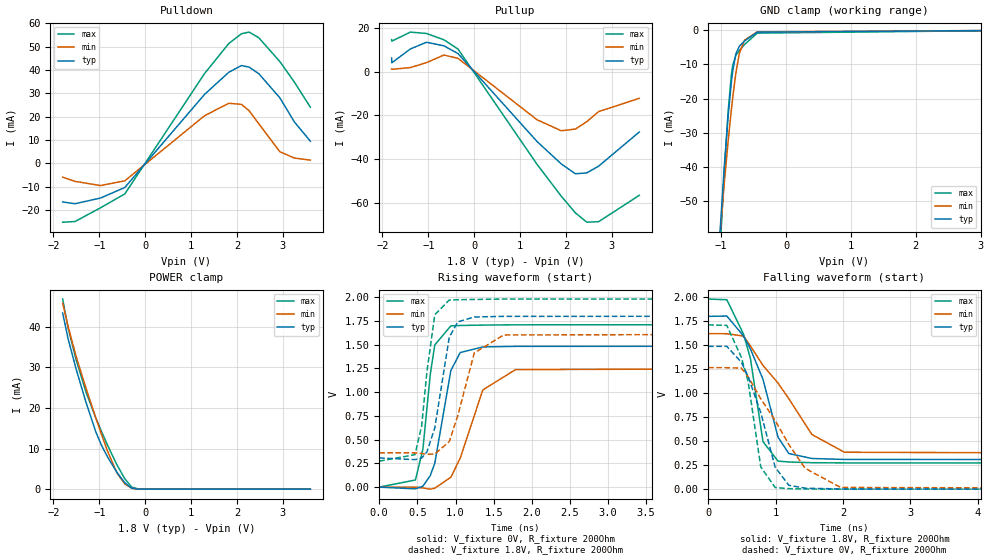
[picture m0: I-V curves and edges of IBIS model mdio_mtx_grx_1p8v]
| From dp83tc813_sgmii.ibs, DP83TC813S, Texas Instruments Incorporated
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| mdio_mtx_grx_1p8v
[Model]   mdio_mtx_grx_1p8v
Model_type   I/O
Polarity   Non-Inverting
Enable   Active-Low
Vinl = 0.63
Vinh = 1.17
Vmeas = 0.9
Vref = 0.9
Cref = 2pF
Rref = 100000
|   typ   min   max
C_comp   2.12pF   2.1pF   2.15pF
[Voltage Range]   1.8   1.62   1.98
[Temperature Range]   27   150   -40
[Pullup Reference]   1.8   1.62   1.98
[Pulldown Reference]   0   0   0
[Power Clamp Reference]   1.8   1.62   1.98
[GND Clamp Reference]   0   0   0
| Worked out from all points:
|   slope of the pulldown table from 0 to 0.27 V, typ, clamps not added: 41.1 ohm
|   slope of the pullup table from 0 to 0.27 V, typ, clamps not added: 40.5 ohm
|   GND clamp passes 1 mA (typ) near -0.48 V on its own axis
|   POWER clamp passes 1 mA (typ) near -0.39 V on its own axis
|   falling waveform, V_fixture 1.8V, R_fixture 200Ohm: 20-80 % time 408ps typ, 753ps min, 268ps max; typ from 1.8 V to 0.307 V
|   rising waveform, V_fixture 0V, R_fixture 200Ohm: 20-80 % time 184ps typ, 311ps min, 137ps max; typ from 0 V to 1.49 V
|   rising waveform, V_fixture 1.8V, R_fixture 200Ohm: 20-80 % time 169ps typ, 235ps min, 133ps max; typ from 0.307 V to 1.8 V
|   falling waveform, V_fixture 0V, R_fixture 200Ohm: 20-80 % time 376ps typ, 673ps min, 250ps max; typ from 1.49 V to 0 V
[Pulldown]
|   Voltage   I(typ)   I(min)   I(max)
-1.8V     -16.61mA   -5.947mA   -25.29mA
-1.53V    -17.36mA   -7.777mA   -25mA
-973.8mV  -14.92mA   -9.557mA   -19.1mA
-444.6mV  -10.39mA   -7.539mA   -13.15mA
1.294V    29.56mA    20.41mA    38.51mA
1.823V    39.07mA    25.75mA    51.41mA
2.099V    41.94mA    25.27mA    55.59mA
2.266V    41.26mA    22.56mA    56.3mA
2.477V    38.44mA    16.93mA    53.86mA
2.936V    28.08mA    4.971mA    43.64mA
3.249V    17.82mA    2.251mA    34.94mA
3.6V      9.489mA    1.359mA    24.09mA
[GND Clamp]
|   Voltage   I(typ)   I(min)   I(max)
-1.8V     -336.1mA   -294mA     -377.2mA
-1.044V   -67.3mA    -66.5mA    -74.32mA
-1.006V   -55.59mA   -57.15mA   -60.5mA
-946.8mV  -38.53mA   -43.59mA   -40.01mA
-892.8mV  -25.18mA   -32.5mA    -23.85mA
-844.2mV  -15.46mA   -23.5mA    -13.26mA
-822.6mV  -12.02mA   -19.84mA   -10.34mA
-774mV    -6.89mA    -12.58mA   -7.326mA
-720mV    -4.668mA   -6.753mA   -5.905mA
-639mV    -3.109mA   -2.848mA   -4.151mA
-444.6mV  -532.9uA   -446.3uA   -818uA
3.6V      0A         0A         0A
[Pullup]
|   Voltage   I(typ)   I(min)   I(max)
-1.8V     6.22mA     1.188mA    14.62mA
-1.795V   4.054mA    1.043mA    13.95mA
-1.39V    10.39mA    1.866mA    18.09mA
-1.039V   13.43mA    4.114mA    17.44mA
-660.6mV  11.82mA    7.583mA    14.58mA
-352.8mV  8.262mA    6.081mA    10.34mA
1.37V     -31.95mA   -22mA      -42.39mA
1.899V    -42.23mA   -27.04mA   -56.98mA
2.207V    -46.73mA   -26.27mA   -64.62mA
2.455V    -46.33mA   -22.91mA   -68.88mA
2.714V    -43.23mA   -18.28mA   -68.64mA
3.6V      -27.62mA   -12.21mA   -56.59mA
[POWER Clamp]
|   Voltage   I(typ)   I(min)   I(max)
-1.8V     43.38mA    45.82mA    46.84mA
-1.681V   37.05mA    40.07mA    39.68mA
-1.508V   29.65mA    32.74mA    31.93mA
-1.292V   21.44mA    24.91mA    23.94mA
-1.082V   14.27mA    17.71mA    17.68mA
-963mV    11.04mA    13.8mA     14.48mA
-822.6mV  7.958mA    9.405mA    10.86mA
-617.4mV  4.151mA    3.997mA    6.014mA
-444.6mV  1.573mA    1.284mA    2.566mA
-293.4mV  232.3uA    227.3uA    490.3uA
-136.8mV  3.538uA    9.732uA    5.794uA
3.6V      0A         0A         0A
[Ramp]
R_load = 200
|   typ   min   max
dV/dt_r   0.892389/1.81073e-10   0.759601/3.10645e-10   1.02679/1.36983e-10
dV/dt_f   0.895516/4.08036e-10   0.754921/7.52235e-10   1.02395/2.67052e-10
[Falling Waveform]
V_fixture = 1.8V
V_fixture_min = 1.62V
V_fixture_max = 1.98V
R_fixture = 200Ohm
C_fixture = 0F
|   Time   V(typ)   V(min)   V(max)
0s        1.8V       1.62V      1.98V
276.7ps   1.803V     1.619V     1.973V
524ps     1.596V     1.594V     1.615V
626.1ps   1.461V     1.492V     1.363V
812.7ps   1.145V     1.289V     495.7mV
1.036ns   542.1mV    1.105V     292.1mV
1.196ns   371.1mV    942.3mV    283.1mV
1.538ns   319.5mV    569.6mV    275.6mV
2.021ns   309.6mV    384.6mV    273.4mV
12ns      307.4mV    361.7mV    273.4mV
[Rising Waveform]
V_fixture = 0V
V_fixture_min = 0V
V_fixture_max = 0V
R_fixture = 200Ohm
C_fixture = 0F
|   Time   V(typ)   V(min)   V(max)
0s        534.9nV    8.425uV    224.8nV
474.7ps   -17.92mV   -402.7uV   75.28mV
572.4ps   10.5mV     -8.954mV   399mV
668.9ps   120.7mV    -21.33mV   1.185V
728.4ps   251.9mV    -11.06mV   1.497V
938.9ps   1.227V     104.5mV    1.698V
1.062ns   1.417V     305.8mV    1.702V
1.358ns   1.476V     1.023V     1.706V
1.786ns   1.482V     1.237V     1.709V
12ns      1.487V     1.266V     1.711V
[Rising Waveform]
V_fixture = 1.8V
V_fixture_min = 1.62V
V_fixture_max = 1.98V
R_fixture = 200Ohm
C_fixture = 0F
|   Time   V(typ)   V(min)   V(max)
0s        307.4mV    361.7mV    273.4mV
468.6ps   289.8mV    361.3mV    342.1mV
556.3ps   306.3mV    354.5mV    643.3mV
624.7ps   370.8mV    345.3mV    1.212V
728.4ps   623.2mV    349.2mV    1.815V
918.5ps   1.579V     479mV      1.97V
1.03ns    1.74V      752.4mV    1.973V
1.246ns   1.791V     1.413V     1.976V
1.631ns   1.798V     1.602V     1.98V
12ns      1.8V       1.62V      1.98V
[Falling Waveform]
|Gnd
V_fixture = 0V
V_fixture_min = 0V
V_fixture_max = 0V
R_fixture = 200Ohm
C_fixture = 0F
|   Time   V(typ)   V(min)   V(max)
0s        1.487V     1.266V     1.711V
275.7ps   1.488V     1.265V     1.706V
491.1ps   1.323V     1.261V     1.375V
590.4ps   1.177V     1.174V     1.129V
780ps     797.4mV    941.5mV    231.5mV
994.1ps   227.8mV    715.1mV    16.73mV
1.196ns   40.64mV    465.6mV    5.236mV
1.436ns   10.26mV    218.3mV    1.905mV
1.964ns   1.912mV    17.63mV    60.45uV
12ns      701.3nV    8.425uV    337.2nV
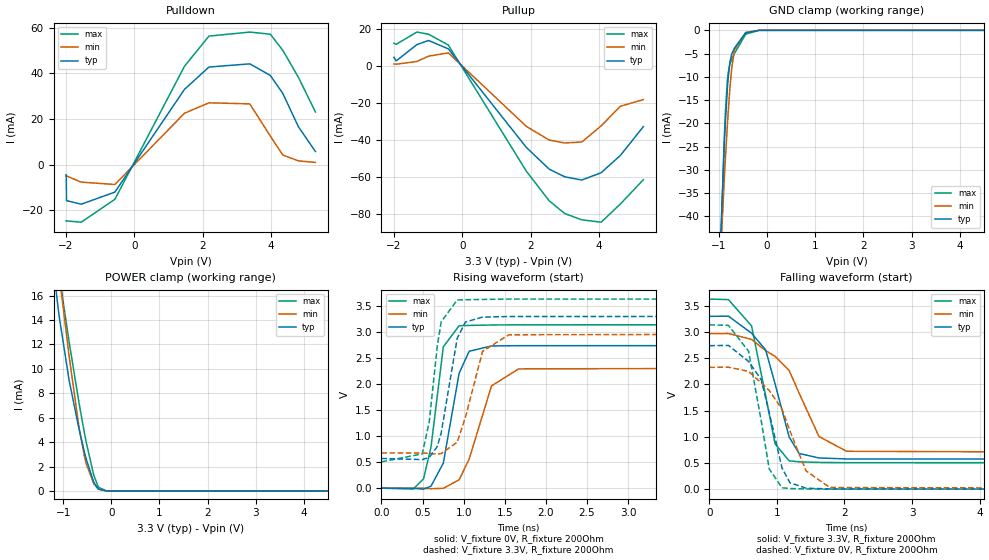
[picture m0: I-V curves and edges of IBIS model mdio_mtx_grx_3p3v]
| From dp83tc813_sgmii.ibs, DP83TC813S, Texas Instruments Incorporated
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| mdio_mtx_grx_3p3v
[Model]   mdio_mtx_grx_3p3v
Model_type   I/O
Polarity   Non-Inverting
Enable   Active-Low
Vinl = 0.8
Vinh = 2
Vmeas = 1.65
Vref = 1.65
Cref = 2pF
Rref = 100000
|   typ   min   max
C_comp   2.12pF   2.1pF   2.15pF
[Voltage Range]   3.3   2.97   3.63
[Temperature Range]   27   150   -40
[Pullup Reference]   3.3   2.97   3.63
[Pulldown Reference]   0   0   0
[Power Clamp Reference]   3.3   2.97   3.63
[GND Clamp Reference]   0   0   0
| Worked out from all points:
|   slope of the pulldown table from 0 to 0.495 V, typ, clamps not added: 41.6 ohm
|   slope of the pullup table from 0 to 0.495 V, typ, clamps not added: 39.9 ohm
|   GND clamp passes 1 mA (typ) near -0.49 V on its own axis
|   POWER clamp passes 1 mA (typ) near -0.39 V on its own axis
|   falling waveform, V_fixture 3.3V, R_fixture 200Ohm: 20-80 % time 353ps typ, 559ps min, 269ps max; typ from 3.3 V to 0.57 V
|   rising waveform, V_fixture 0V, R_fixture 200Ohm: 20-80 % time 180ps typ, 262ps min, 141ps max; typ from 0 V to 2.74 V
|   rising waveform, V_fixture 3.3V, R_fixture 200Ohm: 20-80 % time 166ps typ, 215ps min, 136ps max; typ from 0.57 V to 3.3 V
|   falling waveform, V_fixture 0V, R_fixture 200Ohm: 20-80 % time 307ps typ, 478ps min, 237ps max; typ from 2.74 V to 0 V
[Pulldown]
|   Voltage   I(typ)   I(min)   I(max)
-2V       -4.403mA   -4.924mA   -24.58mA
-1.993V   -4.541mA   -4.935mA   -24.61mA
-1.985V   -15.75mA   -4.948mA   -24.64mA
-1.555V   -17.32mA   -7.649mA   -25.19mA
-569.2mV  -12.01mA   -8.684mA   -15.16mA
1.468V    32.96mA    22.51mA    43.09mA
2.183V    42.73mA    27.07mA    56.27mA
3.38V     44.12mA    26.6mA     58.03mA
3.979V    39.05mA    12.51mA    57.1mA
4.344V    31.2mA     4.22mA     50.08mA
4.804V    16.53mA    1.646mA    38.17mA
5.3V      5.73mA     980.5uA    23.02mA
[GND Clamp]
|   Voltage   I(typ)   I(min)   I(max)
-2V       -410.8mA   -357.7mA   -461.5mA
-1.007V   -55.89mA   -57.39mA   -60.86mA
-890.4mV  -24.64mA   -32.04mA   -23.22mA
-868.5mV  -20.01mA   -27.88mA   -17.94mA
-824.7mV  -12.32mA   -20.18mA   -10.57mA
-810.1mV  -10.34mA   -17.83mA   -9.189mA
-773.6mV  -6.863mA   -12.53mA   -7.313mA
-737.1mV  -5.15mA    -8.294mA   -6.305mA
-678.7mV  -3.802mA   -4.182mA   -4.99mA
-445.1mV  -537.1uA   -449.4uA   -823.9uA
-167.7mV  -236.5nA   -1.623uA   -101.3nA
5.3V      0A         0A         0A
[Pullup]
|   Voltage   I(typ)   I(min)   I(max)
-2V       4.752mA    1.124mA    12.3mA
-1.934V   2.806mA    1.026mA    11.77mA
-1.328V   11.59mA    2.48mA     18.37mA
-985.3mV  13.84mA    5.379mA    17.21mA
-408.6mV  9.312mA    7.134mA    11.39mA
1.876V    -43.96mA   -32.6mA    -56.81mA
2.548V    -55.74mA   -40mA      -72.87mA
3.001V    -59.83mA   -41.53mA   -79.7mA
3.497V    -61.57mA   -41.03mA   -83.07mA
4.066V    -57.61mA   -32.28mA   -84.35mA
4.628V    -48.27mA   -21.7mA    -74.5mA
5.3V      -32.69mA   -18.12mA   -61.39mA
[POWER Clamp]
|   Voltage   I(typ)   I(min)   I(max)
-2V       56.47mA    56.33mA    67.3mA
-1.248V   19.83mA    23.38mA    22.5mA
-1.109V   15.13mA    18.64mA    18.44mA
-1.08V    14.23mA    17.66mA    17.64mA
-875.8mV  9.061mA    11.03mA    12.2mA
-671.4mV  5.088mA    5.236mA    7.225mA
-561.9mV  3.245mA    2.915mA    4.826mA
-518.1mV  2.577mA    2.208mA    3.938mA
-364.8mV  712.3uA    594.6uA    1.305mA
-269.9mV  142.9uA    154.2uA    311.7uA
-102mV    1.056uA    4.096uA    1.413uA
5.3V      0A         0A         0A
[Ramp]
R_load = 200
|   typ   min   max
dV/dt_r   1.64368/1.78613e-10   1.39503/2.6102e-10   1.8827/1.40644e-10
dV/dt_f   1.63826/3.52326e-10   1.37585/5.57652e-10   1.87516/2.67167e-10
[Falling Waveform]
V_fixture = 3.3V
V_fixture_min = 2.97V
V_fixture_max = 3.63V
R_fixture = 200Ohm
C_fixture = 0F
|   Time   V(typ)   V(min)   V(max)
0s        3.3V       2.97V      3.63V
282ps     3.304V     2.973V     3.62V
624.4ps   2.979V     2.86V      3.118V
833.6ps   2.658V     2.645V     1.783V
972ps     2.014V     2.536V     866.1mV
1.181ns   996.5mV    2.267V     541.2mV
1.328ns   682.2mV    1.835V     521.9mV
1.623ns   595.8mV    1.005V     511.2mV
2.031ns   577.1mV    723.4mV    505.7mV
12ns      569.5mV    676.9mV    504.7mV
[Rising Waveform]
V_fixture = 0V
V_fixture_min = 0V
V_fixture_max = 0V
R_fixture = 200Ohm
C_fixture = 0F
|   Time   V(typ)   V(min)   V(max)
0s        588.6nV    8.934uV    352.6nV
387.8ps   -2.528mV   -272.2uV   -16.8mV
512.6ps   -19.19mV   -1.192mV   180.2mV
603.3ps   38.47mV    -10.73mV   792.5mV
752.7ps   480.9mV    -2.587mV   2.714V
945.2ps   2.207V     161mV      3.119V
1.067ns   2.628V     558.3mV    3.124V
1.339ns   2.73V      1.964V     3.132V
1.669ns   2.735V     2.29V      3.136V
12ns      2.739V     2.325V     3.138V
[Rising Waveform]
V_fixture = 3.3V
V_fixture_min = 2.97V
V_fixture_max = 3.63V
R_fixture = 200Ohm
C_fixture = 0F
|   Time   V(typ)   V(min)   V(max)
0s        569.5mV    676.9mV    504.7mV
496.3ps   549.3mV    676.4mV    657.7mV
580.9ps   588.7mV    666.9mV    1.266V
678.5ps   797.6mV    654.2mV    2.715V
726.4ps   1.057V     664.1mV    3.192V
921.3ps   2.876V     880.9mV    3.613V
1.022ns   3.189V     1.363V     3.617V
1.23ns    3.284V     2.626V     3.623V
1.55ns    3.295V     2.945V     3.63V
12ns      3.3V       2.97V      3.63V
[Falling Waveform]
|Gnd
V_fixture = 0V
V_fixture_min = 0V
V_fixture_max = 0V
R_fixture = 200Ohm
C_fixture = 0F
|   Time   V(typ)   V(min)   V(max)
0s        2.74V      2.326V     3.138V
282ps     2.745V     2.329V     3.128V
580.9ps   2.439V     2.249V     2.634V
767.6ps   2.09V      2.029V     1.305V
886.2ps   1.46V      1.883V     385.2mV
1.075ns   406.9mV    1.532V     27.19mV
1.192ns   123mV      1.115V     12.24mV
1.43ns    18.79mV    350.9mV    4.725mV
1.782ns   4.844mV    31.51mV    172.8uV
12ns      750.5nV    9.194uV    441.3nV
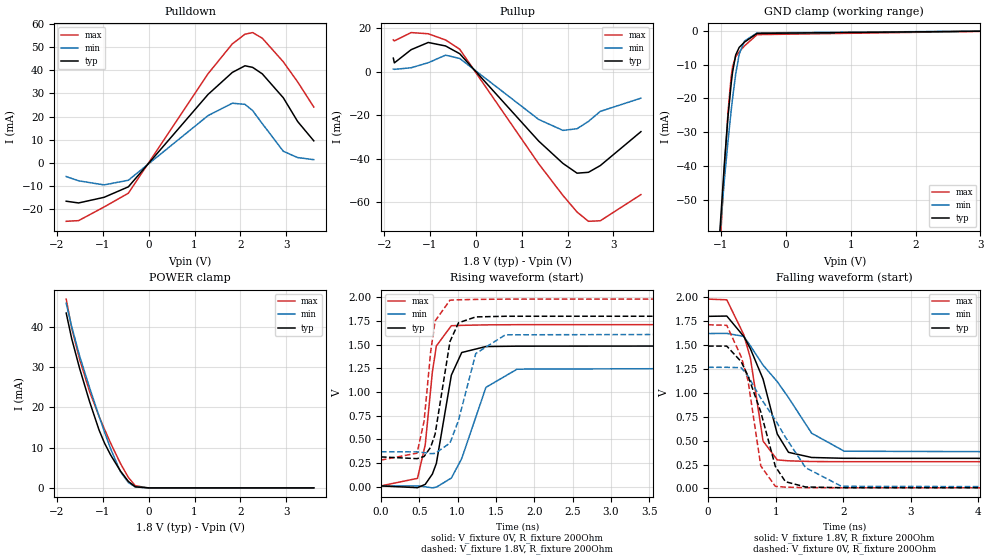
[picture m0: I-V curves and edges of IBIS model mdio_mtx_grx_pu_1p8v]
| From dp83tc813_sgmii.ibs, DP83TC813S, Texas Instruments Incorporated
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| mdio_mtx_grx_pu_1p8v
[Model]   mdio_mtx_grx_pu_1p8v
Model_type   I/O
Polarity   Non-Inverting
Enable   Active-Low
Vinl = 0.63
Vinh = 1.17
Vmeas = 0.9
Vref = 0.9
Cref = 2pF
Rref = 100000
|   typ   min   max
C_comp   2.12pF   2.10pF   2.14pF
[Voltage Range]   1.8   1.62   1.98
[Temperature Range]   27   150   -40
[Pullup Reference]   1.8   1.62   1.98
[Pulldown Reference]   0   0   0
[Power Clamp Reference]   1.8   1.62   1.98
[GND Clamp Reference]   0   0   0
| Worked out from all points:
|   slope of the pulldown table from 0 to 0.27 V, typ, clamps not added: 41.1 ohm
|   slope of the pullup table from 0 to 0.27 V, typ, clamps not added: 40.5 ohm
|   GND clamp passes 1 mA (typ) near -0.46 V on its own axis
|   POWER clamp passes 1 mA (typ) near -0.39 V on its own axis
|   falling waveform, V_fixture 1.8V, R_fixture 200Ohm: 20-80 % time 407ps typ, 753ps min, 269ps max; typ from 1.8 V to 0.313 V
|   rising waveform, V_fixture 0V, R_fixture 200Ohm: 20-80 % time 181ps typ, 310ps min, 137ps max; typ from 0.007 V to 1.49 V
|   rising waveform, V_fixture 1.8V, R_fixture 200Ohm: 20-80 % time 169ps typ, 233ps min, 132ps max; typ from 0.313 V to 1.8 V
|   falling waveform, V_fixture 0V, R_fixture 200Ohm: 20-80 % time 374ps typ, 673ps min, 251ps max; typ from 1.49 V to 0.007 V
[Pulldown]
|   Voltage   I(typ)   I(min)   I(max)
-1.8V     -16.61mA   -5.947mA   -25.29mA
-1.53V    -17.36mA   -7.777mA   -25mA
-973.8mV  -14.92mA   -9.557mA   -19.1mA
-444.6mV  -10.39mA   -7.539mA   -13.15mA
1.294V    29.56mA    20.41mA    38.51mA
1.823V    39.07mA    25.75mA    51.41mA
2.099V    41.94mA    25.27mA    55.59mA
2.266V    41.26mA    22.56mA    56.3mA
2.477V    38.44mA    16.93mA    53.86mA
2.936V    28.08mA    4.971mA    43.64mA
3.249V    17.82mA    2.251mA    34.94mA
3.6V      9.489mA    1.359mA    24.09mA
[GND Clamp]
|   Voltage   I(typ)   I(min)   I(max)
-1.8V     -336.4mA   -294.2mA   -377.5mA
-1.044V   -67.54mA   -66.68mA   -74.64mA
-1.006V   -55.83mA   -57.33mA   -60.82mA
-946.8mV  -38.77mA   -43.78mA   -40.33mA
-892.8mV  -25.42mA   -32.68mA   -24.17mA
-844.2mV  -15.7mA    -23.68mA   -13.58mA
-822.6mV  -12.26mA   -20.02mA   -10.66mA
-774mV    -7.13mA    -12.76mA   -7.644mA
-720mV    -4.907mA   -6.934mA   -6.222mA
-639mV    -3.348mA   -3.03mA    -4.466mA
-444.6mV  -767.3uA   -623.7uA   -1.129mA
3.6V      0A         0A         0A
[Pullup]
|   Voltage   I(typ)   I(min)   I(max)
-1.8V     6.22mA     1.188mA    14.62mA
-1.778V   4.031mA    1.063mA    14.17mA
-1.411V   10.12mA    1.794mA    17.99mA
-1.039V   13.43mA    4.114mA    17.44mA
-660.6mV  11.82mA    7.583mA    14.58mA
-352.8mV  8.262mA    6.081mA    10.34mA
1.37V     -31.95mA   -22mA      -42.39mA
1.899V    -42.23mA   -27.04mA   -56.98mA
2.207V    -46.73mA   -26.27mA   -64.62mA
2.455V    -46.33mA   -22.91mA   -68.88mA
2.714V    -43.23mA   -18.28mA   -68.64mA
3.6V      -27.62mA   -12.21mA   -56.59mA
[POWER Clamp]
|   Voltage   I(typ)   I(min)   I(max)
-1.8V     43.43mA    45.85mA    46.89mA
-1.681V   37.1mA     40.1mA     39.73mA
-1.508V   29.7mA     32.78mA    31.98mA
-1.292V   21.48mA    24.95mA    23.99mA
-1.082V   14.32mA    17.75mA    17.73mA
-963mV    11.08mA    13.83mA    14.53mA
-828mV    8.108mA    9.6mA      11.04mA
-617.4mV  4.189mA    4.028mA    6.056mA
-444.6mV  1.607mA    1.312mA    2.604mA
-293.4mV  259.8uA    249.4uA    522.6uA
-12.6mV   1.365uA    1.259uA    1.674uA
3.6V      0A         0A         0A
[Ramp]
R_load = 200
|   typ   min   max
dV/dt_r   0.889189/1.8029e-10   0.756668/3.07293e-10   1.02308/1.3633e-10
dV/dt_f   0.892188/4.07569e-10   0.751842/7.5158e-10   1.02019/2.66952e-10
[Falling Waveform]
V_fixture = 1.8V
V_fixture_min = 1.62V
V_fixture_max = 1.98V
R_fixture = 200Ohm
C_fixture = 0F
|   Time   V(typ)   V(min)   V(max)
0s        1.8V       1.62V      1.98V
276.9ps   1.803V     1.622V     1.973V
529ps     1.589V     1.59V      1.607V
626.8ps   1.46V      1.491V     1.361V
813.8ps   1.143V     1.289V     495.5mV
1.023ns   570.5mV    1.118V     298.8mV
1.19ns    377.9mV    950mV      289.1mV
1.532ns   324mV      577.9mV    281.7mV
2.015ns   315.5mV    389.6mV    279.8mV
12ns      313mV      366.8mV    279.6mV
[Rising Waveform]
V_fixture = 0V
V_fixture_min = 0V
V_fixture_max = 0V
R_fixture = 200Ohm
C_fixture = 0F
|   Time   V(typ)   V(min)   V(max)
0s        6.536mV    6.31mV     7.158mV
476.7ps   -12.08mV   5.883mV    86.33mV
577.8ps   23.13mV    -2.759mV   440.4mV
671ps     131.6mV    -14mV      1.21V
723.3ps   245.5mV    -6.063mV   1.486V
918.7ps   1.177V     89.49mV    1.699V
1.054ns   1.416V     295.9mV    1.703V
1.37ns    1.479V     1.048V     1.708V
1.777ns   1.483V     1.24V      1.71V
12ns      1.489V     1.267V     1.712V
[Rising Waveform]
V_fixture = 1.8V
V_fixture_min = 1.62V
V_fixture_max = 1.98V
R_fixture = 200Ohm
C_fixture = 0F
|   Time   V(typ)   V(min)   V(max)
0s        313mV      366.8mV    279.6mV
470.8ps   294.7mV    366.4mV    352.6mV
562.6ps   317.2mV    358.8mV    690mV
648.6ps   415.3mV    347.1mV    1.423V
706.7ps   553.3mV    349.7mV    1.749V
900.6ps   1.532V     459.5mV    1.969V
1.012ns   1.73V      699mV      1.973V
1.237ns   1.792V     1.405V     1.977V
1.623ns   1.799V     1.603V     1.98V
12ns      1.8V       1.62V      1.98V
[Falling Waveform]
|Gnd
V_fixture = 0V
V_fixture_min = 0V
V_fixture_max = 0V
R_fixture = 200Ohm
C_fixture = 0F
|   Time   V(typ)   V(min)   V(max)
0s        1.489V     1.267V     1.712V
276ps     1.489V     1.267V     1.706V
489.9ps   1.326V     1.263V     1.378V
590.4ps   1.178V     1.176V     1.131V
779.8ps   800.3mV    944mV      235.7mV
995.3ps   230.3mV    716.2mV    22.19mV
1.145ns   70.63mV    535.5mV    13.83mV
1.443ns   15.53mV    217.3mV    8.735mV
1.974ns   8.254mV    22.6mV     7.174mV
12ns      6.535mV    6.31mV     7.158mV
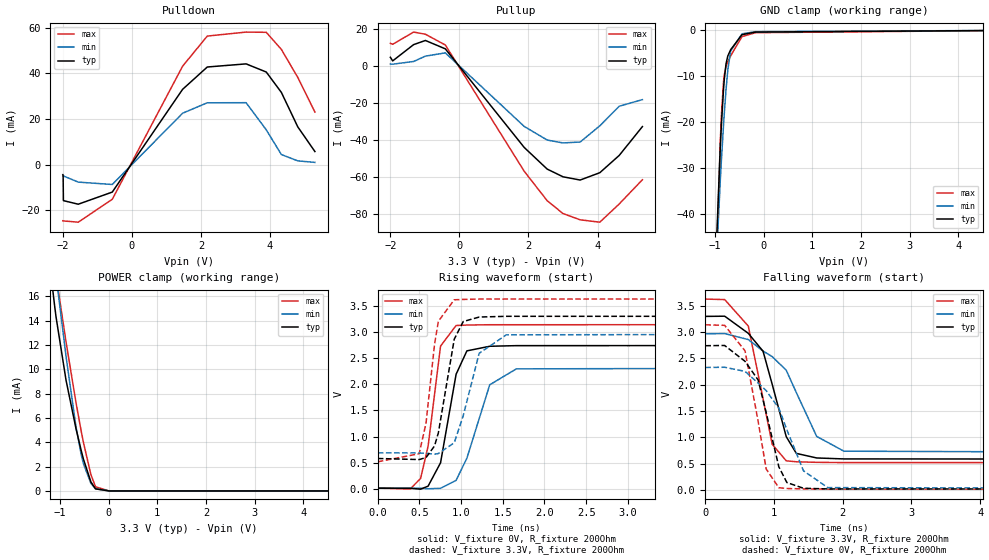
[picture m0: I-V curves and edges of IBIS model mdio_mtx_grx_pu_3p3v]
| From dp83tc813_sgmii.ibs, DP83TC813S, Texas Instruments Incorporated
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| mdio_mtx_grx_pu_3p3v
[Model]   mdio_mtx_grx_pu_3p3v
Model_type   I/O
Polarity   Non-Inverting
Enable   Active-Low
Vinl = 0.8
Vinh = 2
Vmeas = 1.65
Vref = 1.65
Cref = 2pF
Rref = 100000
|   typ   min   max
C_comp   2.12pF   2.1pF   2.14pF
[Voltage Range]   3.3   2.97   3.63
[Temperature Range]   27   150   -40
[Pullup Reference]   3.3   2.97   3.63
[Pulldown Reference]   0   0   0
[Power Clamp Reference]   3.3   2.97   3.63
[GND Clamp Reference]   0   0   0
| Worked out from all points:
|   slope of the pulldown table from 0 to 0.495 V, typ, clamps not added: 41.6 ohm
|   slope of the pullup table from 0 to 0.495 V, typ, clamps not added: 39.9 ohm
|   GND clamp passes 1 mA (typ) near -0.45 V on its own axis
|   POWER clamp passes 1 mA (typ) near -0.39 V on its own axis
|   falling waveform, V_fixture 3.3V, R_fixture 200Ohm: 20-80 % time 353ps typ, 559ps min, 269ps max; typ from 3.3 V to 0.58 V
|   rising waveform, V_fixture 0V, R_fixture 200Ohm: 20-80 % time 178ps typ, 260ps min, 141ps max; typ from 0.012 V to 2.74 V
|   rising waveform, V_fixture 3.3V, R_fixture 200Ohm: 20-80 % time 165ps typ, 214ps min, 135ps max; typ from 0.58 V to 3.3 V
|   falling waveform, V_fixture 0V, R_fixture 200Ohm: 20-80 % time 307ps typ, 478ps min, 237ps max; typ from 2.74 V to 0.012 V
[Pulldown]
|   Voltage   I(typ)   I(min)   I(max)
-2V       -4.403mA   -4.924mA   -24.58mA
-1.993V   -4.541mA   -4.935mA   -24.61mA
-1.985V   -15.75mA   -4.948mA   -24.64mA
-1.555V   -17.32mA   -7.649mA   -25.19mA
-569.2mV  -12.01mA   -8.684mA   -15.16mA
1.468V    32.96mA    22.51mA    43.09mA
2.183V    42.73mA    27.07mA    56.27mA
3.307V    44.1mA     27.11mA    58.01mA
3.891V    40.53mA    15.22mA    57.91mA
4.329V    31.6mA     4.414mA    50.42mA
4.804V    16.53mA    1.646mA    38.17mA
5.3V      5.73mA     980.5uA    23.02mA
[GND Clamp]
|   Voltage   I(typ)   I(min)   I(max)
-2V       -411.3mA   -358mA     -462.1mA
-1.007V   -56.3mA    -57.7mA    -61.41mA
-890.4mV  -25.05mA   -32.35mA   -23.77mA
-868.5mV  -20.42mA   -28.19mA   -18.49mA
-824.7mV  -12.74mA   -20.5mA    -11.12mA
-810.1mV  -10.75mA   -18.14mA   -9.736mA
-773.6mV  -7.273mA   -12.84mA   -7.86mA
-737.1mV  -5.56mA    -8.607mA   -6.851mA
-678.7mV  -4.211mA   -4.494mA   -5.536mA
-445.1mV  -941.1uA   -756.5uA   -1.363mA
-167.7mV  -380.7uA   -289.5uA   -511.4uA
5.3V      0A         0A         0A
[Pullup]
|   Voltage   I(typ)   I(min)   I(max)
-2V       4.752mA    1.124mA    12.3mA
-1.934V   2.807mA    1.026mA    11.77mA
-1.328V   11.59mA    2.48mA     18.37mA
-985.3mV  13.84mA    5.379mA    17.21mA
-408.6mV  9.312mA    7.134mA    11.39mA
1.876V    -43.96mA   -32.6mA    -56.81mA
2.541V    -55.65mA   -39.95mA   -72.73mA
3.001V    -59.83mA   -41.53mA   -79.7mA
3.497V    -61.57mA   -41.03mA   -83.07mA
4.066V    -57.61mA   -32.28mA   -84.35mA
4.628V    -48.27mA   -21.7mA    -74.5mA
5.3V      -32.69mA   -18.12mA   -61.4mA
[POWER Clamp]
|   Voltage   I(typ)   I(min)   I(max)
-2V       56.52mA    56.37mA    67.37mA
-1.248V   19.88mA    23.41mA    22.56mA
-1.109V   15.17mA    18.68mA    18.5mA
-1.08V    14.27mA    17.7mA     17.69mA
-875.8mV  9.104mA    11.06mA    12.25mA
-671.4mV  5.128mA    5.269mA    7.27mA
-561.9mV  3.283mA    2.947mA    4.869mA
-518.1mV  2.614mA    2.238mA    3.979mA
-364.8mV  743.9uA    620.5uA    1.342mA
-269.9mV  169.6uA    175.9uA    343.1uA
7.5mV     0A         0A         0A
5.3V      0A         0A         0A
[Ramp]
R_load = 200
|   typ   min   max
dV/dt_r   1.6377/1.77579e-10   1.38953/2.59061e-10   1.8758/1.39983e-10
dV/dt_f   1.63191/3.52219e-10   1.36981/5.58182e-10   1.86805/2.67002e-10
[Falling Waveform]
V_fixture = 3.3V
V_fixture_min = 2.97V
V_fixture_max = 3.63V
R_fixture = 200Ohm
C_fixture = 0F
|   Time   V(typ)   V(min)   V(max)
0s        3.3V       2.97V      3.63V
282.3ps   3.304V     2.973V     3.62V
625.7ps   2.978V     2.859V     3.116V
840.5ps   2.637V     2.64V      1.734V
973.8ps   2.006V     2.535V     865.2mV
1.178ns   1.011V     2.275V     551.3mV
1.325ns   692.5mV    1.849V     533mV
1.621ns   605.7mV    1.016V     522.6mV
2.017ns   587.6mV    734.7mV    517.4mV
12ns      580.1mV    686.9mV    516.6mV
[Rising Waveform]
V_fixture = 0V
V_fixture_min = 0V
V_fixture_max = 0V
R_fixture = 200Ohm
C_fixture = 0F
|   Time   V(typ)   V(min)   V(max)
0s        12.2mV     11.93mV    13.35mV
388ps     9.801mV    11.65mV    -3.337mV
513.5ps   -6.748mV   10.65mV    197.3mV
603.6ps   51.2mV     1.201mV    815.2mV
753ps     497.6mV    9.346mV    2.731V
939.5ps   2.191V     162mV      3.124V
1.069ns   2.639V     585.7mV    3.133V
1.343ns   2.727V     1.99V      3.139V
1.663ns   2.739V     2.295V     3.139V
12ns      2.742V     2.328V     3.14V
[Rising Waveform]
V_fixture = 3.3V
V_fixture_min = 2.97V
V_fixture_max = 3.63V
R_fixture = 200Ohm
C_fixture = 0F
|   Time   V(typ)   V(min)   V(max)
0s        580.1mV    686.9mV    516.6mV
496.8ps   559.7mV    686.5mV    672.1mV
578.5ps   597.8mV    677.3mV    1.254V
680.7ps   818.9mV    664mV      2.761V
726.7ps   1.071V     674.3mV    3.205V
917.3ps   2.862V     881.5mV    3.616V
1.025ns   3.2V       1.399V     3.623V
1.216ns   3.286V     2.592V     3.63V
1.542ns   3.3V       2.946V     3.63V
12ns      3.3V       2.97V      3.63V
[Falling Waveform]
|Gnd
V_fixture = 0V
V_fixture_min = 0V
V_fixture_max = 0V
R_fixture = 200Ohm
C_fixture = 0F
|   Time   V(typ)   V(min)   V(max)
0s        2.742V     2.328V     3.14V
281.1ps   2.747V     2.332V     3.13V
578.5ps   2.445V     2.254V     2.644V
768.3ps   2.091V     2.031V     1.306V
885.9ps   1.469V     1.888V     396.1mV
1.07ns    437.2mV    1.555V     39.34mV
1.187ns   138.2mV    1.141V     24.34mV
1.429ns   28.93mV    361mV      17.01mV
1.782ns   16.44mV    41.87mV    13.38mV
12ns      12.2mV     11.92mV    13.35mV
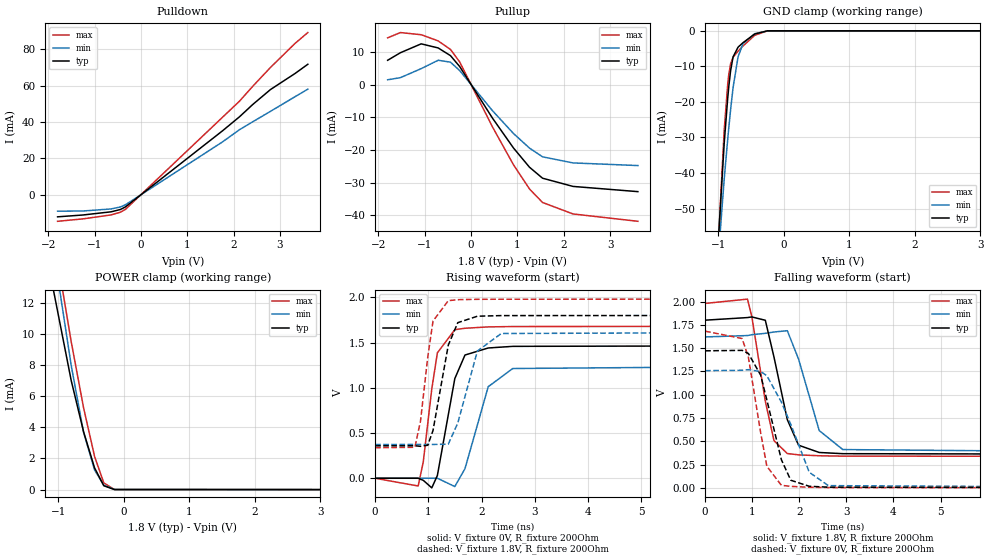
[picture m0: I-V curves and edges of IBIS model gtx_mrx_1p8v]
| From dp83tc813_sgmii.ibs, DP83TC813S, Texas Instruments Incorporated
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| gtx_mrx_1p8v
[Model]   gtx_mrx_1p8v
Model_type   I/O
Polarity   Non-Inverting
Enable   Active-Low
Vinl = 0.63
Vinh = 1.17
Vmeas = 0.9
Vref = 0.9
Cref = 2pF
Rref = 100000
|   typ   min   max
C_comp   2.78pF   2.74pF   2.80pF
[Voltage Range]   1.8   1.62   1.98
[Temperature Range]   27   150   -40
[Pullup Reference]   1.8   1.62   1.98
[Pulldown Reference]   0   0   0
[Power Clamp Reference]   1.8   1.62   1.98
[GND Clamp Reference]   0   0   0
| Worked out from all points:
|   slope of the pulldown table from 0 to 0.27 V, typ, clamps not added: 49.7 ohm
|   slope of the pullup table from 0 to 0.27 V, typ, clamps not added: 44.5 ohm
|   GND clamp passes 1 mA (typ) near -0.45 V on its own axis
|   POWER clamp passes 1 mA (typ) near -0.41 V on its own axis
|   falling waveform, V_fixture 1.8V, R_fixture 200Ohm: 20-80 % time 376ps typ, 425ps min, 316ps max; typ from 1.8 V to 0.358 V
|   rising waveform, V_fixture 0V, R_fixture 200Ohm: 20-80 % time 268ps typ, 359ps min, 218ps max; typ from 0 V to 1.47 V
|   rising waveform, V_fixture 1.8V, R_fixture 200Ohm: 20-80 % time 257ps typ, 337ps min, 198ps max; typ from 0.358 V to 1.8 V
|   falling waveform, V_fixture 0V, R_fixture 200Ohm: 20-80 % time 420ps typ, 600ps min, 329ps max; typ from 1.47 V to 0 V
[Pulldown]
|   Voltage   I(typ)   I(min)   I(max)
-1.8V     -12.09mA   -8.999mA   -14.55mA
-1.255V   -11.09mA   -8.889mA   -13.22mA
-644.4mV  -9.329mA   -7.759mA   -11.03mA
-444.6mV  -8.058mA   -6.661mA   -9.56mA
-336.6mV  -6.654mA   -5.485mA   -8.007mA
1.769V    35.4mA     29.27mA    42.88mA
2.126V    42.92mA    35.82mA    51.5mA
2.412V    49.68mA    40.17mA    59.68mA
2.795V    57.9mA     45.91mA    70.06mA
3.325V    66.72mA    53.96mA    83.27mA
3.6V      71.77mA    58.08mA    89.2mA
[GND Clamp]
|   Voltage   I(typ)   I(min)   I(max)
-1.8V     -366.8mA   -317.8mA   -407.9mA
-1.017V   -64.53mA   -67.73mA   -65.97mA
-909mV    -31.46mA   -41.59mA   -27.79mA
-855mV    -18.71mA   -30.27mA   -14.79mA
-838.8mV  -15.56mA   -27.12mA   -12.16mA
-811.8mV  -11.22mA   -22.15mA   -9.257mA
-774mV    -7.323mA   -15.95mA   -7.434mA
-698.4mV  -4.609mA   -7.329mA   -5.73mA
-622.8mV  -3.335mA   -3.629mA   -4.272mA
-444.6mV  -899.7uA   -816.3uA   -1.267mA
-250.2mV  -9.186uA   -26.26uA   -8.292uA
3.6V      0A         0A         0A
[Pullup]
|   Voltage   I(typ)   I(min)   I(max)
-1.8V     7.497mA    1.51mA     14.38mA
-1.525V   9.81mA     2.166mA    16mA
-1.076V   12.54mA    4.935mA    15.34mA
-709.2mV  11.28mA    7.503mA    13.44mA
-444.6mV  8.93mA     6.923mA    10.83mA
-244.8mV  5.572mA    4.336mA    6.984mA
462.6mV   -10.25mA   -7.972mA   -12.95mA
916.2mV   -19.42mA   -14.98mA   -24.57mA
1.262V    -25.32mA   -19.45mA   -32mA
1.543V    -28.68mA   -22.12mA   -36.13mA
2.201V    -31.2mA    -23.99mA   -39.65mA
3.6V      -32.8mA    -24.8mA    -41.9mA
[POWER Clamp]
|   Voltage   I(typ)   I(min)   I(max)
-1.8V     38.19mA    40.42mA    41.41mA
-1.719V   34.21mA    36.84mA    36.89mA
-1.687V   32.77mA    35.47mA    35.38mA
-1.568V   28.15mA    30.83mA    30.79mA
-1.33V    20.28mA    23.1mA     23.36mA
-1.071V   12.79mA    15.41mA    16.29mA
-801mV    7.003mA    7.97mA     9.5mA
-612mV    3.709mA    3.667mA    5.246mA
-444.6mV  1.392mA    1.256mA    2.129mA
-304.2mV  249.1uA    287.9uA    432.2uA
-142.2mV  3.423uA    14.68uA    2.99uA
3.6V      0A         0A         0A
[Ramp]
R_load = 200
|   typ   min   max
dV/dt_r   0.881686/2.65542e-10   0.753778/3.57723e-10   1.00897/2.15622e-10
dV/dt_f   0.864968/3.72852e-10   0.748227/4.23046e-10   0.985412/3.14897e-10
[Falling Waveform]
V_fixture = 1.8V
V_fixture_min = 1.62V
V_fixture_max = 1.98V
R_fixture = 200Ohm
C_fixture = 0F
|   Time   V(typ)   V(min)   V(max)
0s        1.8V       1.62V      1.98V
898.7ps   1.828V     1.635V     2.026V
991ps     1.835V     1.644V     1.839V
1.278ns   1.799V     1.659V     929.5mV
1.462ns   1.404V     1.673V     506.8mV
1.745ns   732.5mV    1.687V     368.3mV
1.984ns   458mV      1.383V     354.4mV
2.423ns   379.8mV    614.9mV    344.5mV
2.924ns   366.9mV    411.1mV    340.4mV
12ns      358.4mV    372.9mV    337.6mV
[Rising Waveform]
V_fixture = 0V
V_fixture_min = 0V
V_fixture_max = 0V
R_fixture = 200Ohm
C_fixture = 0F
|   Time   V(typ)   V(min)   V(max)
0s        11.81uV    92.2uV     6.524uV
809.3ps   55.48uV    138.2uV    -85.66mV
904.9ps   -22.81mV   143.7uV    180.5mV
1.065ns   -106.2mV   152.8uV    987.3mV
1.17ns    29.95mV    158.8uV    1.386V
1.498ns   1.102V     -91.68mV   1.642V
1.689ns   1.362V     105.5mV    1.658V
2.126ns   1.44V      1.012V     1.673V
2.587ns   1.458V     1.213V     1.677V
12ns      1.469V     1.256V     1.682V
[Rising Waveform]
V_fixture = 1.8V
V_fixture_min = 1.62V
V_fixture_max = 1.98V
R_fixture = 200Ohm
C_fixture = 0F
|   Time   V(typ)   V(min)   V(max)
0s        358.4mV    372.9mV    337.6mV
747.2ps   359.1mV    373.4mV    342.4mV
853.3ps   352.9mV    373.5mV    633mV
989.7ps   365.1mV    373.6mV    1.341V
1.088ns   527.6mV    373.6mV    1.737V
1.375ns   1.471V     376.5mV    1.963V
1.554ns   1.72V      610.4mV    1.974V
1.922ns   1.791V     1.406V     1.978V
2.371ns   1.798V     1.6V       1.979V
12ns      1.8V       1.62V      1.98V
[Falling Waveform]
|Gnd
V_fixture = 0V
V_fixture_min = 0V
V_fixture_max = 0V
R_fixture = 200Ohm
C_fixture = 0F
|   Time   V(typ)   V(min)   V(max)
0s        1.471V     1.258V     1.682V
784.8ps   1.476V     1.262V     1.603V
919.1ps   1.442V     1.269V     1.4V
1.179ns   1.21V      1.248V     592mV
1.311ns   942.4mV    1.204V     231.6mV
1.619ns   302.3mV    920.6mV    27.38mV
1.819ns   81.81mV    681.9mV    15.9mV
2.211ns   17.03mV    167.9mV    6.515mV
2.617ns   7.185mV    23.88mV    3.484mV
12ns      11.88uV    92.28uV    6.607uV
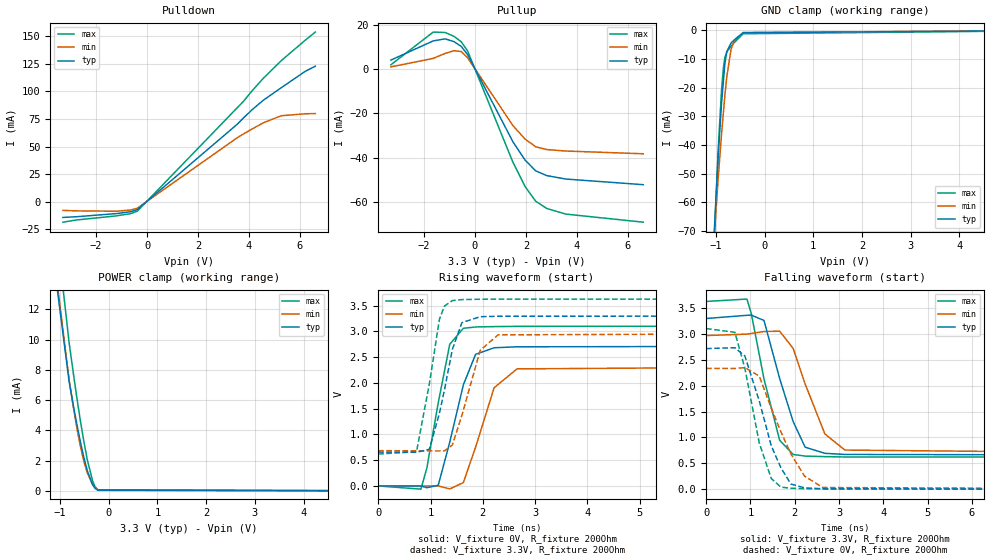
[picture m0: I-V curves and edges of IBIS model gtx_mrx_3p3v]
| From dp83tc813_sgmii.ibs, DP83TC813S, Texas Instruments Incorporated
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| gtx_mrx_3p3v
[Model]   gtx_mrx_3p3v
Model_type   I/O
Polarity   Non-Inverting
Enable   Active-Low
Vinl = 0.8
Vinh = 2
Vmeas = 1.65
Vref = 1.65
Cref = 2pF
Rref = 100000
|   typ   min   max
C_comp   2.75pF   2.71pF   2.76pF
[Voltage Range]   3.3   2.97   3.63
[Temperature Range]   27   150   -40
[Pullup Reference]   3.3   2.97   3.63
[Pulldown Reference]   0   0   0
[Power Clamp Reference]   3.3   2.97   3.63
[GND Clamp Reference]   0   0   0
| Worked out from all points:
|   slope of the pulldown table from 0 to 0.495 V, typ, clamps not added: 49.7 ohm
|   slope of the pullup table from 0 to 0.495 V, typ, clamps not added: 42.6 ohm
|   GND clamp passes 1 mA (typ) near -0.45 V on its own axis
|   POWER clamp passes 1 mA (typ) near -0.40 V on its own axis
|   falling waveform, V_fixture 3.3V, R_fixture 200Ohm: 20-80 % time 544ps typ, 596ps min, 467ps max; typ from 3.3 V to 0.658 V
|   rising waveform, V_fixture 0V, R_fixture 200Ohm: 20-80 % time 383ps typ, 419ps min, 325ps max; typ from 0 V to 2.72 V
|   rising waveform, V_fixture 3.3V, R_fixture 200Ohm: 20-80 % time 327ps typ, 374ps min, 273ps max; typ from 0.658 V to 3.3 V
|   falling waveform, V_fixture 0V, R_fixture 200Ohm: 20-80 % time 591ps typ, 714ps min, 472ps max; typ from 2.72 V to 0 V
[Pulldown]
|   Voltage   I(typ)   I(min)   I(max)
-3.3V     -14.49mA   -8.058mA   -18.8mA
-2.775V   -13.84mA   -8.495mA   -16.78mA
-1.211V   -11mA      -8.856mA   -13.1mA
-636.9mV  -9.29mA    -7.726mA   -10.99mA
-379.5mV  -7.291mA   -6.009mA   -8.741mA
3.521V    69.9mA     57.68mA    84.83mA
3.769V    75.65mA    61.21mA    90.72mA
4.125V    83.52mA    65.97mA    100.7mA
4.561V    92.04mA    71.53mA    112mA
5.263V    103.4mA    77.95mA    128mA
6.204V    118.3mA    79.76mA    146.6mA
6.6V      123mA      79.94mA    154mA
[GND Clamp]
|   Voltage   I(typ)   I(min)   I(max)
-3.3V     -975.7mA   -834.2mA   -1.088A
-1.082V   -87.39mA   -85.74mA   -92.35mA
-1.053V   -76.85mA   -77.39mA   -80.21mA
-953.7mV  -44.36mA   -51.95mA   -42.28mA
-884.4mV  -25.68mA   -36.44mA   -21.13mA
-844.8mV  -17.68mA   -28.61mA   -13.06mA
-815.1mV  -11.68mA   -22.74mA   -9.519mA
-775.5mV  -7.43mA    -16.18mA   -7.545mA
-686.4mV  -4.384mA   -6.481mA   -5.56mA
-617.1mV  -3.246mA   -3.463mA   -4.168mA
-438.9mV  -839.2uA   -766.6uA   -1.194mA
6.6V      0A         0A         0A
[Pullup]
|   Voltage   I(typ)   I(min)   I(max)
-3.3V     4.209mA    1.152mA    2.057mA
-1.637V   12.93mA    4.984mA    16.93mA
-1.171V   13.87mA    7.252mA    16.75mA
-815.1mV  12.56mA    8.506mA    14.96mA
-537.9mV  10.43mA    8.083mA    12.52mA
-290.4mV  6.774mA    5.309mA    8.451mA
1.492V    -32.92mA   -25.55mA   -42.2mA
1.967V    -41.16mA   -31.63mA   -53.19mA
2.383V    -46.05mA   -35.1mA    -59.82mA
2.818V    -48.19mA   -36.38mA   -63.11mA
3.561V    -49.75mA   -37.04mA   -65.65mA
6.6V      -52.31mA   -38.29mA   -69.33mA
[POWER Clamp]
|   Voltage   I(typ)   I(min)   I(max)
-3.3V     264.9mA    186.2mA    349.8mA
-1.657V   28.42mA    29.46mA    34.09mA
-815.1mV  7.28mA     7.394mA    9.85mA
-726mV    5.642mA    5.525mA    7.766mA
-646.8mV  4.28mA     4.026mA    5.994mA
-577.5mV  3.178mA    2.886mA    4.557mA
-508.2mV  2.184mA    1.935mA    3.238mA
-438.9mV  1.329mA    1.184mA    2.041mA
-330mV    399.7uA    414.1uA    652.2uA
-280.5mV  171.6uA    214.1uA    274.2uA
-221.1mV  37.73uA    74.54uA    57.76uA
6.6V      0A         0A         0A
[Ramp]
R_load = 200
|   typ   min   max
dV/dt_r   1.62996/3.82828e-10   1.40002/4.1712e-10   1.86315/3.24548e-10
dV/dt_f   1.58547/5.44448e-10   1.37108/5.92398e-10   1.8064/4.66779e-10
[Falling Waveform]
V_fixture = 3.3V
V_fixture_min = 2.97V
V_fixture_max = 3.63V
R_fixture = 200Ohm
C_fixture = 0F
|   Time   V(typ)   V(min)   V(max)
0s        3.3V       2.97V      3.63V
921.7ps   3.362V     2.998V     3.676V
1.019ns   3.366V     3.011V     3.399V
1.307ns   3.262V     3.049V     2.131V
1.66ns    2.14V      3.055V     946.6mV
1.966ns   1.306V     2.721V     670.7mV
2.236ns   811.1mV    2.033V     639.7mV
2.682ns   693.3mV    1.067V     629.3mV
3.134ns   671.2mV    755.9mV    622.6mV
12ns      657.5mV    684.8mV    619.3mV
[Rising Waveform]
V_fixture = 0V
V_fixture_min = 0V
V_fixture_max = 0V
R_fixture = 200Ohm
C_fixture = 0F
|   Time   V(typ)   V(min)   V(max)
0s        12.53uV    95.65uV    7.17uV
817ps     267.3uV    130.4uV    -62.77mV
930.2ps   -34.84mV   135.2uV    348.2mV
1.148ns   13mV       144.5uV    1.615V
1.368ns   850.8mV    -58.23mV   2.752V
1.628ns   1.963V     65.02mV    3.062V
1.862ns   2.556V     753mV      3.088V
2.216ns   2.684V     1.907V     3.095V
2.654ns   2.703V     2.274V     3.1V
12ns      2.717V     2.333V     3.105V
[Rising Waveform]
V_fixture = 3.3V
V_fixture_min = 2.97V
V_fixture_max = 3.63V
R_fixture = 200Ohm
C_fixture = 0F
|   Time   V(typ)   V(min)   V(max)
0s        657.5mV    684.8mV    619.3mV
732.6ps   654.5mV    682.3mV    664.3mV
978.5ps   711.9mV    681.5mV    1.985V
1.171ns   1.414V     680.8mV    3.238V
1.265ns   1.856V     680.5mV    3.493V
1.418ns   2.653V     796.3mV    3.6V
1.601ns   3.173V     1.374V     3.62V
1.95ns    3.287V     2.634V     3.627V
2.292ns   3.296V     2.935V     3.629V
12ns      3.3V       2.97V      3.63V
[Falling Waveform]
|Gnd
V_fixture = 0V
V_fixture_min = 0V
V_fixture_max = 0V
R_fixture = 200Ohm
C_fixture = 0F
|   Time   V(typ)   V(min)   V(max)
0s        2.718V     2.335V     3.106V
649.8ps   2.735V     2.334V     3.033V
874.4ps   2.576V     2.351V     2.34V
1.201ns   1.704V     2.186V     889.3mV
1.471ns   837.6mV    1.566V     206.6mV
1.689ns   412.9mV    1.109V     39.91mV
1.914ns   99.96mV    680.5mV    17.17mV
2.222ns   24.74mV    253mV      8.781mV
2.631ns   8.886mV    31.66mV    4.129mV
12ns      12.66uV    95.76uV    7.329uV
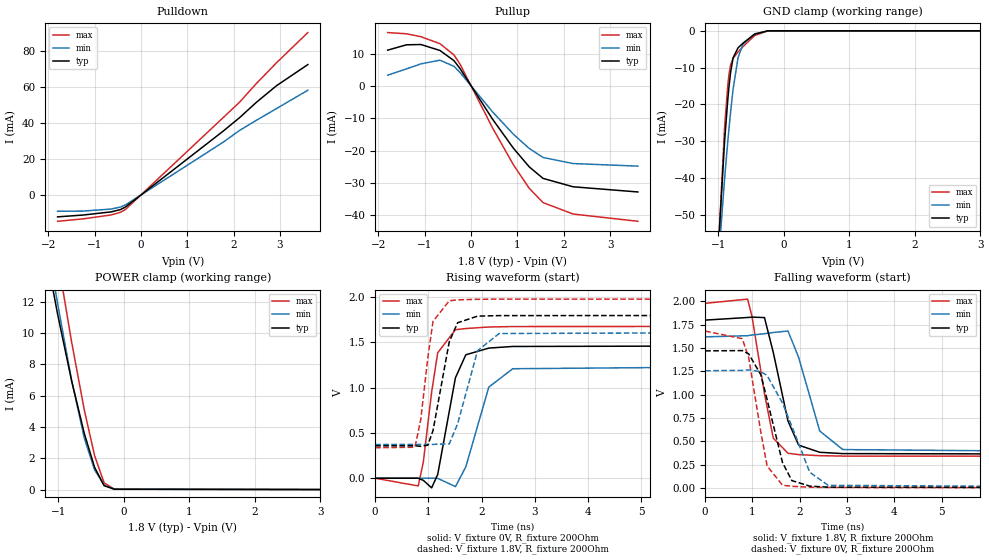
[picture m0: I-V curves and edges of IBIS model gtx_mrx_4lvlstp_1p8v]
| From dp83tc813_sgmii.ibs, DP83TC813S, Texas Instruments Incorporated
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| gtx_mrx_4lvlstp_1p8v
[Model]   gtx_mrx_4lvlstp_1p8v
Model_type   I/O
Polarity   Non-Inverting
Enable   Active-Low
Vinl = 0.63
Vinh = 1.17
Vmeas = 0.9
Vref = 0.9
Cref = 2pF
Rref = 100000
|   typ   min   max
C_comp   2.98pF   2.93pF   3.01pF
[Voltage Range]   1.8   1.62   1.98
[Temperature Range]   27   150   -40
[Pullup Reference]   1.8   1.62   1.98
[Pulldown Reference]   0   0   -0
[Power Clamp Reference]   1.8   1.62   1.98
[GND Clamp Reference]   0   0   0
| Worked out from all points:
|   slope of the pulldown table from 0 to 0.27 V, typ, clamps not added: 49.7 ohm
|   slope of the pullup table from 0 to 0.27 V, typ, clamps not added: 44.6 ohm
|   GND clamp passes 1 mA (typ) near -0.45 V on its own axis
|   POWER clamp passes 1 mA (typ) near -0.40 V on its own axis
|   falling waveform, V_fixture 1.8V, R_fixture 200Ohm: 20-80 % time 375ps typ, 420ps min, 317ps max; typ from 1.8 V to 0.358 V
|   rising waveform, V_fixture 0V, R_fixture 200Ohm: 20-80 % time 273ps typ, 367ps min, 222ps max; typ from 0 V to 1.47 V
|   rising waveform, V_fixture 1.8V, R_fixture 200Ohm: 20-80 % time 258ps typ, 338ps min, 199ps max; typ from 0.358 V to 1.8 V
|   falling waveform, V_fixture 0V, R_fixture 200Ohm: 20-80 % time 416ps typ, 594ps min, 328ps max; typ from 1.47 V to 0 V
[Pulldown]
|   Voltage   I(typ)   I(min)   I(max)
-1.8V     -12.09mA   -8.999mA   -14.55mA
-1.255V   -11.09mA   -8.889mA   -13.22mA
-644.4mV  -9.329mA   -7.759mA   -11.03mA
-444.6mV  -8.058mA   -6.661mA   -9.56mA
-336.6mV  -6.654mA   -5.485mA   -8.007mA
1.775V    35.51mA    29.36mA    43.01mA
2.126V    42.92mA    35.84mA    51.5mA
2.488V    51.4mA     41.45mA    61.84mA
2.925V    60.68mA    48mA       73.4mA
3.6V      72.38mA    58.15mA    90.14mA
[GND Clamp]
|   Voltage   I(typ)   I(min)   I(max)
-1.8V     -366.2mA   -316.6mA   -408.2mA
-1.017V   -64.47mA   -67.42mA   -66.03mA
-903.6mV  -30.04mA   -40.21mA   -26.27mA
-855mV    -18.73mA   -30.12mA   -14.83mA
-838.8mV  -15.59mA   -26.98mA   -12.19mA
-811.8mV  -11.25mA   -22.04mA   -9.286mA
-774mV    -7.349mA   -15.87mA   -7.46mA
-698.4mV  -4.626mA   -7.305mA   -5.752mA
-622.8mV  -3.348mA   -3.638mA   -4.29mA
-444.6mV  -906.4uA   -822.3uA   -1.276mA
-244.8mV  -10.16uA   -25.18uA   -9.891uA
3.6V      0A         0A         0A
[Pullup]
|   Voltage   I(typ)   I(min)   I(max)
-1.8V     11.14mA    3.383mA    16.59mA
-1.395V   12.79mA    5.324mA    16.21mA
-1.082V   12.89mA    6.89mA     15.32mA
-671.4mV  11.04mA    8.029mA    13.15mA
-369mV    7.896mA    6.134mA    9.668mA
-239.4mV  5.458mA    4.248mA    6.843mA
462.6mV   -10.22mA   -7.966mA   -12.92mA
916.2mV   -19.3mA    -14.95mA   -24.44mA
1.256V    -25.03mA   -19.33mA   -31.68mA
1.553V    -28.6mA    -22.12mA   -36.1mA
2.201V    -31.2mA    -24mA      -39.64mA
3.6V      -32.81mA   -24.8mA    -41.9mA
[POWER Clamp]
|   Voltage   I(typ)   I(min)   I(max)
-1.8V     34.56mA    35.03mA    39.32mA
-1.697V   30.06mA    31.02mA    34.5mA
-1.584V   26.07mA    27.06mA    30.73mA
-1.406V   20.89mA    21.89mA    25.58mA
-1.163V   14.66mA    15.67mA    18.87mA
-1.012V   11.28mA    11.97mA    14.86mA
-795.6mV  6.961mA    7.009mA    9.452mA
-601.2mV  3.583mA    3.285mA    5.08mA
-444.6mV  1.424mA    1.262mA    2.174mA
-298.8mV  249.8uA    284.7uA    427.4uA
-142.2mV  23.02uA    28.73uA    31.52uA
3.6V      0A         0A         0A
[Ramp]
R_load = 200
|   typ   min   max
dV/dt_r   0.881006/2.71674e-10   0.753071/3.65402e-10   1.00828/2.19622e-10
dV/dt_f   0.864657/3.71927e-10   0.747958/4.18666e-10   0.985034/3.1624e-10
[Falling Waveform]
V_fixture = 1.8V
V_fixture_min = 1.62V
V_fixture_max = 1.98V
R_fixture = 200Ohm
C_fixture = 0F
|   Time   V(typ)   V(min)   V(max)
0s        1.799V     1.619V     1.979V
896.2ps   1.827V     1.632V     2.024V
988.5ps   1.831V     1.639V     1.842V
1.253ns   1.826V     1.653V     1.01V
1.439ns   1.453V     1.666V     533mV
1.75ns    716.8mV    1.682V     371.3mV
1.975ns   458mV      1.398V     356.5mV
2.421ns   381.4mV    609.6mV    345.2mV
2.908ns   367.3mV    410.6mV    340.8mV
12ns      358.2mV    372.8mV    337.5mV
[Rising Waveform]
V_fixture = 0V
V_fixture_min = 0V
V_fixture_max = 0V
R_fixture = 200Ohm
C_fixture = 0F
|   Time   V(typ)   V(min)   V(max)
0s        30.96uV    129.1uV    12.45uV
809.7ps   6.466uV    303.5uV    -84.95mV
905.4ps   -23.05mV   324.1uV    177.2mV
1.062ns   -106.3mV   357.9uV    952.8mV
1.176ns   41.65mV    -793.4uV   1.386V
1.509ns   1.11V      -92.55mV   1.641V
1.704ns   1.364V     125.7mV    1.654V
2.136ns   1.438V     1.007V     1.671V
2.586ns   1.456V     1.21V      1.676V
12ns      1.468V     1.255V     1.68V
[Rising Waveform]
V_fixture = 1.8V
V_fixture_min = 1.62V
V_fixture_max = 1.98V
R_fixture = 200Ohm
C_fixture = 0F
|   Time   V(typ)   V(min)   V(max)
0s        358.2mV    372.8mV    337.5mV
747.9ps   359.1mV    373.4mV    342.5mV
856.8ps   352.6mV    373.5mV    644.7mV
990.3ps   365mV      373.6mV    1.331V
1.088ns   527mV      373.7mV    1.733V
1.393ns   1.508V     380.4mV    1.961V
1.55ns    1.718V     600.9mV    1.971V
1.925ns   1.791V     1.409V     1.977V
2.329ns   1.797V     1.599V     1.979V
12ns      1.799V     1.619V     1.979V
[Falling Waveform]
|Gnd
V_fixture = 0V
V_fixture_min = 0V
V_fixture_max = 0V
R_fixture = 200Ohm
C_fixture = 0F
|   Time   V(typ)   V(min)   V(max)
0s        1.469V     1.256V     1.681V
784.2ps   1.472V     1.26V      1.6V
919.4ps   1.437V     1.265V     1.397V
1.176ns   1.213V     1.246V     597.3mV
1.309ns   946.1mV    1.205V     234.5mV
1.634ns   271.4mV    908.9mV    28.45mV
1.832ns   77.9mV     660.2mV    16.73mV
2.21ns    18.43mV    167.4mV    7.165mV
2.599ns   7.542mV    27.26mV    4.146mV
12ns      30.58uV    128.5uV    12.24uV
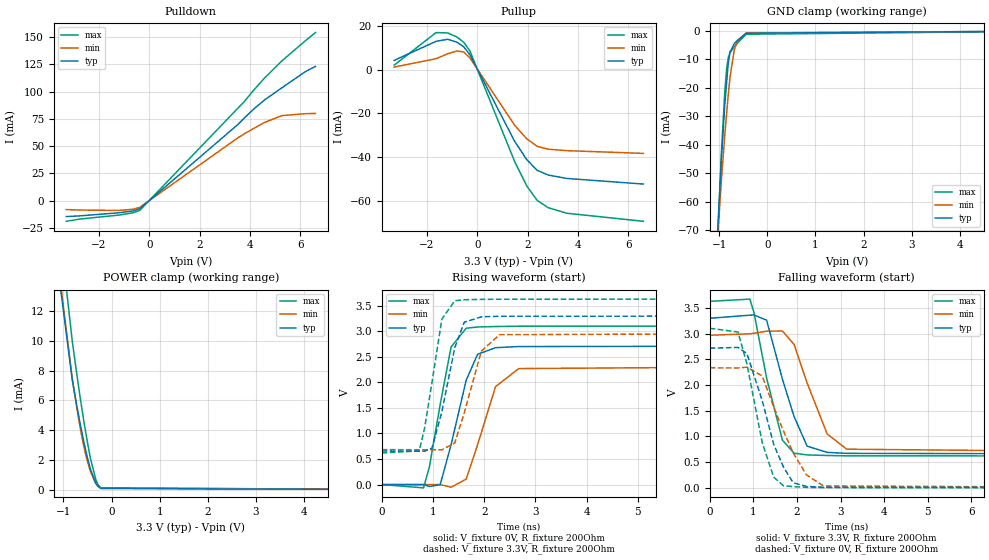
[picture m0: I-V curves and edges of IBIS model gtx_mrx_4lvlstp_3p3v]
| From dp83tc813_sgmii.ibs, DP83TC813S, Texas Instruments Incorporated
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| gtx_mrx_4lvlstp_3p3v
[Model]   gtx_mrx_4lvlstp_3p3v
Model_type   I/O
Polarity   Non-Inverting
Enable   Active-Low
Vinl = 0.8
Vinh = 2
Vmeas = 1.65
Vref = 1.65
Cref = 2pF
Rref = 100000
|   typ   min   max
C_comp   2.96pF   2.91pF   2.99pF
[Voltage Range]   3.3   2.97   3.63
[Temperature Range]   27   150   -40
[Pullup Reference]   3.3   2.97   3.63
[Pulldown Reference]   0   0   0
[Power Clamp Reference]   3.3   2.97   3.63
[GND Clamp Reference]   0   0   0
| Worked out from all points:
|   slope of the pulldown table from 0 to 0.495 V, typ, clamps not added: 49.7 ohm
|   slope of the pullup table from 0 to 0.495 V, typ, clamps not added: 42.6 ohm
|   GND clamp passes 1 mA (typ) near -0.45 V on its own axis
|   POWER clamp passes 1 mA (typ) near -0.40 V on its own axis
|   falling waveform, V_fixture 3.3V, R_fixture 200Ohm: 20-80 % time 545ps typ, 594ps min, 468ps max; typ from 3.3 V to 0.657 V
|   rising waveform, V_fixture 0V, R_fixture 200Ohm: 20-80 % time 385ps typ, 420ps min, 325ps max; typ from 0 V to 2.72 V
|   rising waveform, V_fixture 3.3V, R_fixture 200Ohm: 20-80 % time 328ps typ, 375ps min, 275ps max; typ from 0.657 V to 3.3 V
|   falling waveform, V_fixture 0V, R_fixture 200Ohm: 20-80 % time 589ps typ, 716ps min, 471ps max; typ from 2.72 V to 0 V
[Pulldown]
|   Voltage   I(typ)   I(min)   I(max)
-3.3V     -14.49mA   -8.058mA   -18.8mA
-2.775V   -13.84mA   -8.495mA   -16.78mA
-1.211V   -11mA      -8.856mA   -13.1mA
-636.9mV  -9.29mA    -7.726mA   -10.99mA
-379.5mV  -7.291mA   -6.009mA   -8.741mA
3.521V    69.9mA     57.68mA    84.83mA
3.769V    75.65mA    61.21mA    90.72mA
4.125V    83.52mA    65.97mA    100.7mA
4.561V    92.04mA    71.53mA    112mA
5.263V    103.4mA    77.95mA    128mA
6.204V    118.3mA    79.76mA    146.6mA
6.6V      123mA      79.94mA    154mA
[GND Clamp]
|   Voltage   I(typ)   I(min)   I(max)
-3.3V     -975.6mA   -833.8mA   -1.088A
-1.082V   -87.42mA   -85.76mA   -92.38mA
-1.053V   -76.87mA   -77.4mA    -80.24mA
-953.7mV  -44.39mA   -51.98mA   -42.32mA
-884.4mV  -25.71mA   -36.46mA   -21.17mA
-844.8mV  -17.71mA   -28.63mA   -13.09mA
-815.1mV  -11.71mA   -22.76mA   -9.548mA
-775.5mV  -7.456mA   -16.2mA    -7.571mA
-686.4mV  -4.401mA   -6.504mA   -5.581mA
-617.1mV  -3.26mA    -3.482mA   -4.186mA
-438.9mV  -845.7uA   -772.4uA   -1.203mA
6.6V      0A         0A         0A
[Pullup]
|   Voltage   I(typ)   I(min)   I(max)
-3.3V     4.209mA    1.152mA    2.057mA
-1.637V   12.93mA    4.985mA    16.93mA
-1.171V   13.87mA    7.252mA    16.75mA
-815.1mV  12.56mA    8.507mA    14.96mA
-537.9mV  10.43mA    8.083mA    12.52mA
-290.4mV  6.774mA    5.309mA    8.451mA
1.492V    -32.92mA   -25.55mA   -42.2mA
1.967V    -41.16mA   -31.63mA   -53.19mA
2.383V    -46.05mA   -35.1mA    -59.82mA
2.818V    -48.19mA   -36.38mA   -63.11mA
3.561V    -49.75mA   -37.04mA   -65.65mA
6.6V      -52.31mA   -38.3mA    -69.33mA
[POWER Clamp]
|   Voltage   I(typ)   I(min)   I(max)
-3.3V     265.1mA    186.4mA    350mA
-1.657V   28.53mA    29.54mA    34.23mA
-815.1mV  7.344mA    7.443mA    9.937mA
-726mV    5.701mA    5.57mA     7.848mA
-646.8mV  4.335mA    4.068mA    6.071mA
-577.5mV  3.23mA     2.925mA    4.63mA
-508.2mV  2.233mA    1.972mA    3.307mA
-438.9mV  1.375mA    1.218mA    2.106mA
-330mV    440.2uA    443.7uA    710.7uA
-280.5mV  210uA      241.9uA    330.1uA
-221.1mV  74.04uA    100.7uA    110.8uA
6.6V      0A         0A         0A
[Ramp]
R_load = 200
|   typ   min   max
dV/dt_r   1.62935/3.82797e-10   1.3996/4.17842e-10   1.86236/3.24007e-10
dV/dt_f   1.5849/5.45491e-10   1.37061/5.9374e-10   1.8057/4.67734e-10
[Falling Waveform]
V_fixture = 3.3V
V_fixture_min = 2.97V
V_fixture_max = 3.63V
R_fixture = 200Ohm
C_fixture = 0F
|   Time   V(typ)   V(min)   V(max)
0s        3.299V     2.969V     3.629V
922.5ps   3.36V      2.997V     3.672V
1.017ns   3.364V     3.009V     3.406V
1.306ns   3.262V     3.048V     2.136V
1.668ns   2.116V     3.052V     927.8mV
1.936ns   1.386V     2.79V      674mV
2.235ns   811.4mV    2.038V     640.8mV
2.694ns   690.7mV    1.049V     629.9mV
3.142ns   671.5mV    752.1mV    623.3mV
12ns      657.3mV    684.6mV    619.1mV
[Rising Waveform]
V_fixture = 0V
V_fixture_min = 0V
V_fixture_max = 0V
R_fixture = 200Ohm
C_fixture = 0F
|   Time   V(typ)   V(min)   V(max)
0s        126.9uV    185.8uV    122.2uV
816.3ps   654.3uV    592.5uV    -63.76mV
930.9ps   -35.69mV   649.5uV    348.5mV
1.141ns   -3.37mV    754.1uV    1.568V
1.354ns   780.5mV    -51.83mV   2.693V
1.649ns   2.043V     107.1mV    3.06V
1.872ns   2.55V      781.3mV    3.084V
2.222ns   2.679V     1.917V     3.093V
2.676ns   2.701V     2.27V      3.099V
12ns      2.716V     2.333V     3.104V
[Rising Waveform]
V_fixture = 3.3V
V_fixture_min = 2.97V
V_fixture_max = 3.63V
R_fixture = 200Ohm
C_fixture = 0F
|   Time   V(typ)   V(min)   V(max)
0s        657.3mV    684.6mV    619.1mV
731.7ps   654mV      681.8mV    660.7mV
835.3ps   653.6mV    681.4mV    1.095V
978.8ps   710.8mV    680.8mV    1.987V
1.174ns   1.423V     680mV      3.239V
1.426ns   2.679V     814.8mV    3.597V
1.611ns   3.176V     1.404V     3.617V
1.945ns   3.283V     2.613V     3.624V
2.302ns   3.294V     2.933V     3.627V
12ns      3.299V     2.969V     3.629V
[Falling Waveform]
|Gnd
V_fixture = 0V
V_fixture_min = 0V
V_fixture_max = 0V
R_fixture = 200Ohm
C_fixture = 0F
|   Time   V(typ)   V(min)   V(max)
0s        2.717V     2.335V     3.105V
649.8ps   2.733V     2.333V     3.032V
854.5ps   2.612V     2.348V     2.41V
1.205ns   1.697V     2.177V     880.9mV
1.469ns   843.9mV    1.569V     208.4mV
1.688ns   413mV      1.115V     42.42mV
1.915ns   99.06mV    681.4mV    23.65mV
2.217ns   28.51mV    254.8mV    9.945mV
2.607ns   10.81mV    37.12mV    5.039mV
12ns      127uV      187.9uV    121.7uV
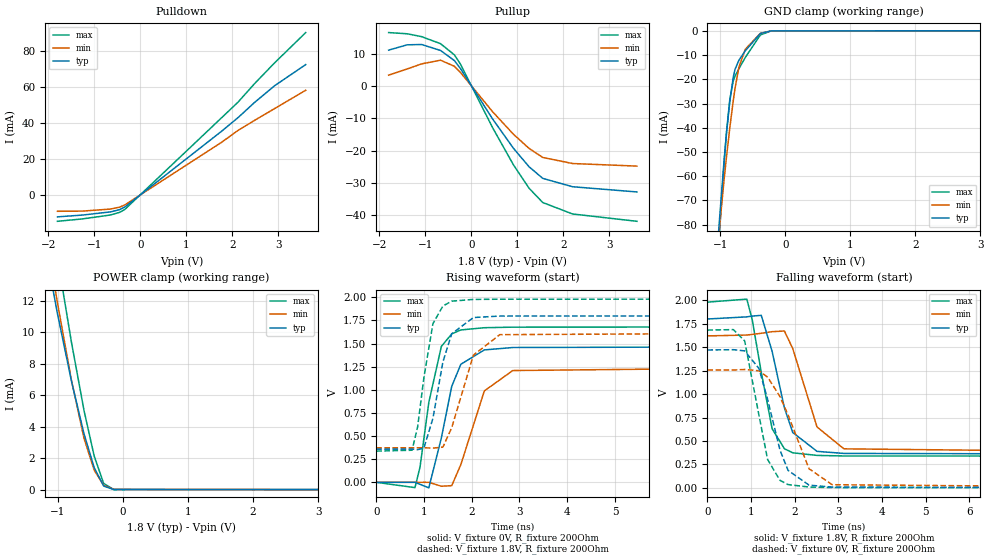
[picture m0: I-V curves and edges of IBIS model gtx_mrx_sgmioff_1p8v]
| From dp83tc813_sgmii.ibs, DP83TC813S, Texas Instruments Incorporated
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| gtx_mrx_sgmii_off_1p8v
[Model]   gtx_mrx_sgmioff_1p8v
Model_type   I/O
Polarity   Non-Inverting
Enable   Active-Low
Vinl = 0.63
Vinh = 1.17
Vmeas = 0.9
Vref = 0.9
Cref = 2pF
Rref = 100000
|   typ   min   max
C_comp   4.18pF   4pF   4.27pF
[Voltage Range]   1.8   1.62   1.98
[Temperature Range]   27   150   -40
[Pullup Reference]   1.8   1.62   1.98
[Pulldown Reference]   -0   -0   0
[Power Clamp Reference]   1.8   1.62   1.98
[GND Clamp Reference]   0   0   0
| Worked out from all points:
|   slope of the pulldown table from 0 to 0.27 V, typ, clamps not added: 49.7 ohm
|   slope of the pullup table from 0 to 0.27 V, typ, clamps not added: 44.6 ohm
|   GND clamp passes 1 mA (typ) near -0.38 V on its own axis
|   POWER clamp passes 1 mA (typ) near -0.41 V on its own axis
|   falling waveform, V_fixture 1.8V, R_fixture 200Ohm: 20-80 % time 443ps typ, 510ps min, 375ps max; typ from 1.8 V to 0.358 V
|   rising waveform, V_fixture 0V, R_fixture 200Ohm: 20-80 % time 372ps typ, 477ps min, 309ps max; typ from 0 V to 1.47 V
|   rising waveform, V_fixture 1.8V, R_fixture 200Ohm: 20-80 % time 335ps typ, 429ps min, 268ps max; typ from 0.358 V to 1.8 V
|   falling waveform, V_fixture 0V, R_fixture 200Ohm: 20-80 % time 484ps typ, 653ps min, 391ps max; typ from 1.47 V to 0 V
[Pulldown]
|   Voltage   I(typ)   I(min)   I(max)
-1.8V     -12.09mA   -8.999mA   -14.55mA
-1.255V   -11.09mA   -8.889mA   -13.22mA
-644.4mV  -9.329mA   -7.759mA   -11.03mA
-444.6mV  -8.058mA   -6.661mA   -9.56mA
-336.6mV  -6.654mA   -5.485mA   -8.007mA
1.775V    35.51mA    29.36mA    43.01mA
2.126V    42.92mA    35.84mA    51.5mA
2.488V    51.4mA     41.45mA    61.84mA
2.925V    60.68mA    48mA       73.4mA
3.6V      72.38mA    58.15mA    90.14mA
[GND Clamp]
|   Voltage   I(typ)   I(min)   I(max)
-1.8V     -404.5mA   -355.7mA   -450mA
-1.022V   -80.8mA    -83.52mA   -86.5mA
-941.4mV  -52.96mA   -61.02mA   -54.11mA
-903.6mV  -41.61mA   -51.46mA   -41.21mA
-855mV    -29.13mA   -40.03mA   -28.37mA
-801mV    -19mA      -28.64mA   -20.57mA
-774mV    -15.85mA   -23.64mA   -18.69mA
-714.6mV  -12.12mA   -14.96mA   -15.62mA
-617.4mV  -8.27mA    -7.637mA   -11.03mA
-385.2mV  -1.108mA   -1.043mA   -1.72mA
-217.8mV  -10.59uA   -38.42uA   -7.495uA
3.6V      0A         0A         0A
[Pullup]
|   Voltage   I(typ)   I(min)   I(max)
-1.8V     11.14mA    3.383mA    16.59mA
-1.395V   12.79mA    5.324mA    16.21mA
-1.082V   12.89mA    6.89mA     15.32mA
-671.4mV  11.04mA    8.029mA    13.15mA
-369mV    7.896mA    6.134mA    9.668mA
-239.4mV  5.458mA    4.248mA    6.843mA
462.6mV   -10.22mA   -7.966mA   -12.92mA
916.2mV   -19.3mA    -14.95mA   -24.44mA
1.256V    -25.03mA   -19.33mA   -31.68mA
1.553V    -28.6mA    -22.12mA   -36.1mA
2.201V    -31.2mA    -24mA      -39.64mA
3.6V      -32.81mA   -24.8mA    -41.91mA
[POWER Clamp]
|   Voltage   I(typ)   I(min)   I(max)
-1.8V     34.46mA    34.96mA    39.2mA
-1.697V   29.97mA    30.95mA    34.38mA
-1.584V   25.99mA    26.99mA    30.62mA
-1.406V   20.81mA    21.83mA    25.48mA
-1.157V   14.47mA    15.49mA    18.64mA
-1.012V   11.22mA    11.92mA    14.78mA
-795.6mV  6.913mA    6.972mA    9.388mA
-601.2mV  3.544mA    3.256mA    5.027mA
-444.6mV  1.393mA    1.238mA    2.131mA
-298.8mV  225.6uA    266.8uA    392.5uA
-142.2mV  3.419uA    14.8uA     2.982uA
3.6V      0A         0A         0A
[Ramp]
R_load = 200
|   typ   min   max
dV/dt_r   0.881315/3.70889e-10   0.753326/4.71828e-10   1.00869/3.0923e-10
dV/dt_f   0.864969/4.4271e-10   0.748231/5.08132e-10   0.985413/3.74546e-10
[Falling Waveform]
V_fixture = 1.8V
V_fixture_min = 1.62V
V_fixture_max = 1.98V
R_fixture = 200Ohm
C_fixture = 0F
|   Time   V(typ)   V(min)   V(max)
0s        1.8V       1.62V      1.98V
903.7ps   1.823V     1.629V     2.012V
1.027ns   1.831V     1.636V     1.794V
1.235ns   1.839V     1.648V     1.231V
1.484ns   1.454V     1.665V     629.8mV
1.765ns   853.1mV    1.672V     417.2mV
1.955ns   590.5mV    1.486V     373.7mV
2.512ns   389.2mV    649.3mV    346mV
3.128ns   367.1mV    416mV      339.9mV
12ns      358.4mV    372.9mV    337.6mV
[Rising Waveform]
V_fixture = 0V
V_fixture_min = 0V
V_fixture_max = 0V
R_fixture = 200Ohm
C_fixture = 0F
|   Time   V(typ)   V(min)   V(max)
0s        11.82uV    92.57uV    6.53uV
811.2ps   198.9uV    98.21uV    -57.44mV
916.6ps   -21.58mV   98.94uV    163mV
1.101ns   -59.96mV   100.2uV    862.8mV
1.364ns   479.9mV    -42.42mV   1.469V
1.581ns   1.037V     -35.89mV   1.604V
1.772ns   1.276V     191.4mV    1.647V
2.264ns   1.431V     988mV      1.671V
2.859ns   1.457V     1.208V     1.677V
12ns      1.469V     1.256V     1.681V
[Rising Waveform]
V_fixture = 1.8V
V_fixture_min = 1.62V
V_fixture_max = 1.98V
R_fixture = 200Ohm
C_fixture = 0F
|   Time   V(typ)   V(min)   V(max)
0s        358.4mV    372.9mV    337.6mV
751.2ps   358.9mV    373.3mV    346.7mV
867.7ps   352.6mV    373.3mV    600.8mV
998.4ps   370.7mV    373.4mV    1.133V
1.188ns   692.6mV    370mV      1.716V
1.396ns   1.301V     380.3mV    1.905V
1.581ns   1.606V     590.3mV    1.958V
2.035ns   1.781V     1.375V     1.977V
2.588ns   1.797V     1.596V     1.979V
12ns      1.8V       1.62V      1.98V
[Falling Waveform]
|Gnd
V_fixture = 0V
V_fixture_min = 0V
V_fixture_max = 0V
R_fixture = 200Ohm
C_fixture = 0F
|   Time   V(typ)   V(min)   V(max)
0s        1.47V      1.257V     1.682V
595.1ps   1.473V     1.256V     1.687V
854.8ps   1.46V      1.262V     1.566V
1.183ns   1.272V     1.248V     771.4mV
1.38ns    942.3mV    1.181V     302.4mV
1.663ns   403.5mV    972.8mV    80.15mV
1.849ns   186.2mV    776.7mV    35.13mV
2.33ns    29.05mV    203.4mV    8.617mV
2.859ns   8.165mV    33.53mV    3.143mV
12ns      11.89uV    92.76uV    6.613uV
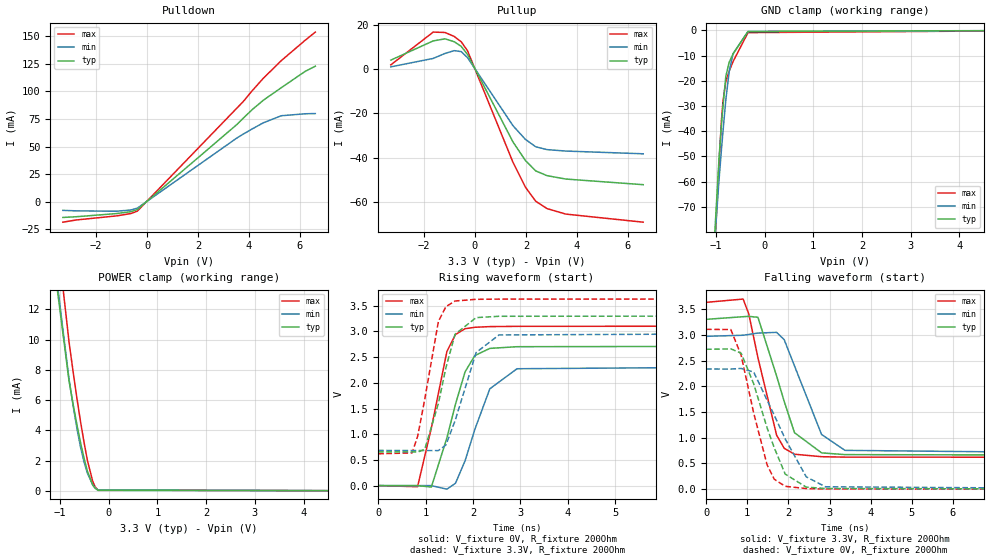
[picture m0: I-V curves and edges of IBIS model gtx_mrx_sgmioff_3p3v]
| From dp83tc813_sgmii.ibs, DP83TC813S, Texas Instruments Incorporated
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| gtx_mrx_sgmii_off_3p3v
[Model]   gtx_mrx_sgmioff_3p3v
Model_type   I/O
Polarity   Non-Inverting
Enable   Active-Low
Vinl = 0.8
Vinh = 2
Vmeas = 1.65
Vref = 1.65
Cref = 2pF
Rref = 100000
|   typ   min   max
C_comp   4.07pF   3.89pF   4.16pF
[Voltage Range]   3.3   2.97   3.63
[Temperature Range]   27   150   -40
[Pullup Reference]   3.3   2.97   3.63
[Pulldown Reference]   -0   -0   0
[Power Clamp Reference]   3.3   2.97   3.63
[GND Clamp Reference]   0   0   0
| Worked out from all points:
|   slope of the pulldown table from 0 to 0.495 V, typ, clamps not added: 49.7 ohm
|   slope of the pullup table from 0 to 0.495 V, typ, clamps not added: 42.6 ohm
|   GND clamp passes 1 mA (typ) near -0.37 V on its own axis
|   POWER clamp passes 1 mA (typ) near -0.40 V on its own axis
|   falling waveform, V_fixture 3.3V, R_fixture 200Ohm: 20-80 % time 595ps typ, 658ps min, 509ps max; typ from 3.3 V to 0.658 V
|   rising waveform, V_fixture 0V, R_fixture 200Ohm: 20-80 % time 473ps typ, 518ps min, 397ps max; typ from 0 V to 2.72 V
|   rising waveform, V_fixture 3.3V, R_fixture 200Ohm: 20-80 % time 393ps typ, 450ps min, 332ps max; typ from 0.658 V to 3.3 V
|   falling waveform, V_fixture 0V, R_fixture 200Ohm: 20-80 % time 681ps typ, 846ps min, 534ps max; typ from 2.72 V to 0 V
[Pulldown]
|   Voltage   I(typ)   I(min)   I(max)
-3.3V     -14.49mA   -8.058mA   -18.8mA
-2.775V   -13.84mA   -8.495mA   -16.78mA
-1.211V   -11mA      -8.856mA   -13.1mA
-636.9mV  -9.29mA    -7.726mA   -10.99mA
-379.5mV  -7.291mA   -6.009mA   -8.741mA
3.521V    69.9mA     57.68mA    84.83mA
3.769V    75.65mA    61.21mA    90.72mA
4.125V    83.52mA    65.97mA    100.7mA
4.561V    92.04mA    71.53mA    112mA
5.263V    103.4mA    77.95mA    128mA
6.204V    118.3mA    79.76mA    146.6mA
6.6V      123mA      79.94mA    154mA
[GND Clamp]
|   Voltage   I(typ)   I(min)   I(max)
-3.3V     -1.068A    -919.5mA   -1.194A
-1.063V   -95.77mA   -95.65mA   -103.8mA
-1.053V   -92.03mA   -92.61mA   -99.49mA
-1.013V   -77.42mA   -80.8mA    -82.59mA
-933.9mV  -50.61mA   -59.08mA   -52.39mA
-884.4mV  -37.2mA    -47.13mA   -35.56mA
-854.7mV  -30.33mA   -40.41mA   -28.31mA
-795.3mV  -18.22mA   -27.54mA   -20.25mA
-726mV    -12.66mA   -16.34mA   -16.19mA
-646.8mV  -9.375mA   -9.225mA   -12.4mA
-339.9mV  -438.3uA   -510.9uA   -906.4uA
6.6V      0A         0A         0A
[Pullup]
|   Voltage   I(typ)   I(min)   I(max)
-3.3V     4.209mA    1.152mA    2.057mA
-1.637V   12.93mA    4.985mA    16.93mA
-1.171V   13.87mA    7.252mA    16.75mA
-815.1mV  12.56mA    8.507mA    14.96mA
-537.9mV  10.43mA    8.083mA    12.52mA
-290.4mV  6.774mA    5.309mA    8.451mA
1.492V    -32.92mA   -25.55mA   -42.17mA
1.977V    -41.31mA   -31.73mA   -53.39mA
2.383V    -46.05mA   -35.1mA    -59.82mA
2.828V    -48.22mA   -36.4mA    -63.16mA
3.561V    -49.75mA   -37.05mA   -65.65mA
6.6V      -52.31mA   -38.3mA    -69.33mA
[POWER Clamp]
|   Voltage   I(typ)   I(min)   I(max)
-3.3V     264.9mA    186.2mA    349.8mA
-1.657V   28.42mA    29.46mA    34.09mA
-815.1mV  7.28mA     7.395mA    9.85mA
-726mV    5.642mA    5.525mA    7.766mA
-646.8mV  4.28mA     4.026mA    5.994mA
-577.5mV  3.178mA    2.886mA    4.557mA
-508.2mV  2.184mA    1.935mA    3.238mA
-438.9mV  1.329mA    1.184mA    2.041mA
-330mV    399.7uA    414.1uA    652.1uA
-280.5mV  171.6uA    214.1uA    274.2uA
-221.1mV  37.72uA    74.67uA    57.75uA
6.6V      0A         0A         0A
[Ramp]
R_load = 200
|   typ   min   max
dV/dt_r   1.62993/4.7049e-10   1.39997/5.15825e-10   1.86313/3.94164e-10
dV/dt_f   1.58547/5.93233e-10   1.37107/6.53325e-10   1.8064/5.09563e-10
[Falling Waveform]
V_fixture = 3.3V
V_fixture_min = 2.97V
V_fixture_max = 3.63V
R_fixture = 200Ohm
C_fixture = 0F
|   Time   V(typ)   V(min)   V(max)
0s        3.3V       2.97V      3.63V
899.7ps   3.351V     2.991V     3.694V
1.036ns   3.358V     3.007V     3.41V
1.26ns    3.34V      3.033V     2.555V
1.714ns   2.199V     3.047V     1.049V
1.899ns   1.703V     2.904V     794.1mV
2.15ns    1.097V     2.393V     679.2mV
2.807ns   705.3mV    1.063V     630.9mV
3.375ns   671.3mV    754.2mV    622.6mV
12ns      657.5mV    684.8mV    619.3mV
[Rising Waveform]
V_fixture = 0V
V_fixture_min = 0V
V_fixture_max = 0V
R_fixture = 200Ohm
C_fixture = 0F
|   Time   V(typ)   V(min)   V(max)
0s        12.54uV    95.97uV    7.182uV
830.3ps   -486.6uV   -189.5uV   -21.6mV
1.121ns   -27.95mV   -289.5uV   1.12V
1.448ns   926.4mV    -69.43mV   2.608V
1.63ns    1.586V     46.29mV    2.941V
1.832ns   2.214V     483.1mV    3.053V
2.038ns   2.531V     1.095V     3.081V
2.354ns   2.67V      1.884V     3.094V
2.927ns   2.703V     2.274V     3.099V
12ns      2.717V     2.333V     3.105V
[Rising Waveform]
V_fixture = 3.3V
V_fixture_min = 2.97V
V_fixture_max = 3.63V
R_fixture = 200Ohm
C_fixture = 0F
|   Time   V(typ)   V(min)   V(max)
0s        657.5mV    684.8mV    619.3mV
714.6ps   655.2mV    682.9mV    635.9mV
834.4ps   654.8mV    682.6mV    970.3mV
979.8ps   701.8mV    682.2mV    1.671V
1.269ns   1.597V     681.5mV    3.193V
1.428ns   2.294V     789.3mV    3.483V
1.621ns   2.946V     1.262V     3.592V
2.065ns   3.269V     2.59V      3.625V
2.547ns   3.295V     2.932V     3.629V
12ns      3.3V       2.97V      3.63V
[Falling Waveform]
|Gnd
V_fixture = 0V
V_fixture_min = 0V
V_fixture_max = 0V
R_fixture = 200Ohm
C_fixture = 0F
|   Time   V(typ)   V(min)   V(max)
0s        2.718V     2.335V     3.106V
601.2ps   2.726V     2.334V     3.101V
851.4ps   2.643V     2.346V     2.603V
1.156ns   2.049V     2.277V     1.482V
1.483ns   1.191V     1.729V     471.9mV
1.657ns   803.3mV    1.436V     193mV
1.923ns   292.7mV    976.5mV    55.36mV
2.434ns   40.32mV    240mV      11.89mV
2.9ns     12.32mV    46.56mV    3.513mV
12ns      12.67uV    96.29uV    7.339uV
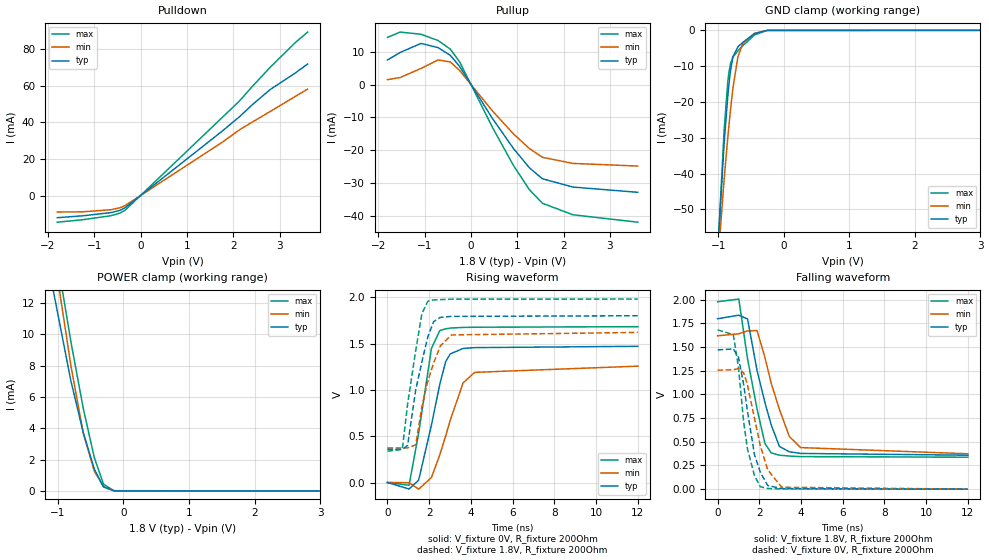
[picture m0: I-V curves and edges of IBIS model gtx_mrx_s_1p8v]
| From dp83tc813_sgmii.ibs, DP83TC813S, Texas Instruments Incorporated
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| gtx_mrx_s_1p8v
[Model]   gtx_mrx_s_1p8v
Model_type   I/O
Polarity   Non-Inverting
Enable   Active-Low
Vinl = 0.63
Vinh = 1.17
Vmeas = 0.9
Vref = 0.9
Cref = 2pF
Rref = 100000
|   typ   min   max
C_comp   2.78pF   2.74pF   2.80pF
[Voltage Range]   1.8   1.62   1.98
[Temperature Range]   27   150   -40
[Pullup Reference]   1.8   1.62   1.98
[Pulldown Reference]   0   0   0
[Power Clamp Reference]   1.8   1.62   1.98
[GND Clamp Reference]   0   0   0
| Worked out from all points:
|   slope of the pulldown table from 0 to 0.27 V, typ, clamps not added: 49.7 ohm
|   slope of the pullup table from 0 to 0.27 V, typ, clamps not added: 44.5 ohm
|   GND clamp passes 1 mA (typ) near -0.45 V on its own axis
|   POWER clamp passes 1 mA (typ) near -0.41 V on its own axis
|   falling waveform, V_fixture 1.8V, R_fixture 200Ohm: 20-80 % time 928ps typ, 1.02ns min, 791ps max; typ from 1.8 V to 0.359 V
|   rising waveform, V_fixture 0V, R_fixture 200Ohm: 20-80 % time 821ps typ, 1.03ns min, 671ps max; typ from 0 V to 1.47 V
|   rising waveform, V_fixture 1.8V, R_fixture 200Ohm: 20-80 % time 761ps typ, 829ps min, 643ps max; typ from 0.359 V to 1.8 V
|   falling waveform, V_fixture 0V, R_fixture 200Ohm: 20-80 % time 662ps typ, 796ps min, 545ps max; typ from 1.47 V to 0 V
[Pulldown]
|   Voltage   I(typ)   I(min)   I(max)
-1.8V     -12.09mA   -8.999mA   -14.55mA
-1.255V   -11.09mA   -8.889mA   -13.22mA
-644.4mV  -9.329mA   -7.759mA   -11.03mA
-444.6mV  -8.058mA   -6.661mA   -9.56mA
-336.6mV  -6.654mA   -5.485mA   -8.007mA
1.769V    35.4mA     29.27mA    42.88mA
2.126V    42.92mA    35.82mA    51.5mA
2.412V    49.68mA    40.17mA    59.68mA
2.795V    57.9mA     45.91mA    70.06mA
3.325V    66.72mA    53.96mA    83.27mA
3.6V      71.77mA    58.08mA    89.2mA
[GND Clamp]
|   Voltage   I(typ)   I(min)   I(max)
-1.8V     -366.8mA   -317.8mA   -407.9mA
-1.017V   -64.53mA   -67.73mA   -65.97mA
-909mV    -31.46mA   -41.59mA   -27.79mA
-855mV    -18.71mA   -30.27mA   -14.79mA
-838.8mV  -15.56mA   -27.12mA   -12.16mA
-811.8mV  -11.22mA   -22.15mA   -9.257mA
-774mV    -7.323mA   -15.95mA   -7.434mA
-698.4mV  -4.609mA   -7.329mA   -5.73mA
-622.8mV  -3.335mA   -3.629mA   -4.272mA
-444.6mV  -899.7uA   -816.3uA   -1.267mA
-250.2mV  -9.186uA   -26.26uA   -8.292uA
3.6V      0A         0A         0A
[Pullup]
|   Voltage   I(typ)   I(min)   I(max)
-1.8V     7.497mA    1.51mA     14.38mA
-1.525V   9.81mA     2.166mA    16mA
-1.076V   12.54mA    4.935mA    15.34mA
-709.2mV  11.28mA    7.503mA    13.44mA
-444.6mV  8.93mA     6.923mA    10.83mA
-244.8mV  5.572mA    4.337mA    6.984mA
462.6mV   -10.25mA   -7.972mA   -12.95mA
916.2mV   -19.42mA   -14.98mA   -24.57mA
1.262V    -25.32mA   -19.46mA   -32mA
1.543V    -28.68mA   -22.13mA   -36.13mA
2.201V    -31.2mA    -24mA      -39.64mA
3.6V      -32.8mA    -24.8mA    -41.9mA
[POWER Clamp]
|   Voltage   I(typ)   I(min)   I(max)
-1.8V     38.19mA    40.42mA    41.41mA
-1.719V   34.21mA    36.84mA    36.89mA
-1.687V   32.77mA    35.47mA    35.38mA
-1.568V   28.15mA    30.83mA    30.79mA
-1.33V    20.28mA    23.1mA     23.36mA
-1.071V   12.79mA    15.41mA    16.29mA
-801mV    7.003mA    7.97mA     9.5mA
-612mV    3.709mA    3.667mA    5.246mA
-444.6mV  1.392mA    1.256mA    2.129mA
-304.2mV  249.1uA    287.9uA    432.2uA
-142.2mV  3.423uA    14.68uA    2.99uA
3.6V      0A         0A         0A
[Ramp]
R_load = 200
|   typ   min   max
dV/dt_r   0.881765/8.16894e-10   0.753556/1.03347e-09   1.0092/6.68954e-10
dV/dt_f   0.864791/9.27112e-10   0.747608/1.02103e-09   0.985356/7.91823e-10
[Falling Waveform]
V_fixture = 1.8V
V_fixture_min = 1.62V
V_fixture_max = 1.98V
R_fixture = 200Ohm
C_fixture = 0F
|   Time   V(typ)   V(min)   V(max)
0s        1.8V       1.62V      1.98V
1.018ns   1.838V     1.641V     2.008V
1.436ns   1.798V     1.672V     1.377V
1.892ns   1.253V     1.675V     846.1mV
2.271ns   913.3mV    1.39V      482.1mV
2.571ns   678.1mV    1.119V     382.5mV
2.967ns   450.7mV    841.1mV    358.8mV
3.442ns   394.8mV    555.3mV    349.8mV
3.984ns   377.5mV    439.2mV    343.8mV
12ns      358.7mV    373.9mV    337.7mV
[Rising Waveform]
V_fixture = 0V
V_fixture_min = 0V
V_fixture_max = 0V
R_fixture = 200Ohm
C_fixture = 0F
|   Time   V(typ)   V(min)   V(max)
0s        24.53uV    130.5uV    11.23uV
1.035ns   -69.89mV   -1.085mV   -29.58mV
1.497ns   25.72mV    -71.72mV   533.4mV
2.11ns    621.1mV    54.6mV     1.448V
2.511ns   1.062V     299.4mV    1.64V
2.794ns   1.307V     504.5mV    1.659V
3.012ns   1.388V     673.2mV    1.667V
3.626ns   1.447V     1.075V     1.674V
4.181ns   1.456V     1.189V     1.676V
12ns      1.47V      1.256V     1.682V
[Rising Waveform]
V_fixture = 1.8V
V_fixture_min = 1.62V
V_fixture_max = 1.98V
R_fixture = 200Ohm
C_fixture = 0F
|   Time   V(typ)   V(min)   V(max)
0s        358.7mV    373.9mV    337.7mV
711.5ps   357.9mV    373.4mV    358mV
965.3ps   398.7mV    373.2mV    842.6mV
1.355ns   1V         406.5mV    1.426V
1.651ns   1.303V     819.7mV    1.822V
1.934ns   1.571V     1.093V     1.956V
2.214ns   1.737V     1.29V      1.971V
2.535ns   1.782V     1.474V     1.974V
3.071ns   1.793V     1.593V     1.979V
12ns      1.8V       1.62V      1.98V
[Falling Waveform]
|Gnd
V_fixture = 0V
V_fixture_min = 0V
V_fixture_max = 0V
R_fixture = 200Ohm
C_fixture = 0F
|   Time   V(typ)   V(min)   V(max)
0s        1.471V     1.257V     1.683V
755.1ps   1.481V     1.261V     1.631V
1.002ns   1.392V     1.273V     1.283V
1.249ns   1.106V     1.229V     710.8mV
1.429ns   828.2mV    1.105V     428.5mV
1.769ns   364.7mV    747.9mV    142.3mV
2.045ns   180.9mV    463.1mV    25.9mV
2.401ns   38.21mV    204.8mV    7.332mV
3.071ns   6.015mV    20.56mV    2.277mV
12ns      24.59uV    130.5uV    11.32uV
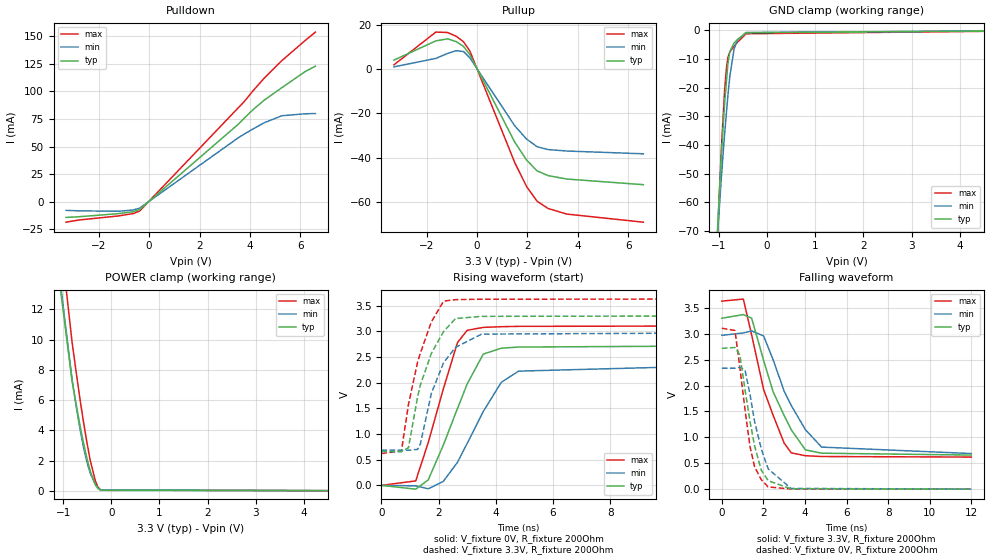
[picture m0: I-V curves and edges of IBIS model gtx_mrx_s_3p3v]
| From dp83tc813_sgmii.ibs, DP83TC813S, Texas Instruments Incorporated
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| gtx_mrx_s_3p3v
[Model]   gtx_mrx_s_3p3v
Model_type   I/O
Polarity   Non-Inverting
Enable   Active-Low
Vinl = 0.8
Vinh = 2
Vmeas = 1.65
Vref = 1.65
Cref = 2pF
Rref = 100000
|   typ   min   max
C_comp   2.75pF   2.71pF   2.76pF
[Voltage Range]   3.3   2.97   3.63
[Temperature Range]   27   150   -40
[Pullup Reference]   3.3   2.97   3.63
[Pulldown Reference]   0   0   0
[Power Clamp Reference]   3.3   2.97   3.63
[GND Clamp Reference]   0   0   0
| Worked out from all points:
|   slope of the pulldown table from 0 to 0.495 V, typ, clamps not added: 49.7 ohm
|   slope of the pullup table from 0 to 0.495 V, typ, clamps not added: 42.6 ohm
|   GND clamp passes 1 mA (typ) near -0.45 V on its own axis
|   POWER clamp passes 1 mA (typ) near -0.40 V on its own axis
|   falling waveform, V_fixture 3.3V, R_fixture 200Ohm: 20-80 % time 1.46ns typ, 1.57ns min, 1.25ns max; typ from 3.3 V to 0.658 V
|   rising waveform, V_fixture 0V, R_fixture 200Ohm: 20-80 % time 1.15ns typ, 1.32ns min, 949ps max; typ from 0 V to 2.72 V
|   rising waveform, V_fixture 3.3V, R_fixture 200Ohm: 20-80 % time 859ps typ, 853ps min, 801ps max; typ from 0.658 V to 3.3 V
|   falling waveform, V_fixture 0V, R_fixture 200Ohm: 20-80 % time 717ps typ, 813ps min, 623ps max; typ from 2.72 V to 0 V
[Pulldown]
|   Voltage   I(typ)   I(min)   I(max)
-3.3V     -14.49mA   -8.058mA   -18.8mA
-2.775V   -13.84mA   -8.495mA   -16.78mA
-1.211V   -11mA      -8.856mA   -13.1mA
-636.9mV  -9.29mA    -7.726mA   -10.99mA
-379.5mV  -7.291mA   -6.009mA   -8.741mA
3.521V    69.9mA     57.68mA    84.83mA
3.769V    75.65mA    61.21mA    90.72mA
4.125V    83.52mA    65.97mA    100.7mA
4.561V    92.04mA    71.53mA    112mA
5.263V    103.4mA    77.95mA    128mA
6.204V    118.3mA    79.76mA    146.6mA
6.6V      123mA      79.94mA    154mA
[GND Clamp]
|   Voltage   I(typ)   I(min)   I(max)
-3.3V     -975.7mA   -834.2mA   -1.088A
-1.082V   -87.39mA   -85.74mA   -92.35mA
-1.053V   -76.85mA   -77.39mA   -80.21mA
-953.7mV  -44.36mA   -51.95mA   -42.28mA
-884.4mV  -25.68mA   -36.44mA   -21.13mA
-844.8mV  -17.68mA   -28.61mA   -13.06mA
-815.1mV  -11.68mA   -22.74mA   -9.519mA
-775.5mV  -7.43mA    -16.18mA   -7.545mA
-686.4mV  -4.384mA   -6.481mA   -5.56mA
-617.1mV  -3.246mA   -3.463mA   -4.168mA
-438.9mV  -839.2uA   -766.6uA   -1.194mA
6.6V      0A         0A         0A
[Pullup]
|   Voltage   I(typ)   I(min)   I(max)
-3.3V     4.209mA    1.152mA    2.057mA
-1.637V   12.93mA    4.984mA    16.93mA
-1.171V   13.87mA    7.252mA    16.75mA
-815.1mV  12.56mA    8.507mA    14.96mA
-537.9mV  10.43mA    8.083mA    12.52mA
-290.4mV  6.774mA    5.308mA    8.451mA
1.492V    -32.92mA   -25.55mA   -42.2mA
1.967V    -41.16mA   -31.63mA   -53.19mA
2.383V    -46.05mA   -35.1mA    -59.82mA
2.818V    -48.19mA   -36.38mA   -63.11mA
3.561V    -49.75mA   -37.04mA   -65.65mA
6.6V      -52.31mA   -38.3mA    -69.33mA
[POWER Clamp]
|   Voltage   I(typ)   I(min)   I(max)
-3.3V     264.9mA    186.2mA    349.8mA
-1.657V   28.42mA    29.46mA    34.09mA
-815.1mV  7.28mA     7.394mA    9.85mA
-726mV    5.642mA    5.525mA    7.766mA
-646.8mV  4.28mA     4.026mA    5.994mA
-577.5mV  3.178mA    2.886mA    4.557mA
-508.2mV  2.184mA    1.935mA    3.238mA
-438.9mV  1.329mA    1.184mA    2.041mA
-330mV    399.7uA    414.1uA    652.2uA
-280.5mV  171.6uA    214uA      274.2uA
-221.1mV  37.73uA    74.54uA    57.76uA
6.6V      0A         0A         0A
[Ramp]
R_load = 200
|   typ   min   max
dV/dt_r   1.63046/1.14249e-09   1.39998/1.32314e-09   1.86377/9.46962e-10
dV/dt_f   1.58501/1.44736e-09   1.36949/1.5637e-09   1.80626/1.24979e-09
[Falling Waveform]
V_fixture = 3.3V
V_fixture_min = 2.97V
V_fixture_max = 3.63V
R_fixture = 200Ohm
C_fixture = 0F
|   Time   V(typ)   V(min)   V(max)
0s        3.3V       2.97V      3.63V
1.035ns   3.371V     3.016V     3.67V
1.434ns   3.301V     3.055V     2.978V
2.01ns    2.486V     2.958V     1.925V
2.466ns   1.881V     2.5V       1.428V
3.001ns   1.419V     1.89V      886.8mV
3.343ns   1.144V     1.613V     700.6mV
4.021ns   759.2mV    1.149V     645.6mV
4.799ns   694.4mV    812.1mV    630.3mV
12ns      658.3mV    687.4mV    619.6mV
[Rising Waveform]
V_fixture = 0V
V_fixture_min = 0V
V_fixture_max = 0V
R_fixture = 200Ohm
C_fixture = 0F
|   Time   V(typ)   V(min)   V(max)
0s        26.81uV    136.7uV    12.66uV
1.2ns     -73.78mV   -8.946mV   87.48mV
1.635ns   106mV      -66.28mV   831.5mV
2.159ns   776.2mV    74.46mV    1.867V
2.659ns   1.498V     449mV      2.782V
3.001ns   1.978V     820mV      3.022V
3.562ns   2.558V     1.44V      3.078V
4.193ns   2.673V     2.009V     3.092V
4.799ns   2.695V     2.226V     3.098V
12ns      2.717V     2.333V     3.106V
[Rising Waveform]
V_fixture = 3.3V
V_fixture_min = 2.97V
V_fixture_max = 3.63V
R_fixture = 200Ohm
C_fixture = 0F
|   Time   V(typ)   V(min)   V(max)
0s        658.3mV    687.4mV    619.6mV
700.1ps   655.9mV    685.5mV    674.2mV
944.9ps   734.3mV    684.9mV    1.577V
1.268ns   1.733V     702mV      2.41V
1.365ns   1.962V     815.1mV    2.581V
1.748ns   2.575V     1.797V     3.187V
2.174ns   2.998V     2.391V     3.59V
2.592ns   3.25V      2.689V     3.619V
3.5ns     3.293V     2.947V     3.627V
12ns      3.3V       2.97V      3.63V
[Falling Waveform]
|Gnd
V_fixture = 0V
V_fixture_min = 0V
V_fixture_max = 0V
R_fixture = 200Ohm
C_fixture = 0F
|   Time   V(typ)   V(min)   V(max)
0s        2.719V     2.335V     3.107V
633.1ps   2.735V     2.334V     3.063V
865.4ps   2.594V     2.351V     2.353V
1.118ns   1.914V     2.294V     1.529V
1.355ns   1.31V      1.83V      821.7mV
1.575ns   838.5mV    1.305V     434.2mV
1.898ns   367.4mV    777.5mV    182.3mV
2.229ns   164.3mV    391.3mV    43.07mV
3.329ns   6.105mV    15.38mV    2.392mV
12ns      26.93uV    136.8uV    12.83uV
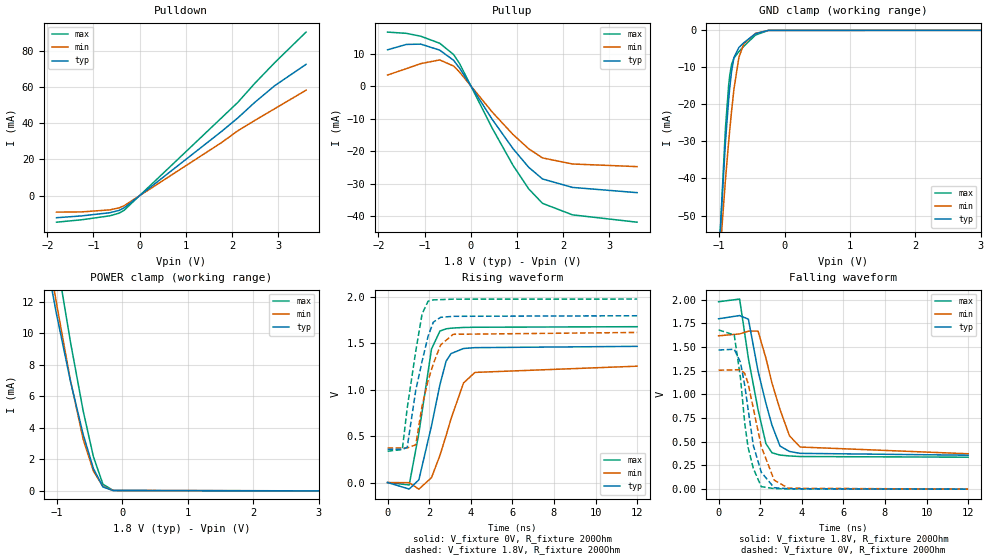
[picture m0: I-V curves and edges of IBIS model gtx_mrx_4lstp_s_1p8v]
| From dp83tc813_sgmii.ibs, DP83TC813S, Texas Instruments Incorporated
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| gtx_mrx_4lstp_s_1p8v
[Model]   gtx_mrx_4lstp_s_1p8v
Model_type   I/O
Polarity   Non-Inverting
Enable   Active-Low
Vinl = 0.63
Vinh = 1.17
Vmeas = 0.9
Vref = 0.9
Cref = 2pF
Rref = 100000
|   typ   min   max
C_comp   2.98pF   2.93pF   3.01pF
[Voltage Range]   1.8   1.62   1.98
[Temperature Range]   27   150   -40
[Pullup Reference]   1.8   1.62   1.98
[Pulldown Reference]   -0   0   -0
[Power Clamp Reference]   1.8   1.62   1.98
[GND Clamp Reference]   0   0   0
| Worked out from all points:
|   slope of the pulldown table from 0 to 0.27 V, typ, clamps not added: 49.7 ohm
|   slope of the pullup table from 0 to 0.27 V, typ, clamps not added: 44.6 ohm
|   GND clamp passes 1 mA (typ) near -0.45 V on its own axis
|   POWER clamp passes 1 mA (typ) near -0.40 V on its own axis
|   falling waveform, V_fixture 1.8V, R_fixture 200Ohm: 20-80 % time 921ps typ, 1.01ns min, 792ps max; typ from 1.8 V to 0.359 V
|   rising waveform, V_fixture 0V, R_fixture 200Ohm: 20-80 % time 824ps typ, 1.04ns min, 672ps max; typ from 0 V to 1.47 V
|   rising waveform, V_fixture 1.8V, R_fixture 200Ohm: 20-80 % time 766ps typ, 826ps min, 650ps max; typ from 0.359 V to 1.8 V
|   falling waveform, V_fixture 0V, R_fixture 200Ohm: 20-80 % time 656ps typ, 780ps min, 549ps max; typ from 1.47 V to 0 V
[Pulldown]
|   Voltage   I(typ)   I(min)   I(max)
-1.8V     -12.09mA   -8.999mA   -14.55mA
-1.255V   -11.09mA   -8.889mA   -13.22mA
-644.4mV  -9.329mA   -7.759mA   -11.03mA
-444.6mV  -8.058mA   -6.661mA   -9.56mA
-336.6mV  -6.654mA   -5.485mA   -8.007mA
1.775V    35.51mA    29.36mA    43.01mA
2.126V    42.92mA    35.84mA    51.5mA
2.488V    51.4mA     41.45mA    61.84mA
2.925V    60.68mA    48mA       73.4mA
3.6V      72.38mA    58.15mA    90.14mA
[GND Clamp]
|   Voltage   I(typ)   I(min)   I(max)
-1.8V     -366.2mA   -316.6mA   -408.2mA
-1.017V   -64.47mA   -67.42mA   -66.03mA
-903.6mV  -30.04mA   -40.21mA   -26.27mA
-855mV    -18.73mA   -30.12mA   -14.83mA
-838.8mV  -15.59mA   -26.98mA   -12.19mA
-811.8mV  -11.25mA   -22.04mA   -9.286mA
-774mV    -7.349mA   -15.87mA   -7.46mA
-698.4mV  -4.626mA   -7.305mA   -5.752mA
-622.8mV  -3.348mA   -3.638mA   -4.29mA
-444.6mV  -906.4uA   -822.3uA   -1.276mA
-244.8mV  -10.16uA   -25.18uA   -9.891uA
3.6V      0A         0A         0A
[Pullup]
|   Voltage   I(typ)   I(min)   I(max)
-1.8V     11.14mA    3.383mA    16.59mA
-1.395V   12.79mA    5.324mA    16.21mA
-1.082V   12.89mA    6.89mA     15.32mA
-671.4mV  11.04mA    8.029mA    13.15mA
-369mV    7.896mA    6.134mA    9.668mA
-239.4mV  5.458mA    4.248mA    6.843mA
462.6mV   -10.22mA   -7.966mA   -12.92mA
916.2mV   -19.3mA    -14.95mA   -24.44mA
1.256V    -25.03mA   -19.33mA   -31.68mA
1.553V    -28.6mA    -22.12mA   -36.1mA
2.201V    -31.2mA    -23.99mA   -39.64mA
3.6V      -32.81mA   -24.8mA    -41.9mA
[POWER Clamp]
|   Voltage   I(typ)   I(min)   I(max)
-1.8V     34.56mA    35.03mA    39.32mA
-1.697V   30.06mA    31.02mA    34.5mA
-1.584V   26.07mA    27.06mA    30.73mA
-1.406V   20.89mA    21.89mA    25.58mA
-1.163V   14.66mA    15.67mA    18.87mA
-1.012V   11.28mA    11.97mA    14.86mA
-795.6mV  6.961mA    7.009mA    9.452mA
-601.2mV  3.583mA    3.285mA    5.08mA
-444.6mV  1.424mA    1.262mA    2.174mA
-298.8mV  249.8uA    284.8uA    427.4uA
-142.2mV  23.02uA    28.73uA    31.52uA
3.6V      0A         0A         0A
[Ramp]
R_load = 200
|   typ   min   max
dV/dt_r   0.881094/8.21192e-10   0.752846/1.04371e-09   1.00849/6.70923e-10
dV/dt_f   0.864477/9.20499e-10   0.747339/1.00722e-09   0.984977/7.90472e-10
[Falling Waveform]
V_fixture = 1.8V
V_fixture_min = 1.62V
V_fixture_max = 1.98V
R_fixture = 200Ohm
C_fixture = 0F
|   Time   V(typ)   V(min)   V(max)
0s        1.799V     1.619V     1.979V
1.012ns   1.833V     1.639V     2.007V
1.433ns   1.795V     1.668V     1.38V
1.897ns   1.247V     1.669V     840.3mV
2.275ns   907.2mV    1.384V     481.4mV
2.566ns   676.2mV    1.121V     384.4mV
2.952ns   455.4mV    842.3mV    359.8mV
3.408ns   397.8mV    563.4mV    350.7mV
3.92ns    378.2mV    444.8mV    344.6mV
12ns      358.5mV    373.8mV    337.6mV
[Rising Waveform]
V_fixture = 0V
V_fixture_min = 0V
V_fixture_max = 0V
R_fixture = 200Ohm
C_fixture = 0F
|   Time   V(typ)   V(min)   V(max)
0s        44.37uV    167.3uV    17.6uV
1.041ns   -69.98mV   -871.2uV   -25.91mV
1.506ns   29.2mV     -71.3mV    532.4mV
2.114ns   612.4mV    52.88mV    1.44V
2.519ns   1.056V     293.4mV    1.634V
2.814ns   1.308V     505.3mV    1.658V
3.052ns   1.391V     687.7mV    1.665V
3.655ns   1.446V     1.075V     1.673V
4.206ns   1.455V     1.188V     1.675V
12ns      1.469V     1.255V     1.681V
[Rising Waveform]
V_fixture = 1.8V
V_fixture_min = 1.62V
V_fixture_max = 1.98V
R_fixture = 200Ohm
C_fixture = 0F
|   Time   V(typ)   V(min)   V(max)
0s        358.5mV    373.8mV    337.6mV
710.7ps   357.9mV    373.4mV    356.6mV
944.1ps   378.5mV    373.3mV    800.5mV
1.356ns   994.8mV    406.8mV    1.417V
1.663ns   1.31V      830.7mV    1.82V
1.95ns    1.579V     1.1V       1.956V
2.201ns   1.73V      1.28V      1.97V
2.549ns   1.782V     1.484V     1.973V
3.159ns   1.793V     1.599V     1.978V
12ns      1.799V     1.619V     1.979V
[Falling Waveform]
|Gnd
V_fixture = 0V
V_fixture_min = 0V
V_fixture_max = 0V
R_fixture = 200Ohm
C_fixture = 0F
|   Time   V(typ)   V(min)   V(max)
0s        1.469V     1.256V     1.681V
753.1ps   1.477V     1.259V     1.628V
1.051ns   1.34V      1.263V     1.177V
1.257ns   1.096V     1.222V     697mV
1.417ns   847.1mV    1.117V     442.8mV
1.67ns    461.5mV    854.3mV    218.7mV
2.053ns   178.6mV    449.1mV    26.65mV
2.672ns   15.61mV    95.27mV    5.888mV
3.361ns   4.297mV    9.942mV    1.886mV
12ns      43.99uV    166.7uV    17.41uV
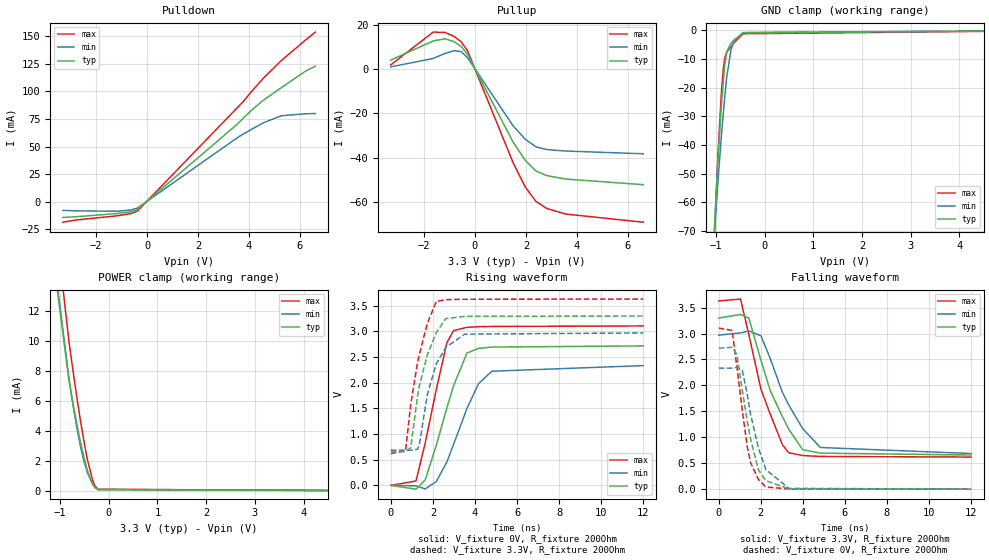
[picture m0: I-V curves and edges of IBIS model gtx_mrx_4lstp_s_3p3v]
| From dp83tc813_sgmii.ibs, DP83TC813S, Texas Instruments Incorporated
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| gtx_mrx_4lstp_s_3p3v
[Model]   gtx_mrx_4lstp_s_3p3v
Model_type   I/O
Polarity   Non-Inverting
Enable   Active-Low
Vinl = 0.8
Vinh = 2
Vmeas = 1.65
Vref = 1.65
Cref = 2pF
Rref = 100000
|   typ   min   max
C_comp   2.96pF   2.91pF   2.99pF
[Voltage Range]   3.3   2.97   3.63
[Temperature Range]   27   150   -40
[Pullup Reference]   3.3   2.97   3.63
[Pulldown Reference]   -0   0   -0
[Power Clamp Reference]   3.3   2.97   3.63
[GND Clamp Reference]   0   0   0
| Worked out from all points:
|   slope of the pulldown table from 0 to 0.495 V, typ, clamps not added: 49.7 ohm
|   slope of the pullup table from 0 to 0.495 V, typ, clamps not added: 42.6 ohm
|   GND clamp passes 1 mA (typ) near -0.45 V on its own axis
|   POWER clamp passes 1 mA (typ) near -0.40 V on its own axis
|   falling waveform, V_fixture 3.3V, R_fixture 200Ohm: 20-80 % time 1.46ns typ, 1.57ns min, 1.25ns max; typ from 3.3 V to 0.658 V
|   rising waveform, V_fixture 0V, R_fixture 200Ohm: 20-80 % time 1.16ns typ, 1.34ns min, 958ps max; typ from 0 V to 2.72 V
|   rising waveform, V_fixture 3.3V, R_fixture 200Ohm: 20-80 % time 872ps typ, 869ps min, 809ps max; typ from 0.658 V to 3.3 V
|   falling waveform, V_fixture 0V, R_fixture 200Ohm: 20-80 % time 715ps typ, 810ps min, 620ps max; typ from 2.72 V to 0 V
[Pulldown]
|   Voltage   I(typ)   I(min)   I(max)
-3.3V     -14.49mA   -8.058mA   -18.8mA
-2.775V   -13.84mA   -8.495mA   -16.78mA
-1.211V   -11mA      -8.856mA   -13.1mA
-636.9mV  -9.29mA    -7.726mA   -10.99mA
-379.5mV  -7.291mA   -6.009mA   -8.741mA
3.521V    69.9mA     57.68mA    84.83mA
3.769V    75.65mA    61.21mA    90.72mA
4.125V    83.52mA    65.97mA    100.7mA
4.561V    92.04mA    71.53mA    112mA
5.263V    103.4mA    77.95mA    128mA
6.204V    118.3mA    79.76mA    146.6mA
6.6V      123mA      79.94mA    154mA
[GND Clamp]
|   Voltage   I(typ)   I(min)   I(max)
-3.3V     -975.6mA   -833.8mA   -1.088A
-1.082V   -87.42mA   -85.76mA   -92.38mA
-1.053V   -76.87mA   -77.4mA    -80.24mA
-953.7mV  -44.39mA   -51.98mA   -42.32mA
-884.4mV  -25.71mA   -36.46mA   -21.17mA
-844.8mV  -17.71mA   -28.63mA   -13.09mA
-815.1mV  -11.71mA   -22.76mA   -9.548mA
-775.5mV  -7.456mA   -16.2mA    -7.571mA
-686.4mV  -4.401mA   -6.504mA   -5.581mA
-617.1mV  -3.26mA    -3.482mA   -4.186mA
-438.9mV  -845.7uA   -772.4uA   -1.203mA
6.6V      0A         0A         0A
[Pullup]
|   Voltage   I(typ)   I(min)   I(max)
-3.3V     4.209mA    1.152mA    2.057mA
-1.637V   12.93mA    4.984mA    16.93mA
-1.171V   13.87mA    7.252mA    16.75mA
-815.1mV  12.56mA    8.506mA    14.96mA
-537.9mV  10.43mA    8.083mA    12.52mA
-290.4mV  6.774mA    5.308mA    8.451mA
1.492V    -32.92mA   -25.55mA   -42.2mA
1.967V    -41.16mA   -31.63mA   -53.19mA
2.383V    -46.04mA   -35.1mA    -59.82mA
2.818V    -48.19mA   -36.38mA   -63.11mA
3.561V    -49.75mA   -37.04mA   -65.65mA
6.6V      -52.31mA   -38.29mA   -69.33mA
[POWER Clamp]
|   Voltage   I(typ)   I(min)   I(max)
-3.3V     265.1mA    186.4mA    350mA
-1.657V   28.53mA    29.54mA    34.23mA
-815.1mV  7.344mA    7.443mA    9.937mA
-726mV    5.701mA    5.57mA     7.848mA
-646.8mV  4.335mA    4.068mA    6.071mA
-577.5mV  3.23mA     2.925mA    4.63mA
-508.2mV  2.233mA    1.972mA    3.307mA
-438.9mV  1.375mA    1.218mA    2.106mA
-330mV    440.2uA    443.7uA    710.7uA
-280.5mV  210uA      241.9uA    330.1uA
-221.1mV  74.04uA    100.7uA    110.8uA
6.6V      0A         0A         0A
[Ramp]
R_load = 200
|   typ   min   max
dV/dt_r   1.62986/1.15396e-09   1.39959/1.3371e-09   1.86295/9.55592e-10
dV/dt_f   1.58443/1.44844e-09   1.36901/1.56497e-09   1.80555/1.25074e-09
[Falling Waveform]
V_fixture = 3.3V
V_fixture_min = 2.97V
V_fixture_max = 3.63V
R_fixture = 200Ohm
C_fixture = 0F
|   Time   V(typ)   V(min)   V(max)
0s        3.299V     2.969V     3.629V
1.035ns   3.369V     3.013V     3.665V
1.433ns   3.298V     3.05V      2.978V
2.006ns   2.486V     2.958V     1.93V
2.457ns   1.89V      2.51V      1.438V
3.025ns   1.4V       1.868V     860.1mV
3.325ns   1.158V     1.625V     703mV
3.99ns    762mV      1.169V     648.5mV
4.828ns   694.6mV    803.7mV    630.8mV
12ns      658.1mV    687.3mV    619.4mV
[Rising Waveform]
V_fixture = 0V
V_fixture_min = 0V
V_fixture_max = 0V
R_fixture = 200Ohm
C_fixture = 0F
|   Time   V(typ)   V(min)   V(max)
0s        139uV      222.9uV    127.9uV
1.199ns   -73.45mV   -8.811mV   85.7mV
1.636ns   106.2mV    -69.01mV   828.9mV
2.166ns   785.6mV    76.77mV    1.873V
2.665ns   1.508V     454.8mV    2.779V
2.981ns   1.938V     796mV      3.014V
3.618ns   2.577V     1.496V     3.078V
4.167ns   2.668V     1.98V      3.091V
4.803ns   2.694V     2.224V     3.096V
12ns      2.717V     2.333V     3.105V
[Rising Waveform]
V_fixture = 3.3V
V_fixture_min = 2.97V
V_fixture_max = 3.63V
R_fixture = 200Ohm
C_fixture = 0F
|   Time   V(typ)   V(min)   V(max)
0s        658.1mV    687.3mV    619.4mV
700.6ps   655.8mV    685.4mV    673.4mV
944.7ps   732.2mV    684.8mV    1.572V
1.272ns   1.739V     703.9mV    2.399V
1.366ns   1.956V     815.4mV    2.566V
1.739ns   2.549V     1.773V     3.159V
2.163ns   2.974V     2.369V     3.582V
2.608ns   3.249V     2.685V     3.618V
3.511ns   3.292V     2.946V     3.625V
12ns      3.299V     2.969V     3.629V
[Falling Waveform]
|Gnd
V_fixture = 0V
V_fixture_min = 0V
V_fixture_max = 0V
R_fixture = 200Ohm
C_fixture = 0F
|   Time   V(typ)   V(min)   V(max)
0s        2.718V     2.334V     3.106V
632.7ps   2.734V     2.334V     3.062V
862.7ps   2.598V     2.35V      2.363V
1.118ns   1.915V     2.294V     1.533V
1.349ns   1.327V     1.844V     837.8mV
1.514ns   969.4mV    1.444V     509.3mV
1.89ns    369.5mV    791.3mV    187.3mV
2.241ns   162.9mV    378.1mV    42.51mV
3.336ns   5.916mV    16.04mV    3.324mV
12ns      139.1uV    225.3uV    127.8uV
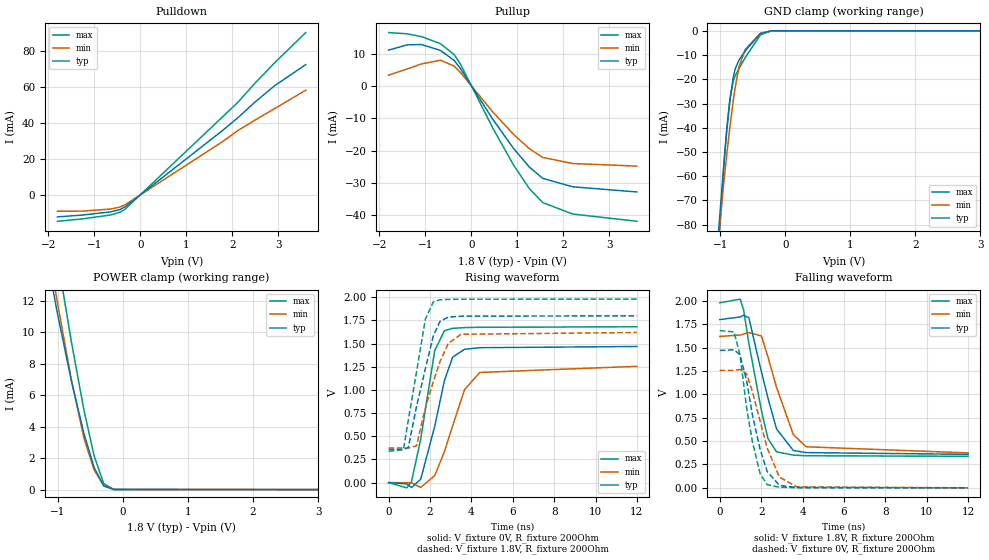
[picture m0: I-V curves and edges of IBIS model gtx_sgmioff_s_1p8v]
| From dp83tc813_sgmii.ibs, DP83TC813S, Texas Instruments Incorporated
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| gtx_sgmioff_s_1p8v
[Model]   gtx_sgmioff_s_1p8v
Model_type   I/O
Polarity   Non-Inverting
Enable   Active-Low
Vinl = 0.63
Vinh = 1.17
Vmeas = 0.9
Vref = 0.9
Cref = 2pF
Rref = 100000
|   typ   min   max
C_comp   4.18pF   4pF   4.27pF
[Voltage Range]   1.8   1.62   1.98
[Temperature Range]   27   150   -40
[Pullup Reference]   1.8   1.62   1.98
[Pulldown Reference]   0   0   0
[Power Clamp Reference]   1.8   1.62   1.98
[GND Clamp Reference]   0   0   0
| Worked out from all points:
|   slope of the pulldown table from 0 to 0.27 V, typ, clamps not added: 49.7 ohm
|   slope of the pullup table from 0 to 0.27 V, typ, clamps not added: 44.6 ohm
|   GND clamp passes 1 mA (typ) near -0.38 V on its own axis
|   POWER clamp passes 1 mA (typ) near -0.41 V on its own axis
|   falling waveform, V_fixture 1.8V, R_fixture 200Ohm: 20-80 % time 970ps typ, 1.07ns min, 835ps max; typ from 1.8 V to 0.359 V
|   rising waveform, V_fixture 0V, R_fixture 200Ohm: 20-80 % time 877ps typ, 1.11ns min, 716ps max; typ from 0 V to 1.47 V
|   rising waveform, V_fixture 1.8V, R_fixture 200Ohm: 20-80 % time 894ps typ, 1.03ns min, 735ps max; typ from 0.359 V to 1.8 V
|   falling waveform, V_fixture 0V, R_fixture 200Ohm: 20-80 % time 843ps typ, 987ps min, 711ps max; typ from 1.47 V to 0 V
[Pulldown]
|   Voltage   I(typ)   I(min)   I(max)
-1.8V     -12.09mA   -8.999mA   -14.55mA
-1.255V   -11.09mA   -8.889mA   -13.22mA
-644.4mV  -9.329mA   -7.759mA   -11.03mA
-444.6mV  -8.058mA   -6.661mA   -9.56mA
-336.6mV  -6.654mA   -5.485mA   -8.007mA
1.775V    35.51mA    29.36mA    43.01mA
2.126V    42.92mA    35.84mA    51.5mA
2.488V    51.4mA     41.45mA    61.84mA
2.925V    60.68mA    48mA       73.4mA
3.6V      72.38mA    58.15mA    90.14mA
[GND Clamp]
|   Voltage   I(typ)   I(min)   I(max)
-1.8V     -404.5mA   -355.7mA   -450mA
-1.022V   -80.8mA    -83.52mA   -86.5mA
-941.4mV  -52.96mA   -61.02mA   -54.11mA
-903.6mV  -41.61mA   -51.46mA   -41.21mA
-855mV    -29.13mA   -40.03mA   -28.37mA
-801mV    -19mA      -28.64mA   -20.57mA
-774mV    -15.85mA   -23.64mA   -18.69mA
-714.6mV  -12.12mA   -14.96mA   -15.62mA
-617.4mV  -8.27mA    -7.637mA   -11.03mA
-385.2mV  -1.108mA   -1.043mA   -1.72mA
-217.8mV  -10.59uA   -38.42uA   -7.495uA
3.6V      0A         0A         0A
[Pullup]
|   Voltage   I(typ)   I(min)   I(max)
-1.8V     11.14mA    3.383mA    16.59mA
-1.395V   12.79mA    5.324mA    16.21mA
-1.082V   12.89mA    6.89mA     15.32mA
-671.4mV  11.04mA    8.029mA    13.15mA
-369mV    7.896mA    6.134mA    9.668mA
-239.4mV  5.458mA    4.248mA    6.843mA
462.6mV   -10.22mA   -7.966mA   -12.92mA
916.2mV   -19.3mA    -14.95mA   -24.44mA
1.256V    -25.03mA   -19.33mA   -31.68mA
1.553V    -28.6mA    -22.12mA   -36.1mA
2.201V    -31.2mA    -23.99mA   -39.64mA
3.6V      -32.81mA   -24.8mA    -41.9mA
[POWER Clamp]
|   Voltage   I(typ)   I(min)   I(max)
-1.8V     34.46mA    34.96mA    39.2mA
-1.697V   29.97mA    30.95mA    34.38mA
-1.584V   25.99mA    26.99mA    30.62mA
-1.406V   20.81mA    21.83mA    25.48mA
-1.157V   14.47mA    15.49mA    18.64mA
-1.012V   11.22mA    11.92mA    14.78mA
-795.6mV  6.913mA    6.972mA    9.388mA
-601.2mV  3.544mA    3.256mA    5.027mA
-444.6mV  1.393mA    1.238mA    2.131mA
-298.8mV  225.6uA    266.8uA    392.5uA
-142.2mV  3.419uA    14.8uA     2.982uA
3.6V      0A         0A         0A
[Ramp]
R_load = 200
|   typ   min   max
dV/dt_r   0.881403/8.74646e-10   0.753106/1.1089e-09   1.0089/7.14045e-10
dV/dt_f   0.864787/9.70378e-10   0.747595/1.07272e-09   0.985355/8.33235e-10
[Falling Waveform]
V_fixture = 1.8V
V_fixture_min = 1.62V
V_fixture_max = 1.98V
R_fixture = 200Ohm
C_fixture = 0F
|   Time   V(typ)   V(min)   V(max)
0s        1.8V       1.62V      1.98V
985.2ps   1.828V     1.635V     2.019V
1.155ns   1.846V     1.646V     1.901V
1.403ns   1.821V     1.661V     1.549V
2.012ns   1.241V     1.625V     827.2mV
2.327ns   960.5mV    1.402V     527.4mV
2.743ns   630.3mV    1.076V     385.5mV
3.554ns   400mV      570mV      350.4mV
4.176ns   377.1mV    439.4mV    343.5mV
12ns      358.7mV    373.9mV    337.7mV
[Rising Waveform]
V_fixture = 0V
V_fixture_min = 0V
V_fixture_max = 0V
R_fixture = 200Ohm
C_fixture = 0F
|   Time   V(typ)   V(min)   V(max)
0s        25.21uV    132.8uV    11.49uV
876.1ps   -13.45mV   -593.9uV   -56.28mV
1.104ns   -52.82mV   -783uV     9.756mV
1.551ns   36.07mV    -52.4mV    470.5mV
2.23ns    610.5mV    76.48mV    1.426V
2.694ns   1.099V     333.5mV    1.639V
3.094ns   1.354V     614.1mV    1.665V
3.672ns   1.439V     1.004V     1.673V
4.405ns   1.456V     1.189V     1.676V
12ns      1.469V     1.255V     1.682V
[Rising Waveform]
V_fixture = 1.8V
V_fixture_min = 1.62V
V_fixture_max = 1.98V
R_fixture = 200Ohm
C_fixture = 0F
|   Time   V(typ)   V(min)   V(max)
0s        358.7mV    373.9mV    337.7mV
713.9ps   358mV      373.5mV    355.1mV
948.8ps   376.9mV    373.3mV    672.3mV
1.351ns   825.2mV    397.3mV    1.197V
1.772ns   1.226V     805.9mV    1.761V
2.165ns   1.587V     1.095V     1.952V
2.485ns   1.741V     1.307V     1.973V
2.884ns   1.786V     1.502V     1.977V
3.498ns   1.796V     1.601V     1.979V
12ns      1.8V       1.62V      1.98V
[Falling Waveform]
|Gnd
V_fixture = 0V
V_fixture_min = 0V
V_fixture_max = 0V
R_fixture = 200Ohm
C_fixture = 0F
|   Time   V(typ)   V(min)   V(max)
0s        1.47V      1.256V     1.682V
691.7ps   1.477V     1.257V     1.668V
978.9ps   1.423V     1.266V     1.42V
1.298ns   1.145V     1.22V      851mV
1.574ns   783.1mV    1.031V     497.5mV
1.951ns   410.6mV    712.7mV    148.8mV
2.292ns   175.1mV    425.8mV    34.42mV
2.884ns   25.54mV    115.2mV    6.885mV
3.718ns   3.754mV    11.38mV    1.828mV
12ns      25.28uV    133uV      11.58uV
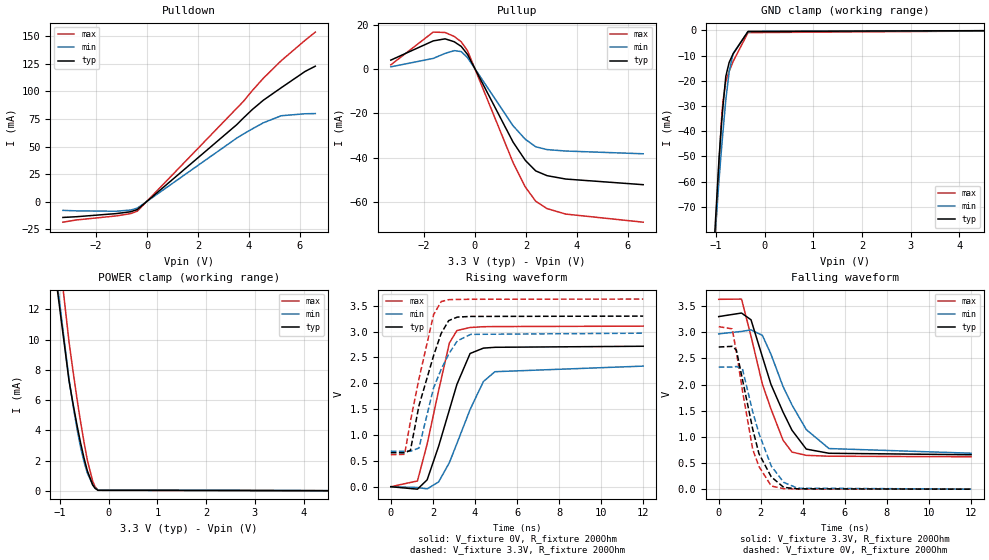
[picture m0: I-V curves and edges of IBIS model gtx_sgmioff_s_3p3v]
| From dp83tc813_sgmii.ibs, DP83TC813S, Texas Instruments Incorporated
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| gtx_sgmioff_s_3p3v
[Model]   gtx_sgmioff_s_3p3v
Model_type   I/O
Polarity   Non-Inverting
Enable   Active-Low
Vinl = 0.8
Vinh = 2
Vmeas = 1.65
Vref = 1.65
Cref = 2pF
Rref = 100000
|   typ   min   max
C_comp   4.07pF   3.89pF   4.16pF
[Voltage Range]   3.3   2.97   3.63
[Temperature Range]   27   150   -40
[Pullup Reference]   3.3   2.97   3.63
[Pulldown Reference]   -0   -0   0
[Power Clamp Reference]   3.3   2.97   3.63
[GND Clamp Reference]   0   0   0
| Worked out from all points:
|   slope of the pulldown table from 0 to 0.495 V, typ, clamps not added: 49.7 ohm
|   slope of the pullup table from 0 to 0.495 V, typ, clamps not added: 42.6 ohm
|   GND clamp passes 1 mA (typ) near -0.37 V on its own axis
|   POWER clamp passes 1 mA (typ) near -0.40 V on its own axis
|   falling waveform, V_fixture 3.3V, R_fixture 200Ohm: 20-80 % time 1.49ns typ, 1.61ns min, 1.29ns max; typ from 3.3 V to 0.658 V
|   rising waveform, V_fixture 0V, R_fixture 200Ohm: 20-80 % time 1.19ns typ, 1.38ns min, 987ps max; typ from 0 V to 2.72 V
|   rising waveform, V_fixture 3.3V, R_fixture 200Ohm: 20-80 % time 1.08ns typ, 1.15ns min, 937ps max; typ from 0.658 V to 3.3 V
|   falling waveform, V_fixture 0V, R_fixture 200Ohm: 20-80 % time 953ps typ, 1.06ns min, 832ps max; typ from 2.72 V to 0 V
[Pulldown]
|   Voltage   I(typ)   I(min)   I(max)
-3.3V     -14.49mA   -8.058mA   -18.8mA
-2.775V   -13.84mA   -8.495mA   -16.78mA
-1.211V   -11mA      -8.856mA   -13.1mA
-636.9mV  -9.29mA    -7.726mA   -10.99mA
-379.5mV  -7.291mA   -6.009mA   -8.741mA
3.521V    69.9mA     57.68mA    84.83mA
3.769V    75.65mA    61.21mA    90.72mA
4.125V    83.52mA    65.97mA    100.7mA
4.561V    92.04mA    71.53mA    112mA
5.263V    103.4mA    77.95mA    128mA
6.204V    118.3mA    79.76mA    146.6mA
6.6V      123mA      79.94mA    154mA
[GND Clamp]
|   Voltage   I(typ)   I(min)   I(max)
-3.3V     -1.068A    -919.5mA   -1.194A
-1.063V   -95.77mA   -95.65mA   -103.8mA
-1.053V   -92.03mA   -92.61mA   -99.49mA
-1.013V   -77.42mA   -80.8mA    -82.59mA
-933.9mV  -50.61mA   -59.08mA   -52.39mA
-884.4mV  -37.2mA    -47.13mA   -35.56mA
-854.7mV  -30.33mA   -40.41mA   -28.31mA
-795.3mV  -18.22mA   -27.54mA   -20.25mA
-726mV    -12.66mA   -16.34mA   -16.19mA
-646.8mV  -9.375mA   -9.225mA   -12.4mA
-339.9mV  -438.3uA   -510.9uA   -906.4uA
6.6V      0A         0A         0A
[Pullup]
|   Voltage   I(typ)   I(min)   I(max)
-3.3V     4.209mA    1.152mA    2.057mA
-1.637V   12.93mA    4.984mA    16.93mA
-1.171V   13.87mA    7.252mA    16.75mA
-815.1mV  12.56mA    8.506mA    14.96mA
-537.9mV  10.43mA    8.083mA    12.52mA
-290.4mV  6.774mA    5.308mA    8.451mA
1.492V    -32.92mA   -25.55mA   -42.17mA
1.977V    -41.31mA   -31.73mA   -53.39mA
2.383V    -46.05mA   -35.1mA    -59.82mA
2.828V    -48.22mA   -36.39mA   -63.16mA
3.561V    -49.75mA   -37.04mA   -65.65mA
6.6V      -52.31mA   -38.29mA   -69.33mA
[POWER Clamp]
|   Voltage   I(typ)   I(min)   I(max)
-3.3V     264.9mA    186.2mA    349.8mA
-1.657V   28.42mA    29.46mA    34.09mA
-815.1mV  7.28mA     7.395mA    9.85mA
-726mV    5.642mA    5.525mA    7.766mA
-646.8mV  4.28mA     4.026mA    5.994mA
-577.5mV  3.178mA    2.886mA    4.557mA
-508.2mV  2.184mA    1.935mA    3.238mA
-438.9mV  1.329mA    1.184mA    2.041mA
-330mV    399.7uA    414.2uA    652.1uA
-280.5mV  171.6uA    214.1uA    274.2uA
-221.1mV  37.72uA    74.67uA    57.75uA
6.6V      0A         0A         0A
[Ramp]
R_load = 200
|   typ   min   max
dV/dt_r   1.63042/1.18767e-09   1.39992/1.38086e-09   1.86374/9.84036e-10
dV/dt_f   1.58499/1.48579e-09   1.36942/1.60381e-09   1.80625/1.2881e-09
[Falling Waveform]
V_fixture = 3.3V
V_fixture_min = 2.97V
V_fixture_max = 3.63V
R_fixture = 200Ohm
C_fixture = 0F
|   Time   V(typ)   V(min)   V(max)
0s        3.3V       2.97V      3.63V
1.084ns   3.368V     3.016V     3.635V
1.535ns   3.238V     3.046V     2.924V
2.075ns   2.532V     2.941V     2.009V
2.483ns   2.004V     2.581V     1.534V
3.058ns   1.474V     1.962V     936.7mV
3.481ns   1.128V     1.611V     709.1mV
4.164ns   766.1mV    1.138V     647mV
5.243ns   686.2mV    776.5mV    630.1mV
12ns      658.3mV    687.5mV    619.6mV
[Rising Waveform]
V_fixture = 0V
V_fixture_min = 0V
V_fixture_max = 0V
R_fixture = 200Ohm
C_fixture = 0F
|   Time   V(typ)   V(min)   V(max)
0s        27.97uV    140.3uV    13.12uV
1.266ns   -47.54mV   -15.3mV    111.2mV
1.727ns   132.5mV    -42.76mV   824.2mV
2.273ns   782.5mV    92.56mV    1.86V
2.785ns   1.487V     466.4mV    2.781V
3.142ns   1.979V     836mV      3.021V
3.769ns   2.577V     1.493V     3.08V
4.402ns   2.681V     2.035V     3.095V
4.95ns    2.697V     2.225V     3.098V
12ns      2.717V     2.333V     3.106V
[Rising Waveform]
V_fixture = 3.3V
V_fixture_min = 2.97V
V_fixture_max = 3.63V
R_fixture = 200Ohm
C_fixture = 0F
|   Time   V(typ)   V(min)   V(max)
0s        658.3mV    687.5mV    619.6mV
656ps     656.6mV    686mV      626.7mV
933.8ps   704.4mV    685.4mV    1.269V
1.337ns   1.566V     748.8mV    2.083V
2.031ns   2.532V     1.908V     3.326V
2.393ns   2.965V     2.269V     3.581V
2.751ns   3.213V     2.565V     3.618V
3.162ns   3.281V     2.822V     3.623V
3.8ns     3.294V     2.947V     3.626V
12ns      3.3V       2.97V      3.63V
[Falling Waveform]
|Gnd
V_fixture = 0V
V_fixture_min = 0V
V_fixture_max = 0V
R_fixture = 200Ohm
C_fixture = 0F
|   Time   V(typ)   V(min)   V(max)
0s        2.718V     2.335V     3.107V
641.1ps   2.731V     2.335V     3.066V
837.6ps   2.66V      2.346V     2.628V
1.128ns   2.098V     2.299V     1.883V
1.615ns   1.149V     1.482V     762mV
1.913ns   677.8mV    1.065V     433.6mV
2.497ns   235.4mV    442.9mV    59.99mV
3.088ns   34.8mV     130.2mV    10.28mV
3.745ns   6.614mV    19.59mV    2.868mV
12ns      28.1uV     140.5uV    13.29uV
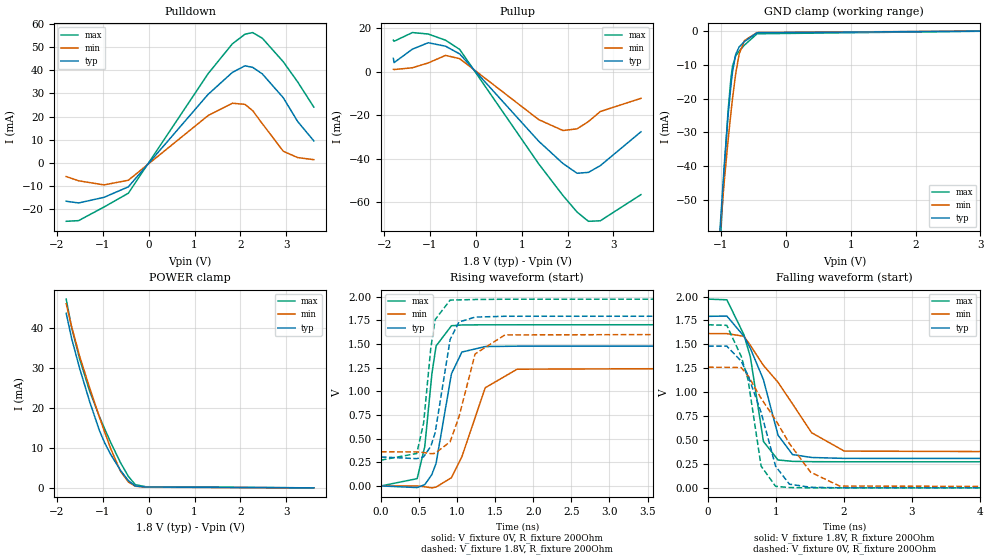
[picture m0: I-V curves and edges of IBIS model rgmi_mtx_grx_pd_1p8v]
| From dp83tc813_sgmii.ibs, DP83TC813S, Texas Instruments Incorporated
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| rgmi_mtx_grx_pd_1p8v
[Model]   rgmi_mtx_grx_pd_1p8v
Model_type   I/O
Polarity   Non-Inverting
Enable   Active-Low
Vinl = 0.63
Vinh = 1.17
Vmeas = 0.9
Vref = 0.9
Cref = 2pF
Rref = 100000
|   typ   min   max
C_comp   1.78pF   1.74pF   1.81pF
[Voltage Range]   1.8   1.62   1.98
[Temperature Range]   27   150   -40
[Pullup Reference]   1.8   1.62   1.98
[Pulldown Reference]   0   0   0
[Power Clamp Reference]   1.8   1.62   1.98
[GND Clamp Reference]   0   0   0
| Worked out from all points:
|   slope of the pulldown table from 0 to 0.27 V, typ, clamps not added: 41.1 ohm
|   slope of the pullup table from 0 to 0.27 V, typ, clamps not added: 40.5 ohm
|   GND clamp passes 1 mA (typ) near -0.48 V on its own axis
|   POWER clamp passes 1 mA (typ) near -0.37 V on its own axis
|   falling waveform, V_fixture 1.8V, R_fixture 200Ohm: 20-80 % time 406ps typ, 751ps min, 268ps max; typ from 1.79 V to 0.306 V
|   rising waveform, V_fixture 0V, R_fixture 200Ohm: 20-80 % time 183ps typ, 312ps min, 137ps max; typ from 0 V to 1.48 V
|   rising waveform, V_fixture 1.8V, R_fixture 200Ohm: 20-80 % time 169ps typ, 234ps min, 133ps max; typ from 0.306 V to 1.79 V
|   falling waveform, V_fixture 0V, R_fixture 200Ohm: 20-80 % time 374ps typ, 673ps min, 251ps max; typ from 1.48 V to 0 V
[Pulldown]
|   Voltage   I(typ)   I(min)   I(max)
-1.8V     -16.61mA   -5.947mA   -25.29mA
-1.53V    -17.36mA   -7.777mA   -25mA
-973.8mV  -14.92mA   -9.557mA   -19.1mA
-444.6mV  -10.39mA   -7.539mA   -13.15mA
1.294V    29.56mA    20.41mA    38.51mA
1.823V    39.07mA    25.75mA    51.41mA
2.099V    41.94mA    25.27mA    55.59mA
2.266V    41.26mA    22.56mA    56.3mA
2.477V    38.44mA    16.93mA    53.86mA
2.936V    28.08mA    4.971mA    43.64mA
3.249V    17.82mA    2.251mA    34.94mA
3.6V      9.489mA    1.359mA    24.09mA
[GND Clamp]
|   Voltage   I(typ)   I(min)   I(max)
-1.8V     -336.2mA   -294.1mA   -377.3mA
-1.044V   -67.35mA   -66.55mA   -74.39mA
-1.006V   -55.64mA   -57.19mA   -60.57mA
-946.8mV  -38.59mA   -43.64mA   -40.08mA
-892.8mV  -25.23mA   -32.55mA   -23.92mA
-844.2mV  -15.51mA   -23.55mA   -13.32mA
-822.6mV  -12.07mA   -19.88mA   -10.4mA
-774mV    -6.941mA   -12.62mA   -7.387mA
-720mV    -4.719mA   -6.796mA   -5.965mA
-639mV    -3.158mA   -2.89mA    -4.209mA
-444.6mV  -576.6uA   -482.6uA   -870.1uA
3.6V      0A         0A         0A
[Pullup]
|   Voltage   I(typ)   I(min)   I(max)
-1.8V     6.22mA     1.188mA    14.62mA
-1.784V   4.258mA    1.056mA    14.1mA
-1.384V   10.46mA    1.885mA    18.11mA
-1.039V   13.43mA    4.114mA    17.44mA
-660.6mV  11.82mA    7.583mA    14.58mA
-352.8mV  8.262mA    6.081mA    10.34mA
1.37V     -31.95mA   -22mA      -42.39mA
1.899V    -42.23mA   -27.04mA   -56.98mA
2.207V    -46.73mA   -26.27mA   -64.62mA
2.455V    -46.33mA   -22.91mA   -68.88mA
2.714V    -43.23mA   -18.28mA   -68.64mA
3.6V      -27.62mA   -12.21mA   -56.59mA
[POWER Clamp]
|   Voltage   I(typ)   I(min)   I(max)
-1.8V     43.64mA    46.02mA    47.18mA
-1.681V   37.31mA    40.26mA    40.01mA
-1.508V   29.91mA    32.94mA    32.26mA
-1.292V   21.69mA    25.11mA    24.27mA
-1.082V   14.53mA    17.91mA    18.01mA
-963mV    11.29mA    13.99mA    14.8mA
-828mV    8.315mA    9.758mA    11.32mA
-617.4mV  4.395mA    4.184mA    6.332mA
-444.6mV  1.812mA    1.467mA    2.879mA
-293.4mV  464.7uA    404.7uA    797uA
-66.6mV   211.3uA    161.7uA    282.4uA
3.6V      0A         0A         0A
[Ramp]
R_load = 200
|   typ   min   max
dV/dt_r   0.888842/1.80491e-10   0.756393/3.09159e-10   1.02293/1.36495e-10
dV/dt_f   0.892067/4.06808e-10   0.751685/7.49848e-10   1.02018/2.66483e-10
[Falling Waveform]
V_fixture = 1.8V
V_fixture_min = 1.62V
V_fixture_max = 1.98V
R_fixture = 200Ohm
C_fixture = 0F
|   Time   V(typ)   V(min)   V(max)
0s        1.793V     1.613V     1.973V
276.3ps   1.796V     1.612V     1.966V
526.4ps   1.586V     1.585V     1.603V
621.8ps   1.459V     1.49V      1.37V
814.4ps   1.131V     1.28V      485.5mV
1.029ns   551.6mV    1.104V     291.5mV
1.243ns   348.1mV    877.8mV    277.1mV
1.523ns   317.6mV    576.5mV    273.8mV
2.004ns   308.1mV    384.4mV    272.6mV
12ns      306.2mV    360.1mV    272.3mV
[Rising Waveform]
V_fixture = 0V
V_fixture_min = 0V
V_fixture_max = 0V
R_fixture = 200Ohm
C_fixture = 0F
|   Time   V(typ)   V(min)   V(max)
0s        435.6nV    7.602uV    172.5nV
475.5ps   -17.28mV   -345.5uV   76.87mV
575.7ps   13.59mV    -9.119mV   418.1mV
668ps     119.7mV    -20.39mV   1.178V
723.7ps   238.7mV    -12.18mV   1.478V
925.8ps   1.185V     87.27mV    1.692V
1.063ns   1.414V     309.5mV    1.7V
1.369ns   1.472V     1.037V     1.702V
1.788ns   1.476V     1.233V     1.702V
12ns      1.481V     1.261V     1.705V
[Rising Waveform]
V_fixture = 1.8V
V_fixture_min = 1.62V
V_fixture_max = 1.98V
R_fixture = 200Ohm
C_fixture = 0F
|   Time   V(typ)   V(min)   V(max)
0s        306.2mV    360.1mV    272.3mV
469.6ps   288mV      359.7mV    342.9mV
559.6ps   306.6mV    352.9mV    662mV
654.2ps   417.5mV    340.6mV    1.454V
711.1ps   560mV      343.6mV    1.756V
908.5ps   1.548V     467.1mV    1.963V
1.024ns   1.731V     728.4mV    1.965V
1.236ns   1.783V     1.394V     1.969V
1.627ns   1.792V     1.595V     1.972V
12ns      1.793V     1.613V     1.973V
[Falling Waveform]
|Gnd
V_fixture = 0V
V_fixture_min = 0V
V_fixture_max = 0V
R_fixture = 200Ohm
C_fixture = 0F
|   Time   V(typ)   V(min)   V(max)
0s        1.482V     1.261V     1.705V
275.4ps   1.482V     1.26V      1.699V
487.8ps   1.324V     1.257V     1.374V
589ps     1.173V     1.171V     1.127V
780.1ps   789.6mV    935.9mV    227.6mV
993.4ps   226.2mV    710.5mV    15.93mV
1.197ns   38.5mV     462.5mV    3.253mV
1.51ns    6.143mV    163.2mV    203.1uV
1.935ns   932.5uV    19.1mV     60.43uV
12ns      603.4nV    7.602uV    272.2nV
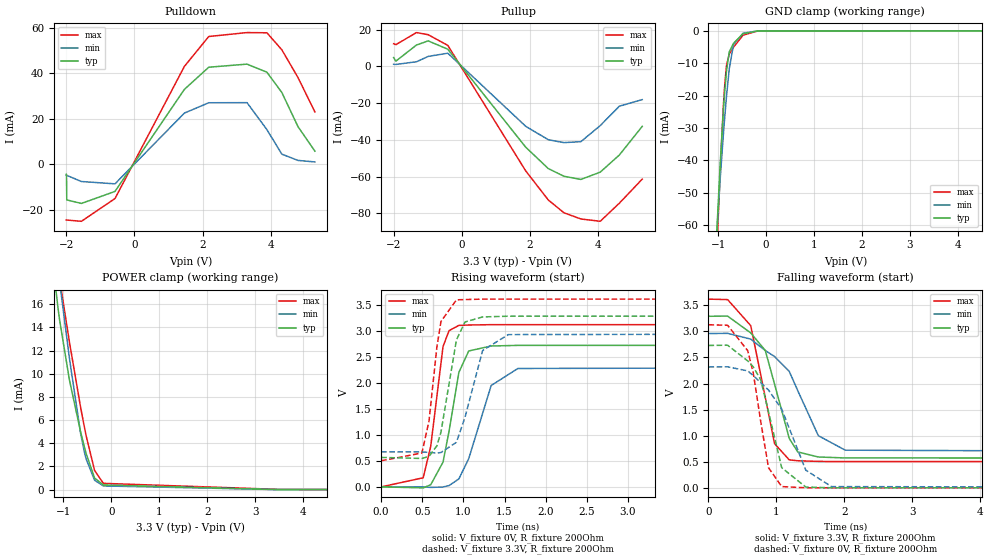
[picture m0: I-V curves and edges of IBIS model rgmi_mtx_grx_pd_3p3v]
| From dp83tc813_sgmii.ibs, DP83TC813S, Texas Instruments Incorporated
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| rgmi_mtx_grx_pd_3p3v
[Model]   rgmi_mtx_grx_pd_3p3v
Model_type   I/O
Polarity   Non-Inverting
Enable   Active-Low
Vinl = 0.8
Vinh = 2
Vmeas = 1.65
Vref = 1.65
Cref = 2pF
Rref = 100000
|   typ   min   max
C_comp   1.77pF   1.74pF   1.8pF
[Voltage Range]   3.3   2.97   3.63
[Temperature Range]   27   150   -40
[Pullup Reference]   3.3   2.97   3.63
[Pulldown Reference]   0   0   0
[Power Clamp Reference]   3.3   2.97   3.63
[GND Clamp Reference]   0   0   0
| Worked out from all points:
|   slope of the pulldown table from 0 to 0.495 V, typ, clamps not added: 41.6 ohm
|   slope of the pullup table from 0 to 0.495 V, typ, clamps not added: 39.9 ohm
|   GND clamp passes 1 mA (typ) near -0.49 V on its own axis
|   POWER clamp passes 1 mA (typ) near -0.35 V on its own axis
|   falling waveform, V_fixture 3.3V, R_fixture 200Ohm: 20-80 % time 351ps typ, 564ps min, 268ps max; typ from 3.29 V to 0.567 V
|   rising waveform, V_fixture 0V, R_fixture 200Ohm: 20-80 % time 179ps typ, 261ps min, 141ps max; typ from 0 V to 2.73 V
|   rising waveform, V_fixture 3.3V, R_fixture 200Ohm: 20-80 % time 166ps typ, 215ps min, 136ps max; typ from 0.567 V to 3.29 V
|   falling waveform, V_fixture 0V, R_fixture 200Ohm: 20-80 % time 306ps typ, 476ps min, 237ps max; typ from 2.73 V to 0 V
[Pulldown]
|   Voltage   I(typ)   I(min)   I(max)
-2V       -4.403mA   -4.924mA   -24.58mA
-1.993V   -4.541mA   -4.935mA   -24.61mA
-1.985V   -15.75mA   -4.948mA   -24.64mA
-1.555V   -17.32mA   -7.649mA   -25.19mA
-569.2mV  -12.01mA   -8.684mA   -15.16mA
1.468V    32.96mA    22.51mA    43.09mA
2.183V    42.73mA    27.07mA    56.27mA
3.307V    44.1mA     27.11mA    58.01mA
3.891V    40.53mA    15.22mA    57.91mA
4.329V    31.6mA     4.414mA    50.42mA
4.804V    16.53mA    1.646mA    38.17mA
5.3V      5.73mA     980.5uA    23.02mA
[GND Clamp]
|   Voltage   I(typ)   I(min)   I(max)
-2V       -410.9mA   -357.8mA   -461.6mA
-1.131V   -95.88mA   -89.85mA   -107.5mA
-1.044V   -67.26mA   -66.47mA   -74.28mA
-956.1mV  -41.12mA   -45.67mA   -43.15mA
-890.4mV  -24.69mA   -32.08mA   -23.29mA
-868.5mV  -20.06mA   -27.93mA   -18mA
-824.7mV  -12.38mA   -20.23mA   -10.63mA
-766.3mV  -6.461mA   -11.63mA   -7.141mA
-678.7mV  -3.852mA   -4.224mA   -5.05mA
-481.6mV  -933.3uA   -750.8uA   -1.355mA
-167.7mV  -19.2uA    -17.52uA   -23.23uA
5.3V      0A         0A         0A
[Pullup]
|   Voltage   I(typ)   I(min)   I(max)
-2V       4.752mA    1.124mA    12.3mA
-1.934V   2.806mA    1.026mA    11.78mA
-1.328V   11.59mA    2.48mA     18.37mA
-985.3mV  13.84mA    5.379mA    17.21mA
-408.6mV  9.312mA    7.134mA    11.39mA
1.876V    -43.95mA   -32.6mA    -56.83mA
2.541V    -55.65mA   -39.95mA   -72.73mA
3.001V    -59.83mA   -41.53mA   -79.7mA
3.497V    -61.57mA   -41.03mA   -83.07mA
4.066V    -57.61mA   -32.28mA   -84.35mA
4.628V    -48.27mA   -21.7mA    -74.5mA
5.3V      -32.69mA   -18.12mA   -61.39mA
[POWER Clamp]
|   Voltage   I(typ)   I(min)   I(max)
-2V       56.9mA     56.65mA    67.87mA
-1.372V   24.83mA    28.04mA    27.27mA
-1.109V   15.55mA    18.96mA    19mA
-1.08V    14.65mA    17.98mA    18.19mA
-875.8mV  9.479mA    11.35mA    12.76mA
-642.2mV  4.989mA    4.86mA     7.11mA
-561.9mV  3.657mA    3.229mA    5.37mA
-525.4mV  3.096mA    2.63mA     4.625mA
-350.2mV  993.5uA    808.4uA    1.647mA
-167.7mV  400.7uA    316.7uA    540.2uA
3.475V    0A         0A         21.35uA
5.3V      0A         0A         0A
[Ramp]
R_load = 200
|   typ   min   max
dV/dt_r   1.63732/1.78034e-10   1.38912/2.60118e-10   1.8756/1.40222e-10
dV/dt_f   1.6322/3.50701e-10   1.37062/5.55357e-10   1.86834/2.65882e-10
[Falling Waveform]
V_fixture = 3.3V
V_fixture_min = 2.97V
V_fixture_max = 3.63V
R_fixture = 200Ohm
C_fixture = 0F
|   Time   V(typ)   V(min)   V(max)
0s        3.288V     2.958V     3.617V
281.4ps   3.292V     2.961V     3.608V
621.9ps   2.97V      2.851V     3.109V
836.6ps   2.632V     2.631V     1.735V
972ps     1.992V     2.518V     848.5mV
1.19ns    945.9mV    2.23V      535.6mV
1.315ns   688.3mV    1.862V     519.3mV
1.618ns   591.7mV    999.6mV    507mV
2.014ns   573.3mV    722.1mV    503.3mV
12ns      567.3mV    673.8mV    502.8mV
[Rising Waveform]
V_fixture = 0V
V_fixture_min = 0V
V_fixture_max = 0V
R_fixture = 200Ohm
C_fixture = 0F
|   Time   V(typ)   V(min)   V(max)
0s        499.4nV    8.058uV    302.6nV
511.1ps   -19.27mV   -1.031mV   175mV
602.4ps   40.71mV    -10.64mV   781.5mV
752ps     477mV      -2.823mV   2.705V
825.4ps   1.075V     24.63mV    3.01V
944.2ps   2.204V     153.2mV    3.111V
1.064ns   2.618V     542.4mV    3.118V
1.337ns   2.714V     1.953V     3.125V
1.662ns   2.726V     2.281V     3.125V
12ns      2.729V     2.315V     3.126V
[Rising Waveform]
V_fixture = 3.3V
V_fixture_min = 2.97V
V_fixture_max = 3.63V
R_fixture = 200Ohm
C_fixture = 0F
|   Time   V(typ)   V(min)   V(max)
0s        567.3mV    673.8mV    502.8mV
495.2ps   546.9mV    673.3mV    652.1mV
581ps     586.5mV    663.8mV    1.263V
677.8ps   791.4mV    651.2mV    2.7V
726.4ps   1.052V     661.1mV    3.185V
914.8ps   2.831V     859.2mV    3.603V
1.019ns   3.177V     1.34V      3.609V
1.233ns   3.274V     2.628V     3.617V
1.546ns   3.288V     2.934V     3.617V
12ns      3.288V     2.958V     3.617V
[Falling Waveform]
|Gnd
V_fixture = 0V
V_fixture_min = 0V
V_fixture_max = 0V
R_fixture = 200Ohm
C_fixture = 0F
|   Time   V(typ)   V(min)   V(max)
0s        2.729V     2.316V     3.126V
281.4ps   2.734V     2.32V      3.116V
577.9ps   2.433V     2.242V     2.629V
658.9ps   2.32V      2.152V     2.208V
768.3ps   2.073V     2.017V     1.279V
884.1ps   1.456V     1.875V     386.3mV
1.078ns   385.8mV    1.509V     24.37mV
1.433ns   15.81mV    338.8mV    1.701mV
1.811ns   1.771mV    24.38mV    308.1uV
12ns      647.5nV    8.309uV    386.5nV
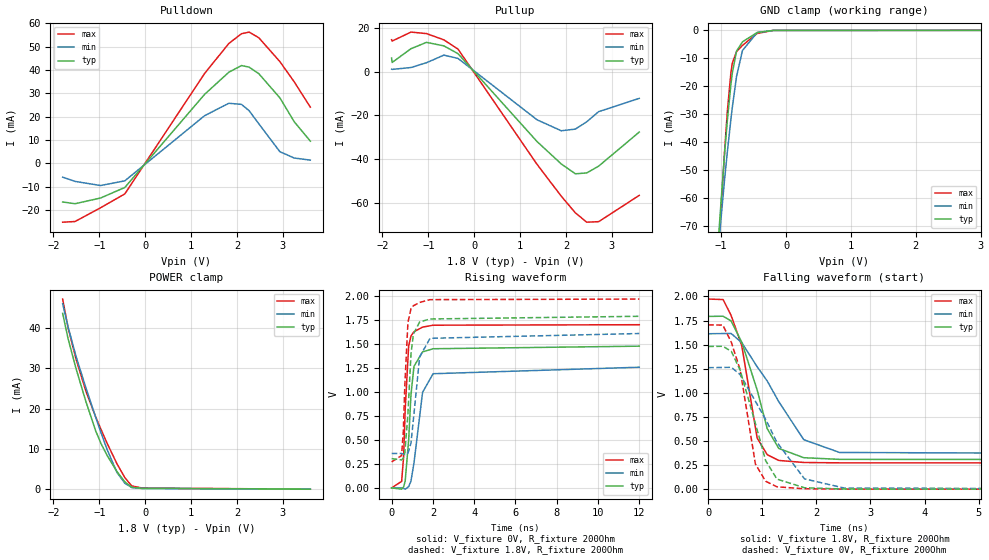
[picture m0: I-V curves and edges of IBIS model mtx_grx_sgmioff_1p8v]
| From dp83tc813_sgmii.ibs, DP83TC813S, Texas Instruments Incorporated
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| mtx_grx_sgmioff_1p8v
[Model]   mtx_grx_sgmioff_1p8v
Model_type   I/O
Polarity   Non-Inverting
Enable   Active-Low
Vinl = 0.63
Vinh = 1.17
Vmeas = 0.9
Vref = 0.9
Cref = 15pF
Rref = 50
|   typ   min   max
C_comp   3.94pF   3.63pF   4.18pF
[Voltage Range]   1.8   1.62   1.98
[Temperature Range]   27   150   -40
[Pullup Reference]   1.8   1.62   1.98
[Pulldown Reference]   0   -0   -0
[Power Clamp Reference]   1.8   1.62   1.98
[GND Clamp Reference]   0   0   0
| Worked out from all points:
|   slope of the pulldown table from 0 to 0.27 V, typ, clamps not added: 41.1 ohm
|   slope of the pullup table from 0 to 0.27 V, typ, clamps not added: 40.5 ohm
|   GND clamp passes 1 mA (typ) near -0.46 V on its own axis
|   POWER clamp passes 1 mA (typ) near -0.37 V on its own axis
|   falling waveform, V_fixture 1.8V, R_fixture 200Ohm: 20-80 % time 462ps typ, 823ps min, 313ps max; typ from 1.79 V to 0.306 V
|   rising waveform, V_fixture 0V, R_fixture 200Ohm: 20-80 % time 249ps typ, 431ps min, 186ps max; typ from 0 V to 1.48 V
|   rising waveform, V_fixture 1.8V, R_fixture 200Ohm: 20-80 % time 231ps typ, 335ps min, 179ps max; typ from 0.306 V to 1.79 V
|   falling waveform, V_fixture 0V, R_fixture 200Ohm: 20-80 % time 431ps typ, 749ps min, 297ps max; typ from 1.48 V to 0 V
[Pulldown]
|   Voltage   I(typ)   I(min)   I(max)
-1.8V     -16.61mA   -5.947mA   -25.29mA
-1.53V    -17.36mA   -7.777mA   -25mA
-973.8mV  -14.92mA   -9.557mA   -19.1mA
-444.6mV  -10.39mA   -7.539mA   -13.15mA
1.294V    29.56mA    20.41mA    38.51mA
1.823V    39.07mA    25.75mA    51.41mA
2.099V    41.94mA    25.27mA    55.59mA
2.266V    41.26mA    22.56mA    56.3mA
2.477V    38.44mA    16.93mA    53.86mA
2.936V    28.08mA    4.971mA    43.64mA
3.249V    17.82mA    2.251mA    34.94mA
3.6V      9.489mA    1.359mA    24.09mA
[GND Clamp]
|   Voltage   I(typ)   I(min)   I(max)
-1.8V     -367.3mA   -326.1mA   -410.8mA
-1.039V   -73.64mA   -77.18mA   -78.28mA
-1.006V   -62.71mA   -68.38mA   -65.4mA
-946.8mV  -44.01mA   -53.33mA   -43.09mA
-903.6mV  -31.97mA   -43.3mA    -28.73mA
-849.6mV  -19.38mA   -31.81mA   -15.13mA
-828mV    -15.29mA   -27.58mA   -11.73mA
-763.2mV  -7.451mA   -16.53mA   -7.627mA
-671.4mV  -4.115mA   -7.212mA   -5.377mA
-444.6mV  -782.5uA   -792.5uA   -1.13mA
-196.2mV  -27.91uA   -43.92uA   -30.12uA
3.6V      0A         0A         0A
[Pullup]
|   Voltage   I(typ)   I(min)   I(max)
-1.8V     6.22mA     1.188mA    14.62mA
-1.789V   4.219mA    1.05mA     14.02mA
-1.379V   10.52mA    1.904mA    18.13mA
-1.039V   13.43mA    4.114mA    17.44mA
-660.6mV  11.82mA    7.583mA    14.58mA
-352.8mV  8.262mA    6.081mA    10.34mA
1.37V     -31.95mA   -22mA      -42.39mA
1.899V    -42.23mA   -27.04mA   -56.98mA
2.207V    -46.73mA   -26.27mA   -64.62mA
2.455V    -46.33mA   -22.91mA   -68.88mA
2.714V    -43.23mA   -18.28mA   -68.64mA
3.6V      -27.62mA   -12.21mA   -56.59mA
[POWER Clamp]
|   Voltage   I(typ)   I(min)   I(max)
-1.8V     43.64mA    46.02mA    47.18mA
-1.681V   37.31mA    40.26mA    40.01mA
-1.508V   29.91mA    32.94mA    32.26mA
-1.292V   21.69mA    25.11mA    24.27mA
-1.082V   14.53mA    17.91mA    18.01mA
-963mV    11.29mA    13.99mA    14.8mA
-828mV    8.315mA    9.758mA    11.32mA
-617.4mV  4.395mA    4.184mA    6.332mA
-444.6mV  1.812mA    1.467mA    2.879mA
-293.4mV  464.4uA    404.7uA    796.9uA
-66.6mV   211.3uA    161.7uA    282.4uA
3.6V      0A         0A         0A
[Ramp]
R_load = 200
|   typ   min   max
dV/dt_r   0.88867/2.49458e-10   0.756387/4.29241e-10   1.02289/1.85586e-10
dV/dt_f   0.892058/4.60479e-10   0.751663/8.21963e-10   1.02018/3.11686e-10
[Falling Waveform]
V_fixture = 1.8V
V_fixture_min = 1.62V
V_fixture_max = 1.98V
R_fixture = 200Ohm
C_fixture = 0F
|   Time   V(typ)   V(min)   V(max)
0s        1.793V     1.613V     1.973V
275.6ps   1.795V     1.615V     1.968V
423.9ps   1.746V     1.616V     1.803V
621.4ps   1.524V     1.52V      1.488V
904.8ps   1.03V      1.271V     530.6mV
1.091ns   628.5mV    1.123V     357.9mV
1.304ns   423.1mV    908.4mV    298.3mV
1.767ns   326.5mV    513.3mV    276.9mV
2.429ns   309.3mV    380.9mV    273.2mV
12ns      306.2mV    360.1mV    272.3mV
[Rising Waveform]
V_fixture = 0V
V_fixture_min = 0V
V_fixture_max = 0V
R_fixture = 200Ohm
C_fixture = 0F
|   Time   V(typ)   V(min)   V(max)
0s        530.7nV    17.44uV    -23.11nV
485.8ps   -12.87mV   -263.3uV   68.26mV
581.2ps   10.36mV    -6.688mV   325.8mV
657.8ps   72.58mV    -13.02mV   819.4mV
825.8ps   501.4mV    13.76mV    1.484V
938.1ps   976mV      72.05mV    1.587V
1.083ns   1.27V      259.5mV    1.632V
1.5ns     1.421V     998.9mV    1.68V
2.01ns    1.454V     1.193V     1.7V
12ns      1.481V     1.261V     1.705V
[Rising Waveform]
V_fixture = 1.8V
V_fixture_min = 1.62V
V_fixture_max = 1.98V
R_fixture = 200Ohm
C_fixture = 0F
|   Time   V(typ)   V(min)   V(max)
0s        306.2mV    360.1mV    272.3mV
480.2ps   292.4mV    359.9mV    337.4mV
565.1ps   308.2mV    354.1mV    579.5mV
639.5ps   366.9mV    347.2mV    1.068V
789.6ps   770.7mV    362.4mV    1.727V
938.1ps   1.398V     467.2mV    1.872V
1.057ns   1.608V     718.6mV    1.903V
1.358ns   1.734V     1.369V     1.938V
1.863ns   1.765V     1.563V     1.967V
12ns      1.793V     1.613V     1.973V
[Falling Waveform]
|Gnd
V_fixture = 0V
V_fixture_min = 0V
V_fixture_max = 0V
R_fixture = 200Ohm
C_fixture = 0F
|   Time   V(typ)   V(min)   V(max)
0s        1.481V     1.261V     1.705V
270.6ps   1.483V     1.263V     1.703V
426.9ps   1.431V     1.265V     1.525V
589.8ps   1.236V     1.19V      1.241V
873.2ps   680.9mV    911.7mV    259.4mV
1.062ns   296mV      724.1mV    82.36mV
1.27ns    104.6mV    486.9mV    24.54mV
1.78ns    14.6mV     107.2mV    3.927mV
2.518ns   1.314mV    11.14mV    893.2uV
12ns      754.1nV    17.44uV    293.2nV
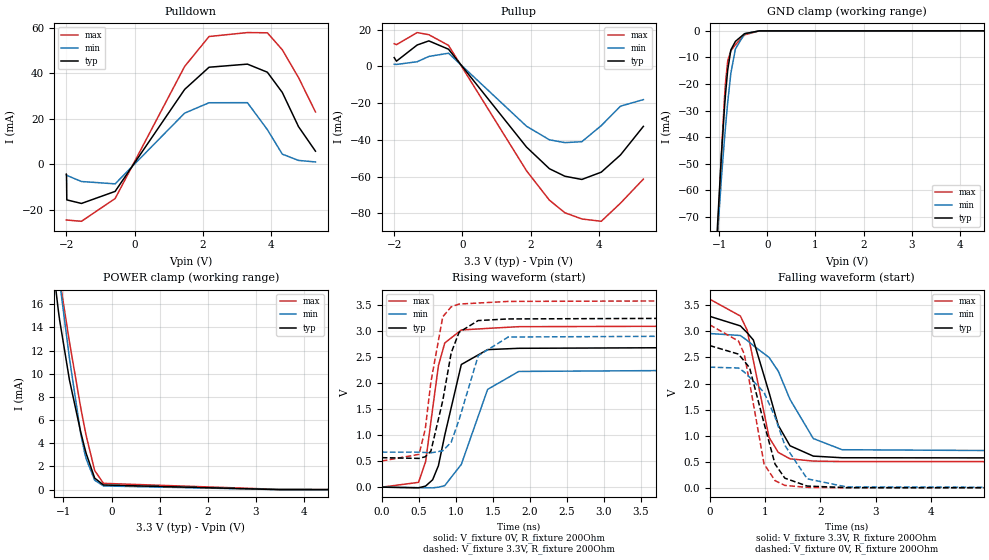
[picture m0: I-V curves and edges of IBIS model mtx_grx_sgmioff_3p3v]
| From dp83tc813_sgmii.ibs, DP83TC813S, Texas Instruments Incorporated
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| mtx_grx_sgmioff_3p3v
[Model]   mtx_grx_sgmioff_3p3v
Model_type   I/O
Polarity   Non-Inverting
Enable   Active-Low
Vinl = 0.8
Vinh = 2
Vmeas = 1.65
Vref = 1.65
Cref = 2pF
Rref = 100000
|   typ   min   max
C_comp   3.93pF   3.63pF   4.16pF
[Voltage Range]   3.3   2.97   3.63
[Temperature Range]   27   150   -40
[Pullup Reference]   3.3   2.97   3.63
[Pulldown Reference]   0   0   0
[Power Clamp Reference]   3.3   2.97   3.63
[GND Clamp Reference]   0   0   0
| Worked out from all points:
|   slope of the pulldown table from 0 to 0.495 V, typ, clamps not added: 41.6 ohm
|   slope of the pullup table from 0 to 0.495 V, typ, clamps not added: 39.9 ohm
|   GND clamp passes 1 mA (typ) near -0.47 V on its own axis
|   POWER clamp passes 1 mA (typ) near -0.35 V on its own axis
|   falling waveform, V_fixture 3.3V, R_fixture 200Ohm: 20-80 % time 439ps typ, 646ps min, 345ps max; typ from 3.29 V to 0.567 V
|   rising waveform, V_fixture 0V, R_fixture 200Ohm: 20-80 % time 231ps typ, 337ps min, 181ps max; typ from 0 V to 2.73 V
|   rising waveform, V_fixture 3.3V, R_fixture 200Ohm: 20-80 % time 214ps typ, 281ps min, 174ps max; typ from 0.567 V to 3.29 V
|   falling waveform, V_fixture 0V, R_fixture 200Ohm: 20-80 % time 380ps typ, 546ps min, 302ps max; typ from 2.73 V to 0 V
[Pulldown]
|   Voltage   I(typ)   I(min)   I(max)
-2V       -4.403mA   -4.924mA   -24.58mA
-1.993V   -4.541mA   -4.935mA   -24.61mA
-1.985V   -15.75mA   -4.948mA   -24.64mA
-1.555V   -17.32mA   -7.649mA   -25.19mA
-569.2mV  -12.01mA   -8.684mA   -15.16mA
1.468V    32.96mA    22.51mA    43.09mA
2.183V    42.73mA    27.07mA    56.27mA
3.307V    44.1mA     27.11mA    58.01mA
3.891V    40.53mA    15.22mA    57.91mA
4.329V    31.6mA     4.414mA    50.42mA
4.804V    16.53mA    1.646mA    38.17mA
5.3V      5.73mA     980.5uA    23.02mA
[GND Clamp]
|   Voltage   I(typ)   I(min)   I(max)
-2V       -448.2mA   -395.2mA   -502.5mA
-1.087V   -90.76mA   -91.15mA   -98.28mA
-1.036V   -72.88mA   -76.57mA   -77.4mA
-956.1mV  -46.79mA   -55.59mA   -46.43mA
-890.4mV  -28.62mA   -40.39mA   -24.86mA
-868.5mV  -23.44mA   -35.7mA    -19.16mA
-824.7mV  -14.72mA   -26.95mA   -11.33mA
-759mV    -7.171mA   -15.93mA   -7.504mA
-664.1mV  -3.966mA   -6.787mA   -5.211mA
-474.3mV  -1.07mA    -1.139mA   -1.526mA
-167.7mV  -21.25uA   -29.12uA   -24.07uA
5.3V      0A         0A         0A
[Pullup]
|   Voltage   I(typ)   I(min)   I(max)
-2V       4.752mA    1.124mA    12.3mA
-1.934V   2.806mA    1.026mA    11.78mA
-1.328V   11.59mA    2.48mA     18.37mA
-985.3mV  13.84mA    5.379mA    17.21mA
-408.6mV  9.312mA    7.134mA    11.39mA
1.876V    -43.94mA   -32.6mA    -56.83mA
2.548V    -55.74mA   -40mA      -72.87mA
3.001V    -59.83mA   -41.53mA   -79.7mA
3.497V    -61.57mA   -41.03mA   -83.07mA
4.066V    -57.61mA   -32.28mA   -84.35mA
4.628V    -48.27mA   -21.7mA    -74.5mA
5.3V      -32.69mA   -18.12mA   -61.39mA
[POWER Clamp]
|   Voltage   I(typ)   I(min)   I(max)
-2V       56.9mA     56.65mA    67.87mA
-1.372V   24.83mA    28.04mA    27.27mA
-1.109V   15.55mA    18.96mA    19mA
-1.08V    14.65mA    17.98mA    18.19mA
-875.8mV  9.479mA    11.35mA    12.76mA
-642.2mV  4.989mA    4.86mA     7.11mA
-561.9mV  3.657mA    3.229mA    5.37mA
-525.4mV  3.096mA    2.63mA     4.625mA
-350.2mV  993.5uA    808.4uA    1.647mA
-167.7mV  400.7uA    316.7uA    540.2uA
3.475V    0A         0A         21.33uA
5.3V      0A         0A         0A
[Ramp]
R_load = 200
|   typ   min   max
dV/dt_r   1.63633/2.29827e-10   1.38767/3.363e-10   1.87489/1.80345e-10
dV/dt_f   1.63217/4.36188e-10   1.37059/6.42916e-10   1.86831/3.43836e-10
[Falling Waveform]
V_fixture = 3.3V
V_fixture_min = 2.97V
V_fixture_max = 3.63V
R_fixture = 200Ohm
C_fixture = 0F
|   Time   V(typ)   V(min)   V(max)
0s        3.288V     2.958V     3.617V
555.4ps   3.104V     2.92V      3.293V
677.8ps   2.973V     2.825V     3.022V
790.3ps   2.833V     2.726V     2.436V
1.074ns   1.825V     2.499V     967.4mV
1.24ns    1.198V     2.237V     679.9mV
1.452ns   806.9mV    1.696V     555.9mV
1.873ns   608.5mV    945.3mV    513.3mV
2.394ns   577.1mV    731mV      504.7mV
12ns      567.3mV    673.8mV    502.8mV
[Rising Waveform]
V_fixture = 0V
V_fixture_min = 0V
V_fixture_max = 0V
R_fixture = 200Ohm
C_fixture = 0F
|   Time   V(typ)   V(min)   V(max)
0s        590.6nV    18.16uV    264.9nV
496.7ps   -12.22mV   -9.714mV   92.42mV
592.3ps   20.88mV    -11.59mV   490.1mV
687.2ps   142.6mV    -13.45mV   1.51V
765.2ps   413.5mV    -1.063mV   2.336V
850.6ps   999.3mV    30.56mV    2.773V
1.074ns   2.359V     437.5mV    3.024V
1.429ns   2.646V     1.88V      3.054V
1.85ns    2.671V     2.226V     3.087V
12ns      2.727V     2.313V     3.125V
[Rising Waveform]
V_fixture = 3.3V
V_fixture_min = 2.97V
V_fixture_max = 3.63V
R_fixture = 200Ohm
C_fixture = 0F
|   Time   V(typ)   V(min)   V(max)
0s        567.3mV    673.8mV    502.8mV
503.8ps   553.1mV    673.5mV    631.3mV
587.8ps   585.1mV    666.5mV    1.12V
663.7ps   693.6mV    660.1mV    2.025V
823.5ps   1.663V     700.1mV    3.277V
937.7ps   2.584V     865.4mV    3.47V
1.044ns   2.979V     1.296V     3.522V
1.302ns   3.205V     2.528V     3.542V
1.707ns   3.236V     2.888V     3.573V
12ns      3.288V     2.958V     3.617V
[Falling Waveform]
|Gnd
V_fixture = 0V
V_fixture_min = 0V
V_fixture_max = 0V
R_fixture = 200Ohm
C_fixture = 0F
|   Time   V(typ)   V(min)   V(max)
0s        2.727V     2.313V     3.125V
521.3ps   2.563V     2.297V     2.813V
624.8ps   2.431V     2.22V      2.565V
722.3ps   2.3V       2.119V     2.014V
983.1ps   1.237V     1.829V     458.7mV
1.181ns   457.7mV    1.361V     139.1mV
1.359ns   185.8mV    814.7mV    46.99mV
1.763ns   34.54mV    174mV      9.341mV
2.477ns   4.777mV    16.58mV    1.651mV
12ns      686.1nV    18.44uV    359.3nV
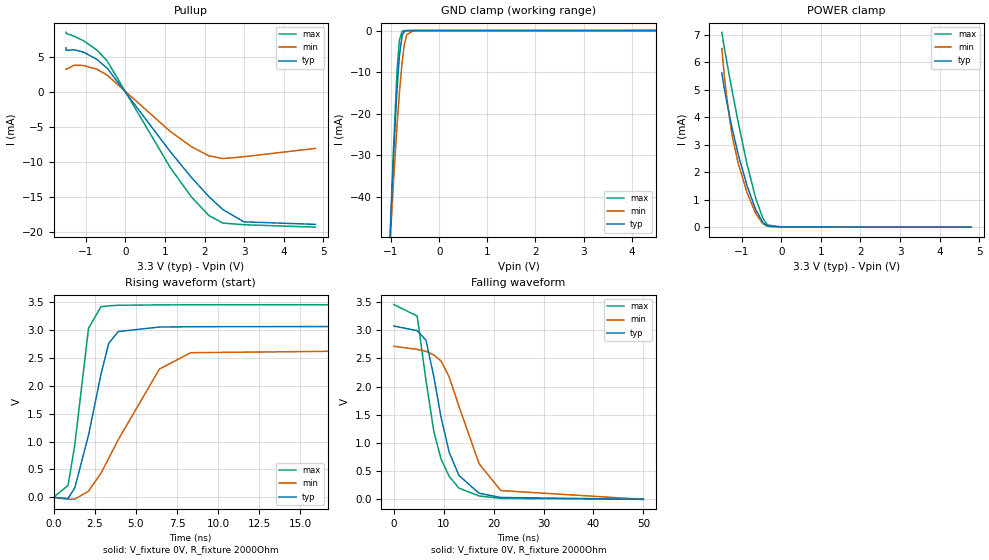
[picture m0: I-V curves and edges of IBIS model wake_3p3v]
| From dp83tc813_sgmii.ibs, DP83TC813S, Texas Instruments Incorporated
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| wake_3p3v
[Model]   wake_3p3v
Model_type   I/O_open_source
Polarity   Non-Inverting
Enable   Active-Low
Vinl = 0.8
Vinh = 2
Vmeas = 1.65
Vref = 3.3
Cref = 2pF
Rref = 2000
|   typ   min   max
C_comp   1.31pF   1.28pF   1.33pF
[Voltage Range]   3.3   2.97   3.63
[Temperature Range]   27   150   -40
[Pullup Reference]   3.3   2.97   3.63
[Pulldown Reference]   0   0   0
[Power Clamp Reference]   3.3   2.97   3.63
[GND Clamp Reference]   0   0   0
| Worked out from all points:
|   slope of the pullup table from 0 to 0.495 V, typ, clamps not added: 130 ohm
|   GND clamp passes 1 mA (typ) near -0.76 V on its own axis
|   POWER clamp passes 1 mA (typ) near -0.74 V on its own axis
|   falling waveform, V_fixture 0V, R_fixture 2000Ohm: 20-80 % time 4.52ns typ, 6.51ns min, 4.01ns max; typ from 3.07 V to 0.001 V
|   rising waveform, V_fixture 0V, R_fixture 2000Ohm: 20-80 % time 1.31ns typ, 3.05ns min, 830ps max; typ from 0.001 V to 3.07 V
[GND Clamp]
|   Voltage   I(typ)   I(min)   I(max)
-1.5V     -203.5mA   -179.8mA   -222.3mA
-1.046V   -56.71mA   -57.19mA   -59.37mA
-1.04V    -54.86mA   -55.72mA   -57.26mA
-1.034V   -53.02mA   -54.27mA   -55.16mA
-951.9mV  -30.66mA   -36.74mA   -29.18mA
-876.3mV  -13.99mA   -22.87mA   -9.738mA
-825.9mV  -5.948mA   -14.86mA   -2.25mA
-769.2mV  -1.162mA   -7.44mA    -158.8uA
-725.1mV  -206.6uA   -3.408mA   -19.12uA
-674.7mV  -26.21uA   -1.019mA   -3.528uA
-536.1mV  -1.341uA   -17.75uA   -1.551uA
4.8V      0A         0A         0A
[Pullup]
|   Voltage   I(typ)   I(min)   I(max)
-1.5V     6.296mA    3.255mA    8.523mA
-1.494V   5.958mA    3.224mA    8.367mA
-1.298V   6.03mA     3.816mA    7.973mA
-1.065V   5.714mA    3.795mA    7.342mA
-718.8mV  4.655mA    3.247mA    5.989mA
-460.5mV  3.399mA    2.399mA    4.441mA
1.133V    -8.525mA   -5.641mA   -10.8mA
1.669V    -12.23mA   -7.824mA   -15.01mA
2.11V     -14.96mA   -9.13mA    -17.66mA
2.463V    -16.81mA   -9.519mA   -18.74mA
2.992V    -18.56mA   -9.257mA   -18.97mA
4.8V      -18.92mA   -8.064mA   -19.32mA
[POWER Clamp]
|   Voltage   I(typ)   I(min)   I(max)
-1.5V     5.612mA    6.506mA    7.092mA
-1.443V   5.088mA    5.608mA    6.581mA
-1.374V   4.558mA    4.701mA    6.017mA
-1.28V    3.876mA    3.696mA    5.27mA
-1.229V   3.531mA    3.26mA     4.88mA
-1.084V   2.634mA    2.31mA     3.797mA
-857.4mV  1.482mA    1.237mA    2.254mA
-643.2mV  633.8uA    491.5uA    1.046mA
-466.8mV  177.1uA    132.3uA    336.9uA
-347.1mV  38.27uA    33.6uA     79.99uA
-13.2mV   7.786uA    5.908uA    10.54uA
4.8V      0A         0A         0A
[Ramp]
R_load = 2000
|   typ   min   max
dV/dt_r   1.84305/1.31157e-09   1.62782/3.04288e-09   2.07226/8.28944e-10
dV/dt_f   1.84305/4.51119e-09   1.62782/6.46793e-09   2.07226/3.98885e-09
[Falling Waveform]
V_fixture = 0V
V_fixture_min = 0V
V_fixture_max = 0V
R_fixture = 2000Ohm
C_fixture = 0F
|   Time   V(typ)   V(min)   V(max)
0s        3.072V     2.713V     3.454V
4.662ns   2.99V      2.658V     3.249V
6.428ns   2.822V     2.624V     2.107V
8.003ns   2.174V     2.559V     1.201V
9.444ns   1.456V     2.453V     715.2mV
11.09ns   830.9mV    2.169V     404.8mV
13.04ns   422.6mV    1.648V     198.6mV
17.08ns   106.8mV    630.5mV    59.39mV
21.42ns   32.9mV     155.5mV    16.84mV
50ns      598.2uV    0V         306uV
[Rising Waveform]
V_fixture = 0V
V_fixture_min = 0V
V_fixture_max = 0V
R_fixture = 2000Ohm
C_fixture = 0F
|   Time   V(typ)   V(min)   V(max)
0s        598.5uV    0V         306.1uV
882ps     -19.89mV   -35.34mV   213.9mV
1.29ns    168.3mV    -31.59mV   935.9mV
2.126ns   1.115V     111mV      3.028V
2.882ns   2.204V     432.5mV    3.415V
3.353ns   2.757V     698.9mV    3.43V
3.934ns   2.97V      1.034V     3.44V
6.434ns   3.05V      2.298V     3.447V
8.334ns   3.056V     2.591V     3.449V
50ns      3.072V     2.713V     3.454V
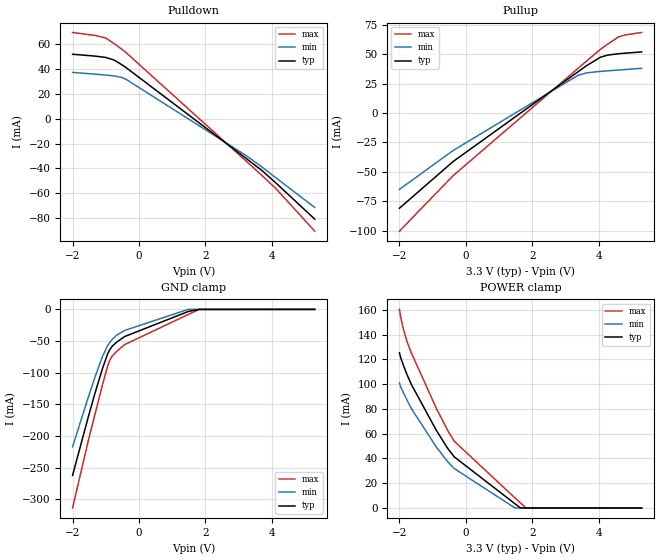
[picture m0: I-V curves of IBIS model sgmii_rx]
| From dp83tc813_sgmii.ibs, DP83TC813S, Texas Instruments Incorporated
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| sgmii_rx
[Model]   sgmii_rx
Model_type   Input
Vinl = 0.1
Vinh = -0.1
|   typ   min   max
C_comp   3.93pF   3.63pF   4.16pF
[Voltage Range]   3.3   2.97   3.63
[Temperature Range]   27   150   -40
[Power Clamp Reference]   3.3   2.97   3.63
[GND Clamp Reference]   0   0   0
[Pulldown]
|   Voltage   I(typ)   I(min)   I(max)
-2V       52.03mA    37.38mA    69.58mA
-1.321V   50.54mA    35.98mA    67.22mA
-1.007V   49.49mA    35.27mA    65.23mA
-744.4mV  47.35mA    34.52mA    60.57mA
-510.8mV  43.49mA    33.26mA    55.96mA
-386.7mV  41.24mA    31.76mA    53.35mA
3.22V     -31.81mA   -29.53mA   -33.92mA
3.716V    -41.99mA   -39.11mA   -46.02mA
4.117V    -51.57mA   -47.46mA   -56.09mA
5.3V      -81.04mA   -71.65mA   -90.72mA
[GND Clamp]
|   Voltage   I(typ)   I(min)   I(max)
-2V       -262.3mA   -217.1mA   -313.8mA
-1.518V   -168.4mA   -137.6mA   -205.8mA
-1.321V   -131.9mA   -106.5mA   -165.1mA
-1.102V   -93.98mA   -74.8mA    -119.7mA
-941.5mV  -70.17mA   -57.24mA   -89.41mA
-890.4mV  -64.71mA   -53.18mA   -81.76mA
-810.1mV  -58.47mA   -47.75mA   -74mA
-686mV    -52.42mA   -41.32mA   -67.26mA
-437.8mV  -43.11mA   -33.41mA   -55.84mA
1.482V    -3.423mA   -49.98uA   -8.129mA
1.811V    0A         0A         -107.3uA
5.3V      0A         0A         0A
[Pullup]
|   Voltage   I(typ)   I(min)   I(max)
-2V       -81.03mA   -64.97mA   -100.5mA
-379.4mV  -41.2mA    -31.81mA   -53.21mA
3.38V     35.08mA    32.1mA     37.98mA
3.643V    40.39mA    34.25mA    44.38mA
4.052V    47.46mA    35.45mA    54.1mA
4.271V    49.32mA    35.94mA    58.56mA
4.592V    50.46mA    36.61mA    64.64mA
4.804V    51mA       37.05mA    66.5mA
5.3V      52.03mA    38.07mA    68.57mA
[POWER Clamp]
|   Voltage   I(typ)   I(min)   I(max)
-2V       125.3mA    101mA      160.3mA
-1.964V   121.5mA    97.86mA    154.3mA
-1.883V   115.3mA    93.22mA    144.5mA
-1.766V   107.3mA    86.75mA    133.9mA
-1.642V   99.79mA    80.33mA    125.2mA
-883.1mV  62.45mA    49mA       80.2mA
-554.6mV  48.46mA    37.63mA    62.99mA
-350.2mV  41.32mA    31.86mA    53.94mA
1.482V    3.423mA    49.36uA    8.129mA
1.643V    148.8uA    0A         4.208mA
1.811V    0A         0A         107.5uA
5.3V      0A         0A         0A
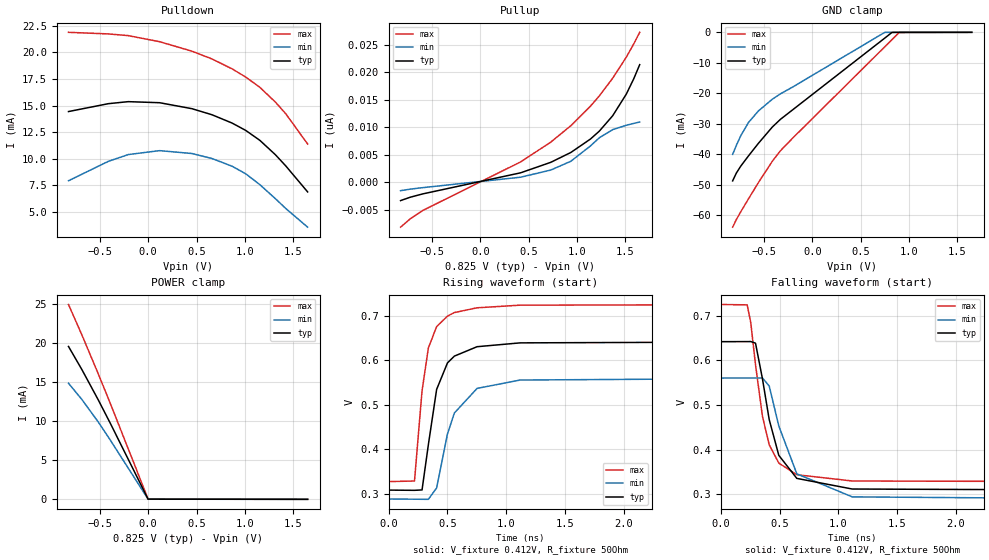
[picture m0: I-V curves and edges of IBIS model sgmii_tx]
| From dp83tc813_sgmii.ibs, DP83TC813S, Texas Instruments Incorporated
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| sgmii_tx
[Model]   sgmii_tx
Model_type   Output
Polarity   Non-Inverting
Vmeas = 0.4125
Vref = 0.4125
Cref = 2pF
Rref = 50
|   typ   min   max
C_comp   4.07pF   3.89pF   4.16pF
[Voltage Range]   0.825   0.75   0.9
[Temperature Range]   27   150   -40
[Pullup Reference]   0.825   0.75   0.9
[Pulldown Reference]   -0   0   -0
[Power Clamp Reference]   0.825   0.75   0.9
[GND Clamp Reference]   0   0   0
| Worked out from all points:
|   POWER clamp passes 1 mA (typ) near -0.04 V on its own axis
|   falling waveform, V_fixture 0.412V, R_fixture 50Ohm: 20-80 % time 170ps typ, 207ps min, 145ps max; typ from 0.642 V to 0.309 V
|   rising waveform, V_fixture 0.412V, R_fixture 50Ohm: 20-80 % time 137ps typ, 181ps min, 108ps max; typ from 0.309 V to 0.642 V
[Pulldown]
|   Voltage   I(typ)   I(min)   I(max)
-825mV    14.44mA    7.942mA    21.88mA
-411.7mV  15.18mA    9.766mA    21.73mA
-206.2mV  15.37mA    10.4mA     21.57mA
118mV     15.27mA    10.77mA    21mA
452.1mV   14.71mA    10.5mA     20.11mA
660mV     14.14mA    10.03mA    19.38mA
867.9mV   13.36mA    9.306mA    18.45mA
1.009V    12.67mA    8.599mA    17.68mA
1.155V    11.74mA    7.579mA    16.72mA
1.316V    10.39mA    6.263mA    15.33mA
1.425V    9.322mA    5.325mA    14.22mA
1.65V     6.893mA    3.584mA    11.39mA
[GND Clamp]
|   Voltage   I(typ)   I(min)   I(max)
-825mV    -48.68mA   -39.98mA   -63.85mA
-787.9mV  -46.19mA   -37.13mA   -61.42mA
-740.9mV  -43.84mA   -33.89mA   -58.8mA
-661.6mV  -40.52mA   -29.57mA   -54.6mA
-557.7mV  -36.35mA   -25.74mA   -49.21mA
-414.2mV  -31.03mA   -21.92mA   -42.24mA
-330mV    -28.5mA    -20.15mA   -38.8mA
-206.2mV  -25.45mA   -17.97mA   -34.75mA
749.1mV   -1.9mA     -16.8uA    -4.752mA
823.4mV   -41.14uA   0A         -2.412mA
897.6mV   0A         0A         -75.26uA
1.65V     0A         0A         0A
[Pullup]
|   Voltage   I(typ)   I(min)   I(max)
-825mV    -3.291nA   -1.491nA   -8.115nA
-723.5mV  -2.67nA    -1.206nA   -6.581nA
-594.8mV  -2.073nA   -938pA     -5.08nA
417.4mV   1.754nA    956.3pA    3.734nA
729.3mV   3.658nA    2.256nA    7.325nA
937.2mV   5.448nA    3.852nA    10.31nA
1.14V     7.885nA    6.634nA    13.86nA
1.232V    9.326nA    8.117nA    15.72nA
1.37V     12.11nA    9.598nA    18.92nA
1.511V    16.04nA    10.39nA    22.76nA
1.588V    18.82nA    10.73nA    25.15nA
1.65V     21.4nA     10.98nA    27.27nA
[POWER Clamp]
|   Voltage   I(typ)   I(min)   I(max)
-825mV    19.57mA    14.86mA    24.94mA
-686.4mV  16.61mA    12.78mA    21.05mA
-518.1mV  12.76mA    9.922mA    16.1mA
-396.8mV  9.847mA    7.67mA     12.42mA
-825uV    20.78uA    16.81uA    26.11uA
1.65V     0A         0A         0A
[Ramp]
R_load = 50
|   typ   min   max
dV/dt_r   0.199883/1.35757e-10   0.163015/1.78968e-10   0.238475/1.08215e-10
dV/dt_f   0.199883/1.68304e-10   0.163015/2.04786e-10   0.238475/1.4437e-10
[Falling Waveform]
V_fixture = 0.412V
V_fixture_min = 0.375V
V_fixture_max = 0.45V
R_fixture = 50Ohm
C_fixture = 0F
|   Time   V(typ)   V(min)   V(max)
0s        641.9mV    560.4mV    725.2mV
225.1ps   642.1mV    560.5mV    724.4mV
255.3ps   642.2mV    560.5mV    685.2mV
296.1ps   638.5mV    560.5mV    589.9mV
354.8ps   558.9mV    560.6mV    474.9mV
412.3ps   467.5mV    542.7mV    411mV
493.8ps   387.3mV    453.2mV    369.9mV
647.1ps   335.6mV    345.8mV    343.8mV
1.118ns   311.8mV    294.2mV    329.8mV
4ns       308.7mV    288.7mV    327.8mV
[Rising Waveform]
V_fixture = 0.412V
V_fixture_min = 0.375V
V_fixture_max = 0.45V
R_fixture = 50Ohm
C_fixture = 0F
|   Time   V(typ)   V(min)   V(max)
0s        308.7mV    288.7mV    327.8mV
220.2ps   308.2mV    288.3mV    329.1mV
284.2ps   309.1mV    288.1mV    531.2mV
337.8ps   410.4mV    288mV      627.6mV
408.1ps   534.6mV    313.5mV    675.6mV
500.3ps   594.1mV    434.7mV    699.1mV
559.1ps   609.4mV    481.8mV    707.1mV
751.9ps   630.5mV    536.9mV    717.8mV
1.118ns   639.1mV    555.7mV    723.7mV
4ns       641.9mV    560.4mV    725.2mV
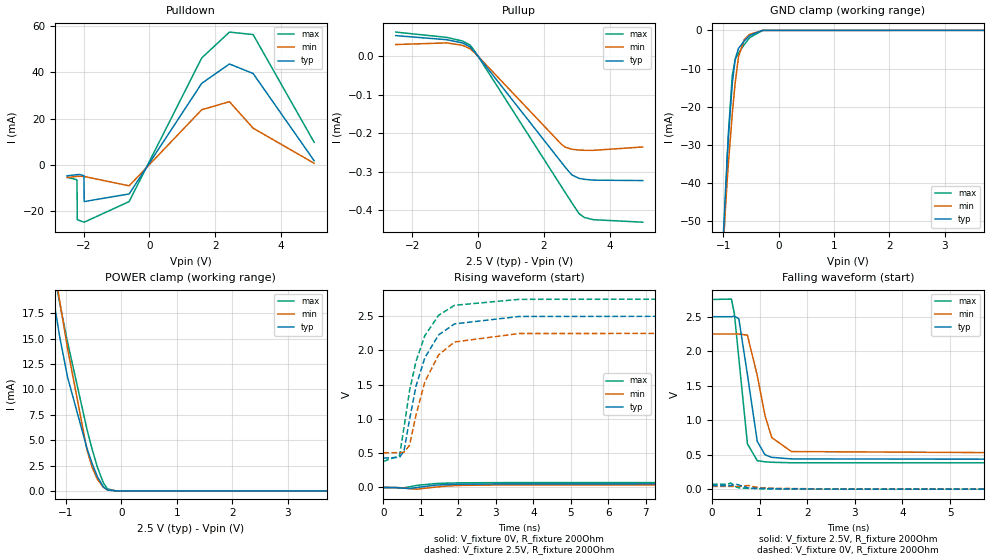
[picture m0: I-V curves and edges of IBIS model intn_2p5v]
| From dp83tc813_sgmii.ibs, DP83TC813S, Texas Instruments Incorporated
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| intn_2p5v
[Model]   intn_2p5v
Model_type   Output
Polarity   Non-Inverting
Vmeas = 1.25
Vref = 1.25
Cref = 2pF
Rref = 100000
|   typ   min   max
C_comp   2.12pF   2.14pF   2.1pF
[Voltage Range]   2.5   2.25   2.75
[Temperature Range]   27   150   -40
[Pullup Reference]   2.5   2.25   2.75
[Pulldown Reference]   0   0   0
[Power Clamp Reference]   2.5   2.25   2.75
[GND Clamp Reference]   0   0   0
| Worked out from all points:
|   slope of the pulldown table from 0 to 0.375 V, typ, clamps not added: 41.3 ohm
|   slope of the pullup table from 0 to 0.375 V, typ, clamps not added: 9.14 kohm
|   GND clamp passes 1 mA (typ) near -0.49 V on its own axis
|   POWER clamp passes 1 mA (typ) near -0.39 V on its own axis
|   falling waveform, V_fixture 2.5V, R_fixture 200Ohm: 20-80 % time 237ps typ, 317ps min, 192ps max; typ from 2.5 V to 0.429 V
|   rising waveform, V_fixture 0V, R_fixture 200Ohm: 20-80 % time 689ps typ, NA min, 658ps max; typ from 0 V to 0.053 V
|   rising waveform, V_fixture 2.5V, R_fixture 200Ohm: 20-80 % time 628ps typ, 633ps min, 621ps max; typ from 0.429 V to 2.5 V
|   falling waveform, V_fixture 0V, R_fixture 200Ohm: 20-80 % time 421ps typ, NA min, 188ps max; typ from 0.053 V to 0 V
[Pulldown]
|   Voltage   I(typ)   I(min)   I(max)
-2.5V     -4.672mA   -5.389mA   -5.307mA
-2.208V   -4.173mA   -4.935mA   -6.345mA
-2.2V     -4.164mA   -4.928mA   -6.817mA
-2.192V   -4.156mA   -4.921mA   -23.54mA
-2.118V   -4.109mA   -4.872mA   -23.98mA
-1.99V    -4.622mA   -4.94mA    -24.62mA
-1.982V   -15.77mA   -4.953mA   -24.65mA
-617.5mV  -12.48mA   -8.98mA    -15.76mA
1.587V    35.18mA    23.8mA     46.1mA
2.428V    43.51mA    27.27mA    57.25mA
3.147V    39.41mA    15.86mA    56.18mA
5V        1.822mA    727.1uA    9.773mA
[GND Clamp]
|   Voltage   I(typ)   I(min)   I(max)
-2.5V     -599.1mA   -518.6mA   -673.8mA
-1.097V   -84.59mA   -80.54mA   -94.49mA
-1.045V   -67.62mA   -66.75mA   -74.69mA
-925mV    -32.85mA   -38.98mA   -33.1mA
-902.5mV  -27.39mA   -34.41mA   -26.49mA
-835mV    -13.92mA   -21.91mA   -11.87mA
-782.5mV  -7.515mA   -13.73mA   -7.638mA
-722.5mV  -4.731mA   -6.96mA    -5.962mA
-617.5mV  -2.758mA   -2.382mA   -3.711mA
-520mV    -1.341mA   -1.064mA   -1.898mA
-287.5mV  -11.02uA   -22.34uA   -13.28uA
5V        0A         0A         0A
[Pullup]
|   Voltage   I(typ)   I(min)   I(max)
-2.5V     53.85uA    30.67uA    63.02uA
-947.5mV  43.17uA    34.92uA    49.17uA
-467.5mV  34.71uA    28.52uA    39.69uA
-242.5mV  24.55uA    19.81uA    29.24uA
-92.5mV   10.08uA    8.314uA    12.38uA
2.533V    -275.9uA   -228.9uA   -338.9uA
2.652V    -288.8uA   -236.4uA   -354.9uA
2.848V    -308.4uA   -241.5uA   -380.8uA
3.065V    -317.2uA   -243.6uA   -408.8uA
3.223V    -319.6uA   -244.2uA   -418.7uA
3.5V      -321.8uA   -244.3uA   -424.6uA
5V        -322.9uA   -235.6uA   -431.1uA
[POWER Clamp]
|   Voltage   I(typ)   I(min)   I(max)
-2.5V     127.3mA    93.84mA    171mA
-1.232V   19.27mA    22.84mA    22.01mA
-1.225V   19.01mA    22.58mA    21.78mA
-1.113V   15.22mA    18.75mA    18.53mA
-970mV    11.21mA    14.03mA    14.66mA
-617.5mV  4.153mA    3.999mA    6.016mA
-527.5mV  2.717mA    2.349mA    4.124mA
-430mV    1.395mA    1.135mA    2.314mA
-325mV    405.8uA    361.6uA    805uA
-250mV    90.46uA    108.1uA    199.1uA
-92.5mV   742.2nA    3.182uA    929.4nA
5V        0A         0A         0A
[Ramp]
R_load = 200
|   typ   min   max
dV/dt_r   0.0319297/6.77548e-10  0.0239607/7.45657e-10  0.0429922/6.53899e-10
dV/dt_f   1.24262/2.36891e-10   1.04585/3.15564e-10   1.42147/1.92087e-10
[Falling Waveform]
V_fixture = 2.5V
V_fixture_min = 2.25V
V_fixture_max = 2.75V
R_fixture = 200Ohm
C_fixture = 0F
|   Time   V(typ)   V(min)   V(max)
0s        2.5V       2.25V      2.75V
407.2ps   2.5V       2.25V      2.756V
469.4ps   2.508V     2.25V      2.543V
563ps     2.471V     2.25V      1.899V
743.5ps   1.661V     2.232V     658.2mV
950.5ps   690.9mV    1.646V     412.6mV
1.114ns   497.7mV    1.063V     396.8mV
1.256ns   461.1mV    747.4mV    390.1mV
1.668ns   438.7mV    545.4mV    382.7mV
12ns      429mV      506.9mV    380.9mV
[Rising Waveform]
V_fixture = 0V
V_fixture_min = 0V
V_fixture_max = 0V
R_fixture = 200Ohm
C_fixture = 0F
|   Time   V(typ)   V(min)   V(max)
0s        506.9nV    8.491uV    201.1nV
329.4ps   -608uV     -197.9uV   -3.419mV
540.2ps   -10.11mV   -5.813mV   -5.53mV
695ps     -16.35mV   -15.85mV   9.664mV
885.6ps   -733.1uV   -24.68mV   29.83mV
1.386ns   34.03mV    5.347mV    57.15mV
1.724ns   43.19mV    21.86mV    64.25mV
2.124ns   48.48mV    31.21mV    68.34mV
3.334ns   52.22mV    38.15mV    71.04mV
12ns      53.22mV    39.94mV    71.65mV
[Rising Waveform]
V_fixture = 2.5V
V_fixture_min = 2.25V
V_fixture_max = 2.75V
R_fixture = 200Ohm
C_fixture = 0F
|   Time   V(typ)   V(min)   V(max)
0s        429mV      506.9mV    380.9mV
431.4ps   439.2mV    507.2mV    463.7mV
549.6ps   532.9mV    514.3mV    878.6mV
696.7ps   989mV      615mV      1.409V
869.5ps   1.478V     1.056V     1.84V
1.104ns   1.891V     1.54V      2.214V
1.472ns   2.226V     1.935V     2.513V
1.899ns   2.388V     2.124V     2.659V
3.625ns   2.496V     2.247V     2.746V
12ns      2.5V       2.25V      2.75V
[Falling Waveform]
|Gnd
V_fixture = 0V
V_fixture_min = 0V
V_fixture_max = 0V
R_fixture = 200Ohm
C_fixture = 0F
|   Time   V(typ)   V(min)   V(max)
0s        53.22mV    39.94mV    71.65mV
323.3ps   52.81mV    39.44mV    71.45mV
392.1ps   52.99mV    39.57mV    89.3mV
514.6ps   71.08mV    39.79mV    28.91mV
580.5ps   56.69mV    40.21mV    17.91mV
757.8ps   17.85mV    53.3mV     11.53mV
971.2ps   11.32mV    22.76mV    7.302mV
1.399ns   6.602mV    10.7mV     1.292mV
2.854ns   120.9uV    916.8uV    29.88uV
12ns      522.9nV    8.598uV    211.9nV
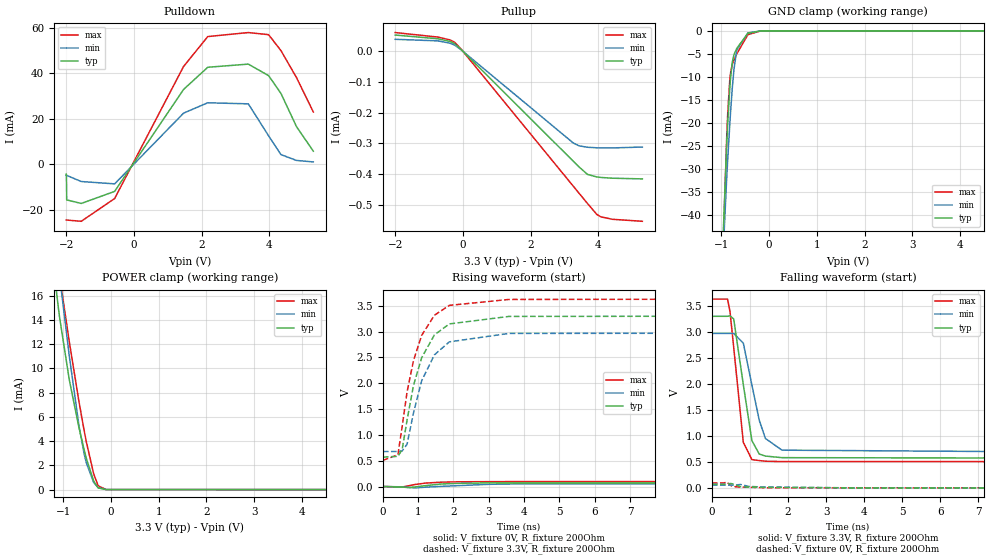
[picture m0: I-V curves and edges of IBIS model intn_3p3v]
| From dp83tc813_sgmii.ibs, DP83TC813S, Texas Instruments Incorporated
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| intn_3p3v
[Model]   intn_3p3v
Model_type   Output
Polarity   Non-Inverting
Vmeas = 1.65
Vref = 1.65
Cref = 2pF
Rref = 100000
|   typ   min   max
C_comp   2.12pF   2.14pF   2.1pF
[Voltage Range]   3.3   2.97   3.63
[Temperature Range]   27   150   -40
[Pullup Reference]   3.3   2.97   3.63
[Pulldown Reference]   0   0   0
[Power Clamp Reference]   3.3   2.97   3.63
[GND Clamp Reference]   0   0   0
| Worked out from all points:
|   slope of the pulldown table from 0 to 0.495 V, typ, clamps not added: 41.6 ohm
|   slope of the pullup table from 0 to 0.495 V, typ, clamps not added: 9.08 kohm
|   GND clamp passes 1 mA (typ) near -0.49 V on its own axis
|   POWER clamp passes 1 mA (typ) near -0.39 V on its own axis
|   falling waveform, V_fixture 3.3V, R_fixture 200Ohm: 20-80 % time 303ps typ, 397ps min, 246ps max; typ from 3.3 V to 0.57 V
|   rising waveform, V_fixture 0V, R_fixture 200Ohm: 20-80 % time 707ps typ, 1.09ns min, 643ps max; typ from 0 V to 0.071 V
|   rising waveform, V_fixture 3.3V, R_fixture 200Ohm: 20-80 % time 627ps typ, 637ps min, 611ps max; typ from 0.57 V to 3.3 V
|   falling waveform, V_fixture 0V, R_fixture 200Ohm: 20-80 % time 414ps typ, 1.82ns min, 176ps max; typ from 0.071 V to 0 V
[Pulldown]
|   Voltage   I(typ)   I(min)   I(max)
-2V       -4.403mA   -4.924mA   -24.58mA
-1.993V   -4.541mA   -4.935mA   -24.61mA
-1.985V   -15.75mA   -4.948mA   -24.64mA
-1.555V   -17.32mA   -7.649mA   -25.19mA
-569.2mV  -12.01mA   -8.684mA   -15.16mA
1.468V    32.96mA    22.51mA    43.09mA
2.183V    42.73mA    27.07mA    56.27mA
3.38V     44.12mA    26.6mA     58.03mA
3.979V    39.05mA    12.51mA    57.1mA
4.344V    31.2mA     4.22mA     50.08mA
4.804V    16.53mA    1.646mA    38.17mA
5.3V      5.73mA     980.5uA    23.02mA
[GND Clamp]
|   Voltage   I(typ)   I(min)   I(max)
-2V       -410.8mA   -357.7mA   -461.5mA
-1.007V   -55.89mA   -57.39mA   -60.86mA
-890.4mV  -24.64mA   -32.04mA   -23.22mA
-868.5mV  -20.01mA   -27.88mA   -17.94mA
-824.7mV  -12.32mA   -20.18mA   -10.57mA
-810.1mV  -10.34mA   -17.83mA   -9.189mA
-773.6mV  -6.863mA   -12.53mA   -7.313mA
-737.1mV  -5.15mA    -8.294mA   -6.305mA
-678.7mV  -3.802mA   -4.182mA   -4.99mA
-445.1mV  -537.1uA   -449.4uA   -823.9uA
-167.7mV  -236.5nA   -1.623uA   -101.3nA
5.3V      0A         0A         0A
[Pullup]
|   Voltage   I(typ)   I(min)   I(max)
-2V       53.08uA    39.2uA     61.12uA
-744.4mV  40.93uA    34.14uA    46.47uA
-386.7mV  32.45uA    26.65uA    37.31uA
-248mV    25.15uA    20.4uA     29.85uA
-65.5mV   7.206uA    5.987uA    8.833uA
3.263V    -358.1uA   -298.7uA   -439.6uA
3.431V    -376.4uA   -307.7uA   -462.1uA
3.679V    -400.7uA   -312.3uA   -495.4uA
3.957V    -409.1uA   -314.1uA   -531.2uA
4.074V    -410.6uA   -314.4uA   -538.9uA
4.417V    -413.1uA   -314.5uA   -546.9uA
5.3V      -415.3uA   -311.6uA   -553.4uA
[POWER Clamp]
|   Voltage   I(typ)   I(min)   I(max)
-2V       56.47mA    56.33mA    67.3mA
-1.248V   19.83mA    23.38mA    22.5mA
-1.109V   15.13mA    18.64mA    18.44mA
-1.08V    14.23mA    17.66mA    17.64mA
-875.8mV  9.061mA    11.03mA    12.2mA
-671.4mV  5.088mA    5.236mA    7.225mA
-561.9mV  3.245mA    2.915mA    4.826mA
-518.1mV  2.577mA    2.208mA    3.938mA
-364.8mV  712.3uA    594.6uA    1.305mA
-269.9mV  142.9uA    154.2uA    311.7uA
-102mV    1.056uA    4.096uA    1.413uA
5.3V      0A         0A         0A
[Ramp]
R_load = 200
|   typ   min   max
dV/dt_r   0.0424813/7.03541e-10  0.0320512/1.09836e-09  0.0571167/6.41768e-10
dV/dt_f   1.63827/3.01358e-10   1.37588/3.96112e-10   1.87517/2.45795e-10
[Falling Waveform]
V_fixture = 3.3V
V_fixture_min = 2.97V
V_fixture_max = 3.63V
R_fixture = 200Ohm
C_fixture = 0F
|   Time   V(typ)   V(min)   V(max)
0s        3.3V       2.97V      3.63V
411.4ps   3.3V       2.97V      3.63V
475.1ps   3.309V     2.97V      3.39V
572.5ps   3.249V     2.97V      2.704V
825.4ps   1.983V     2.784V     873.9mV
1.05ns    909.6mV    1.979V     544mV
1.243ns   650.7mV    1.302V     524.4mV
1.404ns   611.4mV    950.5mV    512.4mV
1.841ns   580.8mV    724.9mV    505.6mV
12ns      569.5mV    676.9mV    504.7mV
[Rising Waveform]
V_fixture = 0V
V_fixture_min = 0V
V_fixture_max = 0V
R_fixture = 200Ohm
C_fixture = 0F
|   Time   V(typ)   V(min)   V(max)
0s        533.7nV    8.789uV    263.7nV
552.9ps   -11.79mV   -6.959mV   -9.501mV
737.9ps   -19.94mV   -18.91mV   14.51mV
903.3ps   -9.013mV   -26.34mV   38.14mV
1.208ns   16.77mV    -13.29mV   65.97mV
1.65ns    48.14mV    2.565mV    83.7mV
2.124ns   61.92mV    16.44mV    90.9mV
3.013ns   68.8mV     42.61mV    94.16mV
3.849ns   70.04mV    50.54mV    94.86mV
12ns      70.8mV     53.43mV    95.19mV
[Rising Waveform]
V_fixture = 3.3V
V_fixture_min = 2.97V
V_fixture_max = 3.63V
R_fixture = 200Ohm
C_fixture = 0F
|   Time   V(typ)   V(min)   V(max)
0s        569.5mV    676.9mV    504.7mV
426.9ps   584mV      677.9mV    616mV
546.4ps   716.8mV    688.6mV    1.163V
685.7ps   1.289V     819.1mV    1.835V
868.2ps   1.962V     1.43V      2.441V
1.099ns   2.495V     2.049V     2.928V
1.46ns    2.937V     2.551V     3.318V
1.882ns   3.15V      2.802V     3.509V
3.57ns    3.295V     2.966V     3.624V
12ns      3.3V       2.97V      3.63V
[Falling Waveform]
|Gnd
V_fixture = 0V
V_fixture_min = 0V
V_fixture_max = 0V
R_fixture = 200Ohm
C_fixture = 0F
|   Time   V(typ)   V(min)   V(max)
0s        70.8mV     53.43mV    95.19mV
323.3ps   70.41mV    52.94mV    95.02mV
390.5ps   70.59mV    53.06mV    112.8mV
495.4ps   84.88mV    53.26mV    43.53mV
576ps     71.05mV    53.59mV    22.85mV
755ps     22.21mV    64.69mV    15.34mV
966.8ps   14.63mV    27.75mV    11.44mV
1.418ns   11.69mV    14.41mV    1.761mV
3.57ns    31.2uV     1.171mV    36.9uV
12ns      538.3nV    8.82uV     289.9nV
